VERSION 5.8 ;
BUSBITCHARS "[]" ;
DIVIDERCHAR "/" ;
UNITS
    DATABASE MICRONS 1000 ;
END UNITS

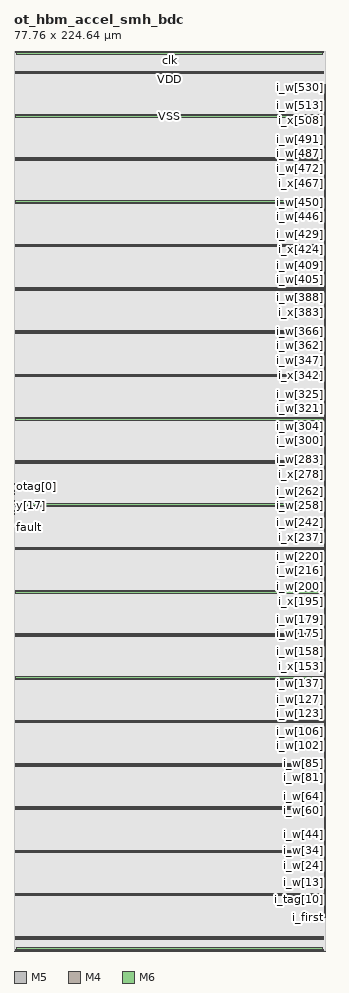
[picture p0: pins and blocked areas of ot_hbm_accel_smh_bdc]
MACRO ot_hbm_accel_smh_bdc
  FOREIGN ot_hbm_accel_smh_bdc 0 0 ;
  CLASS BLOCK ;
  SIZE 77.76 BY 224.64 ;
  PIN clk
    DIRECTION INPUT ;
    USE SIGNAL ;
    PORT
      LAYER M5 ;
        RECT  38.88 224.448 38.904 224.64 ;
    END
  END clk
  PIN fault
    DIRECTION OUTPUT ;
    USE SIGNAL ;
    PORT
      LAYER M4 ;
        RECT  0 107.712 0.192 107.736 ;
    END
  END fault
  PIN i_first
    DIRECTION INPUT ;
    USE SIGNAL ;
    PORT
      LAYER M4 ;
        RECT  77.568 8.448 77.76 8.472 ;
    END
  END i_first
  PIN i_fp4
    DIRECTION INPUT ;
    USE SIGNAL ;
    PORT
      LAYER M4 ;
        RECT  77.568 8.832 77.76 8.856 ;
    END
  END i_fp4
  PIN i_last
    DIRECTION INPUT ;
    USE SIGNAL ;
    PORT
      LAYER M4 ;
        RECT  77.568 8.64 77.76 8.664 ;
    END
  END i_last
  PIN i_tag[0]
    DIRECTION INPUT ;
    USE SIGNAL ;
    PORT
      LAYER M4 ;
        RECT  77.568 9.024 77.76 9.048 ;
    END
  END i_tag[0]
  PIN i_tag[10]
    DIRECTION INPUT ;
    USE SIGNAL ;
    PORT
      LAYER M4 ;
        RECT  77.568 10.944 77.76 10.968 ;
    END
  END i_tag[10]
  PIN i_tag[11]
    DIRECTION INPUT ;
    USE SIGNAL ;
    PORT
      LAYER M4 ;
        RECT  77.568 11.136 77.76 11.16 ;
    END
  END i_tag[11]
  PIN i_tag[12]
    DIRECTION INPUT ;
    USE SIGNAL ;
    PORT
      LAYER M4 ;
        RECT  77.568 11.328 77.76 11.352 ;
    END
  END i_tag[12]
  PIN i_tag[13]
    DIRECTION INPUT ;
    USE SIGNAL ;
    PORT
      LAYER M4 ;
        RECT  77.568 11.52 77.76 11.544 ;
    END
  END i_tag[13]
  PIN i_tag[14]
    DIRECTION INPUT ;
    USE SIGNAL ;
    PORT
      LAYER M4 ;
        RECT  77.568 11.712 77.76 11.736 ;
    END
  END i_tag[14]
  PIN i_tag[15]
    DIRECTION INPUT ;
    USE SIGNAL ;
    PORT
      LAYER M4 ;
        RECT  77.568 11.904 77.76 11.928 ;
    END
  END i_tag[15]
  PIN i_tag[1]
    DIRECTION INPUT ;
    USE SIGNAL ;
    PORT
      LAYER M4 ;
        RECT  77.568 9.216 77.76 9.24 ;
    END
  END i_tag[1]
  PIN i_tag[2]
    DIRECTION INPUT ;
    USE SIGNAL ;
    PORT
      LAYER M4 ;
        RECT  77.568 9.408 77.76 9.432 ;
    END
  END i_tag[2]
  PIN i_tag[3]
    DIRECTION INPUT ;
    USE SIGNAL ;
    PORT
      LAYER M4 ;
        RECT  77.568 9.6 77.76 9.624 ;
    END
  END i_tag[3]
  PIN i_tag[4]
    DIRECTION INPUT ;
    USE SIGNAL ;
    PORT
      LAYER M4 ;
        RECT  77.568 9.792 77.76 9.816 ;
    END
  END i_tag[4]
  PIN i_tag[5]
    DIRECTION INPUT ;
    USE SIGNAL ;
    PORT
      LAYER M4 ;
        RECT  77.568 9.984 77.76 10.008 ;
    END
  END i_tag[5]
  PIN i_tag[6]
    DIRECTION INPUT ;
    USE SIGNAL ;
    PORT
      LAYER M4 ;
        RECT  77.568 10.176 77.76 10.2 ;
    END
  END i_tag[6]
  PIN i_tag[7]
    DIRECTION INPUT ;
    USE SIGNAL ;
    PORT
      LAYER M4 ;
        RECT  77.568 10.368 77.76 10.392 ;
    END
  END i_tag[7]
  PIN i_tag[8]
    DIRECTION INPUT ;
    USE SIGNAL ;
    PORT
      LAYER M4 ;
        RECT  77.568 10.56 77.76 10.584 ;
    END
  END i_tag[8]
  PIN i_tag[9]
    DIRECTION INPUT ;
    USE SIGNAL ;
    PORT
      LAYER M4 ;
        RECT  77.568 10.752 77.76 10.776 ;
    END
  END i_tag[9]
  PIN i_v
    DIRECTION INPUT ;
    USE SIGNAL ;
    PORT
      LAYER M4 ;
        RECT  77.568 8.256 77.76 8.28 ;
    END
  END i_v
  PIN i_w[0]
    DIRECTION INPUT ;
    USE SIGNAL ;
    PORT
      LAYER M4 ;
        RECT  77.568 12.096 77.76 12.12 ;
    END
  END i_w[0]
  PIN i_w[100]
    DIRECTION INPUT ;
    USE SIGNAL ;
    PORT
      LAYER M4 ;
        RECT  77.568 50.496 77.76 50.52 ;
    END
  END i_w[100]
  PIN i_w[101]
    DIRECTION INPUT ;
    USE SIGNAL ;
    PORT
      LAYER M4 ;
        RECT  77.568 50.88 77.76 50.904 ;
    END
  END i_w[101]
  PIN i_w[102]
    DIRECTION INPUT ;
    USE SIGNAL ;
    PORT
      LAYER M4 ;
        RECT  77.568 51.264 77.76 51.288 ;
    END
  END i_w[102]
  PIN i_w[103]
    DIRECTION INPUT ;
    USE SIGNAL ;
    PORT
      LAYER M4 ;
        RECT  77.568 51.648 77.76 51.672 ;
    END
  END i_w[103]
  PIN i_w[104]
    DIRECTION INPUT ;
    USE SIGNAL ;
    PORT
      LAYER M4 ;
        RECT  77.568 52.032 77.76 52.056 ;
    END
  END i_w[104]
  PIN i_w[105]
    DIRECTION INPUT ;
    USE SIGNAL ;
    PORT
      LAYER M4 ;
        RECT  77.568 52.416 77.76 52.44 ;
    END
  END i_w[105]
  PIN i_w[106]
    DIRECTION INPUT ;
    USE SIGNAL ;
    PORT
      LAYER M4 ;
        RECT  77.568 52.8 77.76 52.824 ;
    END
  END i_w[106]
  PIN i_w[107]
    DIRECTION INPUT ;
    USE SIGNAL ;
    PORT
      LAYER M4 ;
        RECT  77.568 53.184 77.76 53.208 ;
    END
  END i_w[107]
  PIN i_w[108]
    DIRECTION INPUT ;
    USE SIGNAL ;
    PORT
      LAYER M4 ;
        RECT  77.568 53.568 77.76 53.592 ;
    END
  END i_w[108]
  PIN i_w[109]
    DIRECTION INPUT ;
    USE SIGNAL ;
    PORT
      LAYER M4 ;
        RECT  77.568 53.952 77.76 53.976 ;
    END
  END i_w[109]
  PIN i_w[10]
    DIRECTION INPUT ;
    USE SIGNAL ;
    PORT
      LAYER M4 ;
        RECT  77.568 15.936 77.76 15.96 ;
    END
  END i_w[10]
  PIN i_w[110]
    DIRECTION INPUT ;
    USE SIGNAL ;
    PORT
      LAYER M4 ;
        RECT  77.568 54.336 77.76 54.36 ;
    END
  END i_w[110]
  PIN i_w[111]
    DIRECTION INPUT ;
    USE SIGNAL ;
    PORT
      LAYER M4 ;
        RECT  77.568 54.72 77.76 54.744 ;
    END
  END i_w[111]
  PIN i_w[112]
    DIRECTION INPUT ;
    USE SIGNAL ;
    PORT
      LAYER M4 ;
        RECT  77.568 55.104 77.76 55.128 ;
    END
  END i_w[112]
  PIN i_w[113]
    DIRECTION INPUT ;
    USE SIGNAL ;
    PORT
      LAYER M4 ;
        RECT  77.568 55.488 77.76 55.512 ;
    END
  END i_w[113]
  PIN i_w[114]
    DIRECTION INPUT ;
    USE SIGNAL ;
    PORT
      LAYER M4 ;
        RECT  77.568 55.872 77.76 55.896 ;
    END
  END i_w[114]
  PIN i_w[115]
    DIRECTION INPUT ;
    USE SIGNAL ;
    PORT
      LAYER M4 ;
        RECT  77.568 56.256 77.76 56.28 ;
    END
  END i_w[115]
  PIN i_w[116]
    DIRECTION INPUT ;
    USE SIGNAL ;
    PORT
      LAYER M4 ;
        RECT  77.568 56.64 77.76 56.664 ;
    END
  END i_w[116]
  PIN i_w[117]
    DIRECTION INPUT ;
    USE SIGNAL ;
    PORT
      LAYER M4 ;
        RECT  77.568 57.024 77.76 57.048 ;
    END
  END i_w[117]
  PIN i_w[118]
    DIRECTION INPUT ;
    USE SIGNAL ;
    PORT
      LAYER M4 ;
        RECT  77.568 57.408 77.76 57.432 ;
    END
  END i_w[118]
  PIN i_w[119]
    DIRECTION INPUT ;
    USE SIGNAL ;
    PORT
      LAYER M4 ;
        RECT  77.568 57.792 77.76 57.816 ;
    END
  END i_w[119]
  PIN i_w[11]
    DIRECTION INPUT ;
    USE SIGNAL ;
    PORT
      LAYER M4 ;
        RECT  77.568 16.32 77.76 16.344 ;
    END
  END i_w[11]
  PIN i_w[120]
    DIRECTION INPUT ;
    USE SIGNAL ;
    PORT
      LAYER M4 ;
        RECT  77.568 58.176 77.76 58.2 ;
    END
  END i_w[120]
  PIN i_w[121]
    DIRECTION INPUT ;
    USE SIGNAL ;
    PORT
      LAYER M4 ;
        RECT  77.568 58.56 77.76 58.584 ;
    END
  END i_w[121]
  PIN i_w[122]
    DIRECTION INPUT ;
    USE SIGNAL ;
    PORT
      LAYER M4 ;
        RECT  77.568 58.944 77.76 58.968 ;
    END
  END i_w[122]
  PIN i_w[123]
    DIRECTION INPUT ;
    USE SIGNAL ;
    PORT
      LAYER M4 ;
        RECT  77.568 59.328 77.76 59.352 ;
    END
  END i_w[123]
  PIN i_w[124]
    DIRECTION INPUT ;
    USE SIGNAL ;
    PORT
      LAYER M4 ;
        RECT  77.568 59.712 77.76 59.736 ;
    END
  END i_w[124]
  PIN i_w[125]
    DIRECTION INPUT ;
    USE SIGNAL ;
    PORT
      LAYER M4 ;
        RECT  77.568 60.096 77.76 60.12 ;
    END
  END i_w[125]
  PIN i_w[126]
    DIRECTION INPUT ;
    USE SIGNAL ;
    PORT
      LAYER M4 ;
        RECT  77.568 60.48 77.76 60.504 ;
    END
  END i_w[126]
  PIN i_w[127]
    DIRECTION INPUT ;
    USE SIGNAL ;
    PORT
      LAYER M4 ;
        RECT  77.568 60.864 77.76 60.888 ;
    END
  END i_w[127]
  PIN i_w[128]
    DIRECTION INPUT ;
    USE SIGNAL ;
    PORT
      LAYER M4 ;
        RECT  77.568 61.248 77.76 61.272 ;
    END
  END i_w[128]
  PIN i_w[129]
    DIRECTION INPUT ;
    USE SIGNAL ;
    PORT
      LAYER M4 ;
        RECT  77.568 61.632 77.76 61.656 ;
    END
  END i_w[129]
  PIN i_w[12]
    DIRECTION INPUT ;
    USE SIGNAL ;
    PORT
      LAYER M4 ;
        RECT  77.568 16.704 77.76 16.728 ;
    END
  END i_w[12]
  PIN i_w[130]
    DIRECTION INPUT ;
    USE SIGNAL ;
    PORT
      LAYER M4 ;
        RECT  77.568 62.016 77.76 62.04 ;
    END
  END i_w[130]
  PIN i_w[131]
    DIRECTION INPUT ;
    USE SIGNAL ;
    PORT
      LAYER M4 ;
        RECT  77.568 62.4 77.76 62.424 ;
    END
  END i_w[131]
  PIN i_w[132]
    DIRECTION INPUT ;
    USE SIGNAL ;
    PORT
      LAYER M4 ;
        RECT  77.568 62.784 77.76 62.808 ;
    END
  END i_w[132]
  PIN i_w[133]
    DIRECTION INPUT ;
    USE SIGNAL ;
    PORT
      LAYER M4 ;
        RECT  77.568 63.168 77.76 63.192 ;
    END
  END i_w[133]
  PIN i_w[134]
    DIRECTION INPUT ;
    USE SIGNAL ;
    PORT
      LAYER M4 ;
        RECT  77.568 63.552 77.76 63.576 ;
    END
  END i_w[134]
  PIN i_w[135]
    DIRECTION INPUT ;
    USE SIGNAL ;
    PORT
      LAYER M4 ;
        RECT  77.568 63.936 77.76 63.96 ;
    END
  END i_w[135]
  PIN i_w[136]
    DIRECTION INPUT ;
    USE SIGNAL ;
    PORT
      LAYER M4 ;
        RECT  77.568 64.32 77.76 64.344 ;
    END
  END i_w[136]
  PIN i_w[137]
    DIRECTION INPUT ;
    USE SIGNAL ;
    PORT
      LAYER M4 ;
        RECT  77.568 64.704 77.76 64.728 ;
    END
  END i_w[137]
  PIN i_w[138]
    DIRECTION INPUT ;
    USE SIGNAL ;
    PORT
      LAYER M4 ;
        RECT  77.568 65.088 77.76 65.112 ;
    END
  END i_w[138]
  PIN i_w[139]
    DIRECTION INPUT ;
    USE SIGNAL ;
    PORT
      LAYER M4 ;
        RECT  77.568 65.472 77.76 65.496 ;
    END
  END i_w[139]
  PIN i_w[13]
    DIRECTION INPUT ;
    USE SIGNAL ;
    PORT
      LAYER M4 ;
        RECT  77.568 17.088 77.76 17.112 ;
    END
  END i_w[13]
  PIN i_w[140]
    DIRECTION INPUT ;
    USE SIGNAL ;
    PORT
      LAYER M4 ;
        RECT  77.568 65.856 77.76 65.88 ;
    END
  END i_w[140]
  PIN i_w[141]
    DIRECTION INPUT ;
    USE SIGNAL ;
    PORT
      LAYER M4 ;
        RECT  77.568 66.24 77.76 66.264 ;
    END
  END i_w[141]
  PIN i_w[142]
    DIRECTION INPUT ;
    USE SIGNAL ;
    PORT
      LAYER M4 ;
        RECT  77.568 66.624 77.76 66.648 ;
    END
  END i_w[142]
  PIN i_w[143]
    DIRECTION INPUT ;
    USE SIGNAL ;
    PORT
      LAYER M4 ;
        RECT  77.568 67.008 77.76 67.032 ;
    END
  END i_w[143]
  PIN i_w[144]
    DIRECTION INPUT ;
    USE SIGNAL ;
    PORT
      LAYER M4 ;
        RECT  77.568 67.392 77.76 67.416 ;
    END
  END i_w[144]
  PIN i_w[145]
    DIRECTION INPUT ;
    USE SIGNAL ;
    PORT
      LAYER M4 ;
        RECT  77.568 67.776 77.76 67.8 ;
    END
  END i_w[145]
  PIN i_w[146]
    DIRECTION INPUT ;
    USE SIGNAL ;
    PORT
      LAYER M4 ;
        RECT  77.568 68.16 77.76 68.184 ;
    END
  END i_w[146]
  PIN i_w[147]
    DIRECTION INPUT ;
    USE SIGNAL ;
    PORT
      LAYER M4 ;
        RECT  77.568 68.544 77.76 68.568 ;
    END
  END i_w[147]
  PIN i_w[148]
    DIRECTION INPUT ;
    USE SIGNAL ;
    PORT
      LAYER M4 ;
        RECT  77.568 68.928 77.76 68.952 ;
    END
  END i_w[148]
  PIN i_w[149]
    DIRECTION INPUT ;
    USE SIGNAL ;
    PORT
      LAYER M4 ;
        RECT  77.568 69.312 77.76 69.336 ;
    END
  END i_w[149]
  PIN i_w[14]
    DIRECTION INPUT ;
    USE SIGNAL ;
    PORT
      LAYER M4 ;
        RECT  77.568 17.472 77.76 17.496 ;
    END
  END i_w[14]
  PIN i_w[150]
    DIRECTION INPUT ;
    USE SIGNAL ;
    PORT
      LAYER M4 ;
        RECT  77.568 69.696 77.76 69.72 ;
    END
  END i_w[150]
  PIN i_w[151]
    DIRECTION INPUT ;
    USE SIGNAL ;
    PORT
      LAYER M4 ;
        RECT  77.568 70.08 77.76 70.104 ;
    END
  END i_w[151]
  PIN i_w[152]
    DIRECTION INPUT ;
    USE SIGNAL ;
    PORT
      LAYER M4 ;
        RECT  77.568 70.464 77.76 70.488 ;
    END
  END i_w[152]
  PIN i_w[153]
    DIRECTION INPUT ;
    USE SIGNAL ;
    PORT
      LAYER M4 ;
        RECT  77.568 70.848 77.76 70.872 ;
    END
  END i_w[153]
  PIN i_w[154]
    DIRECTION INPUT ;
    USE SIGNAL ;
    PORT
      LAYER M4 ;
        RECT  77.568 71.232 77.76 71.256 ;
    END
  END i_w[154]
  PIN i_w[155]
    DIRECTION INPUT ;
    USE SIGNAL ;
    PORT
      LAYER M4 ;
        RECT  77.568 71.616 77.76 71.64 ;
    END
  END i_w[155]
  PIN i_w[156]
    DIRECTION INPUT ;
    USE SIGNAL ;
    PORT
      LAYER M4 ;
        RECT  77.568 72 77.76 72.024 ;
    END
  END i_w[156]
  PIN i_w[157]
    DIRECTION INPUT ;
    USE SIGNAL ;
    PORT
      LAYER M4 ;
        RECT  77.568 72.384 77.76 72.408 ;
    END
  END i_w[157]
  PIN i_w[158]
    DIRECTION INPUT ;
    USE SIGNAL ;
    PORT
      LAYER M4 ;
        RECT  77.568 72.768 77.76 72.792 ;
    END
  END i_w[158]
  PIN i_w[159]
    DIRECTION INPUT ;
    USE SIGNAL ;
    PORT
      LAYER M4 ;
        RECT  77.568 73.152 77.76 73.176 ;
    END
  END i_w[159]
  PIN i_w[15]
    DIRECTION INPUT ;
    USE SIGNAL ;
    PORT
      LAYER M4 ;
        RECT  77.568 17.856 77.76 17.88 ;
    END
  END i_w[15]
  PIN i_w[160]
    DIRECTION INPUT ;
    USE SIGNAL ;
    PORT
      LAYER M4 ;
        RECT  77.568 73.536 77.76 73.56 ;
    END
  END i_w[160]
  PIN i_w[161]
    DIRECTION INPUT ;
    USE SIGNAL ;
    PORT
      LAYER M4 ;
        RECT  77.568 73.92 77.76 73.944 ;
    END
  END i_w[161]
  PIN i_w[162]
    DIRECTION INPUT ;
    USE SIGNAL ;
    PORT
      LAYER M4 ;
        RECT  77.568 74.304 77.76 74.328 ;
    END
  END i_w[162]
  PIN i_w[163]
    DIRECTION INPUT ;
    USE SIGNAL ;
    PORT
      LAYER M4 ;
        RECT  77.568 74.688 77.76 74.712 ;
    END
  END i_w[163]
  PIN i_w[164]
    DIRECTION INPUT ;
    USE SIGNAL ;
    PORT
      LAYER M4 ;
        RECT  77.568 75.072 77.76 75.096 ;
    END
  END i_w[164]
  PIN i_w[165]
    DIRECTION INPUT ;
    USE SIGNAL ;
    PORT
      LAYER M4 ;
        RECT  77.568 75.456 77.76 75.48 ;
    END
  END i_w[165]
  PIN i_w[166]
    DIRECTION INPUT ;
    USE SIGNAL ;
    PORT
      LAYER M4 ;
        RECT  77.568 75.84 77.76 75.864 ;
    END
  END i_w[166]
  PIN i_w[167]
    DIRECTION INPUT ;
    USE SIGNAL ;
    PORT
      LAYER M4 ;
        RECT  77.568 76.224 77.76 76.248 ;
    END
  END i_w[167]
  PIN i_w[168]
    DIRECTION INPUT ;
    USE SIGNAL ;
    PORT
      LAYER M4 ;
        RECT  77.568 76.608 77.76 76.632 ;
    END
  END i_w[168]
  PIN i_w[169]
    DIRECTION INPUT ;
    USE SIGNAL ;
    PORT
      LAYER M4 ;
        RECT  77.568 76.992 77.76 77.016 ;
    END
  END i_w[169]
  PIN i_w[16]
    DIRECTION INPUT ;
    USE SIGNAL ;
    PORT
      LAYER M4 ;
        RECT  77.568 18.24 77.76 18.264 ;
    END
  END i_w[16]
  PIN i_w[170]
    DIRECTION INPUT ;
    USE SIGNAL ;
    PORT
      LAYER M4 ;
        RECT  77.568 77.376 77.76 77.4 ;
    END
  END i_w[170]
  PIN i_w[171]
    DIRECTION INPUT ;
    USE SIGNAL ;
    PORT
      LAYER M4 ;
        RECT  77.568 77.76 77.76 77.784 ;
    END
  END i_w[171]
  PIN i_w[172]
    DIRECTION INPUT ;
    USE SIGNAL ;
    PORT
      LAYER M4 ;
        RECT  77.568 78.144 77.76 78.168 ;
    END
  END i_w[172]
  PIN i_w[173]
    DIRECTION INPUT ;
    USE SIGNAL ;
    PORT
      LAYER M4 ;
        RECT  77.568 78.528 77.76 78.552 ;
    END
  END i_w[173]
  PIN i_w[174]
    DIRECTION INPUT ;
    USE SIGNAL ;
    PORT
      LAYER M4 ;
        RECT  77.568 78.912 77.76 78.936 ;
    END
  END i_w[174]
  PIN i_w[175]
    DIRECTION INPUT ;
    USE SIGNAL ;
    PORT
      LAYER M4 ;
        RECT  77.568 79.296 77.76 79.32 ;
    END
  END i_w[175]
  PIN i_w[176]
    DIRECTION INPUT ;
    USE SIGNAL ;
    PORT
      LAYER M4 ;
        RECT  77.568 79.68 77.76 79.704 ;
    END
  END i_w[176]
  PIN i_w[177]
    DIRECTION INPUT ;
    USE SIGNAL ;
    PORT
      LAYER M4 ;
        RECT  77.568 80.064 77.76 80.088 ;
    END
  END i_w[177]
  PIN i_w[178]
    DIRECTION INPUT ;
    USE SIGNAL ;
    PORT
      LAYER M4 ;
        RECT  77.568 80.448 77.76 80.472 ;
    END
  END i_w[178]
  PIN i_w[179]
    DIRECTION INPUT ;
    USE SIGNAL ;
    PORT
      LAYER M4 ;
        RECT  77.568 80.832 77.76 80.856 ;
    END
  END i_w[179]
  PIN i_w[17]
    DIRECTION INPUT ;
    USE SIGNAL ;
    PORT
      LAYER M4 ;
        RECT  77.568 18.624 77.76 18.648 ;
    END
  END i_w[17]
  PIN i_w[180]
    DIRECTION INPUT ;
    USE SIGNAL ;
    PORT
      LAYER M4 ;
        RECT  77.568 81.216 77.76 81.24 ;
    END
  END i_w[180]
  PIN i_w[181]
    DIRECTION INPUT ;
    USE SIGNAL ;
    PORT
      LAYER M4 ;
        RECT  77.568 81.6 77.76 81.624 ;
    END
  END i_w[181]
  PIN i_w[182]
    DIRECTION INPUT ;
    USE SIGNAL ;
    PORT
      LAYER M4 ;
        RECT  77.568 81.984 77.76 82.008 ;
    END
  END i_w[182]
  PIN i_w[183]
    DIRECTION INPUT ;
    USE SIGNAL ;
    PORT
      LAYER M4 ;
        RECT  77.568 82.368 77.76 82.392 ;
    END
  END i_w[183]
  PIN i_w[184]
    DIRECTION INPUT ;
    USE SIGNAL ;
    PORT
      LAYER M4 ;
        RECT  77.568 82.752 77.76 82.776 ;
    END
  END i_w[184]
  PIN i_w[185]
    DIRECTION INPUT ;
    USE SIGNAL ;
    PORT
      LAYER M4 ;
        RECT  77.568 83.136 77.76 83.16 ;
    END
  END i_w[185]
  PIN i_w[186]
    DIRECTION INPUT ;
    USE SIGNAL ;
    PORT
      LAYER M4 ;
        RECT  77.568 83.52 77.76 83.544 ;
    END
  END i_w[186]
  PIN i_w[187]
    DIRECTION INPUT ;
    USE SIGNAL ;
    PORT
      LAYER M4 ;
        RECT  77.568 83.904 77.76 83.928 ;
    END
  END i_w[187]
  PIN i_w[188]
    DIRECTION INPUT ;
    USE SIGNAL ;
    PORT
      LAYER M4 ;
        RECT  77.568 84.288 77.76 84.312 ;
    END
  END i_w[188]
  PIN i_w[189]
    DIRECTION INPUT ;
    USE SIGNAL ;
    PORT
      LAYER M4 ;
        RECT  77.568 84.672 77.76 84.696 ;
    END
  END i_w[189]
  PIN i_w[18]
    DIRECTION INPUT ;
    USE SIGNAL ;
    PORT
      LAYER M4 ;
        RECT  77.568 19.008 77.76 19.032 ;
    END
  END i_w[18]
  PIN i_w[190]
    DIRECTION INPUT ;
    USE SIGNAL ;
    PORT
      LAYER M4 ;
        RECT  77.568 85.056 77.76 85.08 ;
    END
  END i_w[190]
  PIN i_w[191]
    DIRECTION INPUT ;
    USE SIGNAL ;
    PORT
      LAYER M4 ;
        RECT  77.568 85.44 77.76 85.464 ;
    END
  END i_w[191]
  PIN i_w[192]
    DIRECTION INPUT ;
    USE SIGNAL ;
    PORT
      LAYER M4 ;
        RECT  77.568 85.824 77.76 85.848 ;
    END
  END i_w[192]
  PIN i_w[193]
    DIRECTION INPUT ;
    USE SIGNAL ;
    PORT
      LAYER M4 ;
        RECT  77.568 86.208 77.76 86.232 ;
    END
  END i_w[193]
  PIN i_w[194]
    DIRECTION INPUT ;
    USE SIGNAL ;
    PORT
      LAYER M4 ;
        RECT  77.568 86.592 77.76 86.616 ;
    END
  END i_w[194]
  PIN i_w[195]
    DIRECTION INPUT ;
    USE SIGNAL ;
    PORT
      LAYER M4 ;
        RECT  77.568 86.976 77.76 87 ;
    END
  END i_w[195]
  PIN i_w[196]
    DIRECTION INPUT ;
    USE SIGNAL ;
    PORT
      LAYER M4 ;
        RECT  77.568 87.36 77.76 87.384 ;
    END
  END i_w[196]
  PIN i_w[197]
    DIRECTION INPUT ;
    USE SIGNAL ;
    PORT
      LAYER M4 ;
        RECT  77.568 87.744 77.76 87.768 ;
    END
  END i_w[197]
  PIN i_w[198]
    DIRECTION INPUT ;
    USE SIGNAL ;
    PORT
      LAYER M4 ;
        RECT  77.568 88.128 77.76 88.152 ;
    END
  END i_w[198]
  PIN i_w[199]
    DIRECTION INPUT ;
    USE SIGNAL ;
    PORT
      LAYER M4 ;
        RECT  77.568 88.512 77.76 88.536 ;
    END
  END i_w[199]
  PIN i_w[19]
    DIRECTION INPUT ;
    USE SIGNAL ;
    PORT
      LAYER M4 ;
        RECT  77.568 19.392 77.76 19.416 ;
    END
  END i_w[19]
  PIN i_w[1]
    DIRECTION INPUT ;
    USE SIGNAL ;
    PORT
      LAYER M4 ;
        RECT  77.568 12.48 77.76 12.504 ;
    END
  END i_w[1]
  PIN i_w[200]
    DIRECTION INPUT ;
    USE SIGNAL ;
    PORT
      LAYER M4 ;
        RECT  77.568 88.896 77.76 88.92 ;
    END
  END i_w[200]
  PIN i_w[201]
    DIRECTION INPUT ;
    USE SIGNAL ;
    PORT
      LAYER M4 ;
        RECT  77.568 89.28 77.76 89.304 ;
    END
  END i_w[201]
  PIN i_w[202]
    DIRECTION INPUT ;
    USE SIGNAL ;
    PORT
      LAYER M4 ;
        RECT  77.568 89.664 77.76 89.688 ;
    END
  END i_w[202]
  PIN i_w[203]
    DIRECTION INPUT ;
    USE SIGNAL ;
    PORT
      LAYER M4 ;
        RECT  77.568 90.048 77.76 90.072 ;
    END
  END i_w[203]
  PIN i_w[204]
    DIRECTION INPUT ;
    USE SIGNAL ;
    PORT
      LAYER M4 ;
        RECT  77.568 90.432 77.76 90.456 ;
    END
  END i_w[204]
  PIN i_w[205]
    DIRECTION INPUT ;
    USE SIGNAL ;
    PORT
      LAYER M4 ;
        RECT  77.568 90.816 77.76 90.84 ;
    END
  END i_w[205]
  PIN i_w[206]
    DIRECTION INPUT ;
    USE SIGNAL ;
    PORT
      LAYER M4 ;
        RECT  77.568 91.2 77.76 91.224 ;
    END
  END i_w[206]
  PIN i_w[207]
    DIRECTION INPUT ;
    USE SIGNAL ;
    PORT
      LAYER M4 ;
        RECT  77.568 91.584 77.76 91.608 ;
    END
  END i_w[207]
  PIN i_w[208]
    DIRECTION INPUT ;
    USE SIGNAL ;
    PORT
      LAYER M4 ;
        RECT  77.568 91.968 77.76 91.992 ;
    END
  END i_w[208]
  PIN i_w[209]
    DIRECTION INPUT ;
    USE SIGNAL ;
    PORT
      LAYER M4 ;
        RECT  77.568 92.352 77.76 92.376 ;
    END
  END i_w[209]
  PIN i_w[20]
    DIRECTION INPUT ;
    USE SIGNAL ;
    PORT
      LAYER M4 ;
        RECT  77.568 19.776 77.76 19.8 ;
    END
  END i_w[20]
  PIN i_w[210]
    DIRECTION INPUT ;
    USE SIGNAL ;
    PORT
      LAYER M4 ;
        RECT  77.568 92.736 77.76 92.76 ;
    END
  END i_w[210]
  PIN i_w[211]
    DIRECTION INPUT ;
    USE SIGNAL ;
    PORT
      LAYER M4 ;
        RECT  77.568 93.12 77.76 93.144 ;
    END
  END i_w[211]
  PIN i_w[212]
    DIRECTION INPUT ;
    USE SIGNAL ;
    PORT
      LAYER M4 ;
        RECT  77.568 93.504 77.76 93.528 ;
    END
  END i_w[212]
  PIN i_w[213]
    DIRECTION INPUT ;
    USE SIGNAL ;
    PORT
      LAYER M4 ;
        RECT  77.568 93.888 77.76 93.912 ;
    END
  END i_w[213]
  PIN i_w[214]
    DIRECTION INPUT ;
    USE SIGNAL ;
    PORT
      LAYER M4 ;
        RECT  77.568 94.272 77.76 94.296 ;
    END
  END i_w[214]
  PIN i_w[215]
    DIRECTION INPUT ;
    USE SIGNAL ;
    PORT
      LAYER M4 ;
        RECT  77.568 94.656 77.76 94.68 ;
    END
  END i_w[215]
  PIN i_w[216]
    DIRECTION INPUT ;
    USE SIGNAL ;
    PORT
      LAYER M4 ;
        RECT  77.568 95.04 77.76 95.064 ;
    END
  END i_w[216]
  PIN i_w[217]
    DIRECTION INPUT ;
    USE SIGNAL ;
    PORT
      LAYER M4 ;
        RECT  77.568 95.424 77.76 95.448 ;
    END
  END i_w[217]
  PIN i_w[218]
    DIRECTION INPUT ;
    USE SIGNAL ;
    PORT
      LAYER M4 ;
        RECT  77.568 95.808 77.76 95.832 ;
    END
  END i_w[218]
  PIN i_w[219]
    DIRECTION INPUT ;
    USE SIGNAL ;
    PORT
      LAYER M4 ;
        RECT  77.568 96.192 77.76 96.216 ;
    END
  END i_w[219]
  PIN i_w[21]
    DIRECTION INPUT ;
    USE SIGNAL ;
    PORT
      LAYER M4 ;
        RECT  77.568 20.16 77.76 20.184 ;
    END
  END i_w[21]
  PIN i_w[220]
    DIRECTION INPUT ;
    USE SIGNAL ;
    PORT
      LAYER M4 ;
        RECT  77.568 96.576 77.76 96.6 ;
    END
  END i_w[220]
  PIN i_w[221]
    DIRECTION INPUT ;
    USE SIGNAL ;
    PORT
      LAYER M4 ;
        RECT  77.568 96.96 77.76 96.984 ;
    END
  END i_w[221]
  PIN i_w[222]
    DIRECTION INPUT ;
    USE SIGNAL ;
    PORT
      LAYER M4 ;
        RECT  77.568 97.344 77.76 97.368 ;
    END
  END i_w[222]
  PIN i_w[223]
    DIRECTION INPUT ;
    USE SIGNAL ;
    PORT
      LAYER M4 ;
        RECT  77.568 97.728 77.76 97.752 ;
    END
  END i_w[223]
  PIN i_w[224]
    DIRECTION INPUT ;
    USE SIGNAL ;
    PORT
      LAYER M4 ;
        RECT  77.568 98.112 77.76 98.136 ;
    END
  END i_w[224]
  PIN i_w[225]
    DIRECTION INPUT ;
    USE SIGNAL ;
    PORT
      LAYER M4 ;
        RECT  77.568 98.496 77.76 98.52 ;
    END
  END i_w[225]
  PIN i_w[226]
    DIRECTION INPUT ;
    USE SIGNAL ;
    PORT
      LAYER M4 ;
        RECT  77.568 98.88 77.76 98.904 ;
    END
  END i_w[226]
  PIN i_w[227]
    DIRECTION INPUT ;
    USE SIGNAL ;
    PORT
      LAYER M4 ;
        RECT  77.568 99.264 77.76 99.288 ;
    END
  END i_w[227]
  PIN i_w[228]
    DIRECTION INPUT ;
    USE SIGNAL ;
    PORT
      LAYER M4 ;
        RECT  77.568 99.648 77.76 99.672 ;
    END
  END i_w[228]
  PIN i_w[229]
    DIRECTION INPUT ;
    USE SIGNAL ;
    PORT
      LAYER M4 ;
        RECT  77.568 100.032 77.76 100.056 ;
    END
  END i_w[229]
  PIN i_w[22]
    DIRECTION INPUT ;
    USE SIGNAL ;
    PORT
      LAYER M4 ;
        RECT  77.568 20.544 77.76 20.568 ;
    END
  END i_w[22]
  PIN i_w[230]
    DIRECTION INPUT ;
    USE SIGNAL ;
    PORT
      LAYER M4 ;
        RECT  77.568 100.416 77.76 100.44 ;
    END
  END i_w[230]
  PIN i_w[231]
    DIRECTION INPUT ;
    USE SIGNAL ;
    PORT
      LAYER M4 ;
        RECT  77.568 100.8 77.76 100.824 ;
    END
  END i_w[231]
  PIN i_w[232]
    DIRECTION INPUT ;
    USE SIGNAL ;
    PORT
      LAYER M4 ;
        RECT  77.568 101.184 77.76 101.208 ;
    END
  END i_w[232]
  PIN i_w[233]
    DIRECTION INPUT ;
    USE SIGNAL ;
    PORT
      LAYER M4 ;
        RECT  77.568 101.568 77.76 101.592 ;
    END
  END i_w[233]
  PIN i_w[234]
    DIRECTION INPUT ;
    USE SIGNAL ;
    PORT
      LAYER M4 ;
        RECT  77.568 101.952 77.76 101.976 ;
    END
  END i_w[234]
  PIN i_w[235]
    DIRECTION INPUT ;
    USE SIGNAL ;
    PORT
      LAYER M4 ;
        RECT  77.568 102.336 77.76 102.36 ;
    END
  END i_w[235]
  PIN i_w[236]
    DIRECTION INPUT ;
    USE SIGNAL ;
    PORT
      LAYER M4 ;
        RECT  77.568 102.72 77.76 102.744 ;
    END
  END i_w[236]
  PIN i_w[237]
    DIRECTION INPUT ;
    USE SIGNAL ;
    PORT
      LAYER M4 ;
        RECT  77.568 103.104 77.76 103.128 ;
    END
  END i_w[237]
  PIN i_w[238]
    DIRECTION INPUT ;
    USE SIGNAL ;
    PORT
      LAYER M4 ;
        RECT  77.568 103.488 77.76 103.512 ;
    END
  END i_w[238]
  PIN i_w[239]
    DIRECTION INPUT ;
    USE SIGNAL ;
    PORT
      LAYER M4 ;
        RECT  77.568 103.872 77.76 103.896 ;
    END
  END i_w[239]
  PIN i_w[23]
    DIRECTION INPUT ;
    USE SIGNAL ;
    PORT
      LAYER M4 ;
        RECT  77.568 20.928 77.76 20.952 ;
    END
  END i_w[23]
  PIN i_w[240]
    DIRECTION INPUT ;
    USE SIGNAL ;
    PORT
      LAYER M4 ;
        RECT  77.568 104.256 77.76 104.28 ;
    END
  END i_w[240]
  PIN i_w[241]
    DIRECTION INPUT ;
    USE SIGNAL ;
    PORT
      LAYER M4 ;
        RECT  77.568 104.64 77.76 104.664 ;
    END
  END i_w[241]
  PIN i_w[242]
    DIRECTION INPUT ;
    USE SIGNAL ;
    PORT
      LAYER M4 ;
        RECT  77.568 105.024 77.76 105.048 ;
    END
  END i_w[242]
  PIN i_w[243]
    DIRECTION INPUT ;
    USE SIGNAL ;
    PORT
      LAYER M4 ;
        RECT  77.568 105.408 77.76 105.432 ;
    END
  END i_w[243]
  PIN i_w[244]
    DIRECTION INPUT ;
    USE SIGNAL ;
    PORT
      LAYER M4 ;
        RECT  77.568 105.792 77.76 105.816 ;
    END
  END i_w[244]
  PIN i_w[245]
    DIRECTION INPUT ;
    USE SIGNAL ;
    PORT
      LAYER M4 ;
        RECT  77.568 106.176 77.76 106.2 ;
    END
  END i_w[245]
  PIN i_w[246]
    DIRECTION INPUT ;
    USE SIGNAL ;
    PORT
      LAYER M4 ;
        RECT  77.568 106.56 77.76 106.584 ;
    END
  END i_w[246]
  PIN i_w[247]
    DIRECTION INPUT ;
    USE SIGNAL ;
    PORT
      LAYER M4 ;
        RECT  77.568 106.944 77.76 106.968 ;
    END
  END i_w[247]
  PIN i_w[248]
    DIRECTION INPUT ;
    USE SIGNAL ;
    PORT
      LAYER M4 ;
        RECT  77.568 107.328 77.76 107.352 ;
    END
  END i_w[248]
  PIN i_w[249]
    DIRECTION INPUT ;
    USE SIGNAL ;
    PORT
      LAYER M4 ;
        RECT  77.568 107.712 77.76 107.736 ;
    END
  END i_w[249]
  PIN i_w[24]
    DIRECTION INPUT ;
    USE SIGNAL ;
    PORT
      LAYER M4 ;
        RECT  77.568 21.312 77.76 21.336 ;
    END
  END i_w[24]
  PIN i_w[250]
    DIRECTION INPUT ;
    USE SIGNAL ;
    PORT
      LAYER M4 ;
        RECT  77.568 108.096 77.76 108.12 ;
    END
  END i_w[250]
  PIN i_w[251]
    DIRECTION INPUT ;
    USE SIGNAL ;
    PORT
      LAYER M4 ;
        RECT  77.568 108.48 77.76 108.504 ;
    END
  END i_w[251]
  PIN i_w[252]
    DIRECTION INPUT ;
    USE SIGNAL ;
    PORT
      LAYER M4 ;
        RECT  77.568 108.864 77.76 108.888 ;
    END
  END i_w[252]
  PIN i_w[253]
    DIRECTION INPUT ;
    USE SIGNAL ;
    PORT
      LAYER M4 ;
        RECT  77.568 109.248 77.76 109.272 ;
    END
  END i_w[253]
  PIN i_w[254]
    DIRECTION INPUT ;
    USE SIGNAL ;
    PORT
      LAYER M4 ;
        RECT  77.568 109.632 77.76 109.656 ;
    END
  END i_w[254]
  PIN i_w[255]
    DIRECTION INPUT ;
    USE SIGNAL ;
    PORT
      LAYER M4 ;
        RECT  77.568 110.016 77.76 110.04 ;
    END
  END i_w[255]
  PIN i_w[256]
    DIRECTION INPUT ;
    USE SIGNAL ;
    PORT
      LAYER M4 ;
        RECT  77.568 110.4 77.76 110.424 ;
    END
  END i_w[256]
  PIN i_w[257]
    DIRECTION INPUT ;
    USE SIGNAL ;
    PORT
      LAYER M4 ;
        RECT  77.568 110.784 77.76 110.808 ;
    END
  END i_w[257]
  PIN i_w[258]
    DIRECTION INPUT ;
    USE SIGNAL ;
    PORT
      LAYER M4 ;
        RECT  77.568 111.168 77.76 111.192 ;
    END
  END i_w[258]
  PIN i_w[259]
    DIRECTION INPUT ;
    USE SIGNAL ;
    PORT
      LAYER M4 ;
        RECT  77.568 111.552 77.76 111.576 ;
    END
  END i_w[259]
  PIN i_w[25]
    DIRECTION INPUT ;
    USE SIGNAL ;
    PORT
      LAYER M4 ;
        RECT  77.568 21.696 77.76 21.72 ;
    END
  END i_w[25]
  PIN i_w[260]
    DIRECTION INPUT ;
    USE SIGNAL ;
    PORT
      LAYER M4 ;
        RECT  77.568 111.936 77.76 111.96 ;
    END
  END i_w[260]
  PIN i_w[261]
    DIRECTION INPUT ;
    USE SIGNAL ;
    PORT
      LAYER M4 ;
        RECT  77.568 112.32 77.76 112.344 ;
    END
  END i_w[261]
  PIN i_w[262]
    DIRECTION INPUT ;
    USE SIGNAL ;
    PORT
      LAYER M4 ;
        RECT  77.568 112.704 77.76 112.728 ;
    END
  END i_w[262]
  PIN i_w[263]
    DIRECTION INPUT ;
    USE SIGNAL ;
    PORT
      LAYER M4 ;
        RECT  77.568 113.088 77.76 113.112 ;
    END
  END i_w[263]
  PIN i_w[264]
    DIRECTION INPUT ;
    USE SIGNAL ;
    PORT
      LAYER M4 ;
        RECT  77.568 113.472 77.76 113.496 ;
    END
  END i_w[264]
  PIN i_w[265]
    DIRECTION INPUT ;
    USE SIGNAL ;
    PORT
      LAYER M4 ;
        RECT  77.568 113.856 77.76 113.88 ;
    END
  END i_w[265]
  PIN i_w[266]
    DIRECTION INPUT ;
    USE SIGNAL ;
    PORT
      LAYER M4 ;
        RECT  77.568 114.24 77.76 114.264 ;
    END
  END i_w[266]
  PIN i_w[267]
    DIRECTION INPUT ;
    USE SIGNAL ;
    PORT
      LAYER M4 ;
        RECT  77.568 114.624 77.76 114.648 ;
    END
  END i_w[267]
  PIN i_w[268]
    DIRECTION INPUT ;
    USE SIGNAL ;
    PORT
      LAYER M4 ;
        RECT  77.568 115.008 77.76 115.032 ;
    END
  END i_w[268]
  PIN i_w[269]
    DIRECTION INPUT ;
    USE SIGNAL ;
    PORT
      LAYER M4 ;
        RECT  77.568 115.392 77.76 115.416 ;
    END
  END i_w[269]
  PIN i_w[26]
    DIRECTION INPUT ;
    USE SIGNAL ;
    PORT
      LAYER M4 ;
        RECT  77.568 22.08 77.76 22.104 ;
    END
  END i_w[26]
  PIN i_w[270]
    DIRECTION INPUT ;
    USE SIGNAL ;
    PORT
      LAYER M4 ;
        RECT  77.568 115.776 77.76 115.8 ;
    END
  END i_w[270]
  PIN i_w[271]
    DIRECTION INPUT ;
    USE SIGNAL ;
    PORT
      LAYER M4 ;
        RECT  77.568 116.16 77.76 116.184 ;
    END
  END i_w[271]
  PIN i_w[272]
    DIRECTION INPUT ;
    USE SIGNAL ;
    PORT
      LAYER M4 ;
        RECT  77.568 116.544 77.76 116.568 ;
    END
  END i_w[272]
  PIN i_w[273]
    DIRECTION INPUT ;
    USE SIGNAL ;
    PORT
      LAYER M4 ;
        RECT  77.568 116.928 77.76 116.952 ;
    END
  END i_w[273]
  PIN i_w[274]
    DIRECTION INPUT ;
    USE SIGNAL ;
    PORT
      LAYER M4 ;
        RECT  77.568 117.312 77.76 117.336 ;
    END
  END i_w[274]
  PIN i_w[275]
    DIRECTION INPUT ;
    USE SIGNAL ;
    PORT
      LAYER M4 ;
        RECT  77.568 117.696 77.76 117.72 ;
    END
  END i_w[275]
  PIN i_w[276]
    DIRECTION INPUT ;
    USE SIGNAL ;
    PORT
      LAYER M4 ;
        RECT  77.568 118.08 77.76 118.104 ;
    END
  END i_w[276]
  PIN i_w[277]
    DIRECTION INPUT ;
    USE SIGNAL ;
    PORT
      LAYER M4 ;
        RECT  77.568 118.464 77.76 118.488 ;
    END
  END i_w[277]
  PIN i_w[278]
    DIRECTION INPUT ;
    USE SIGNAL ;
    PORT
      LAYER M4 ;
        RECT  77.568 118.848 77.76 118.872 ;
    END
  END i_w[278]
  PIN i_w[279]
    DIRECTION INPUT ;
    USE SIGNAL ;
    PORT
      LAYER M4 ;
        RECT  77.568 119.232 77.76 119.256 ;
    END
  END i_w[279]
  PIN i_w[27]
    DIRECTION INPUT ;
    USE SIGNAL ;
    PORT
      LAYER M4 ;
        RECT  77.568 22.464 77.76 22.488 ;
    END
  END i_w[27]
  PIN i_w[280]
    DIRECTION INPUT ;
    USE SIGNAL ;
    PORT
      LAYER M4 ;
        RECT  77.568 119.616 77.76 119.64 ;
    END
  END i_w[280]
  PIN i_w[281]
    DIRECTION INPUT ;
    USE SIGNAL ;
    PORT
      LAYER M4 ;
        RECT  77.568 120 77.76 120.024 ;
    END
  END i_w[281]
  PIN i_w[282]
    DIRECTION INPUT ;
    USE SIGNAL ;
    PORT
      LAYER M4 ;
        RECT  77.568 120.384 77.76 120.408 ;
    END
  END i_w[282]
  PIN i_w[283]
    DIRECTION INPUT ;
    USE SIGNAL ;
    PORT
      LAYER M4 ;
        RECT  77.568 120.768 77.76 120.792 ;
    END
  END i_w[283]
  PIN i_w[284]
    DIRECTION INPUT ;
    USE SIGNAL ;
    PORT
      LAYER M4 ;
        RECT  77.568 121.152 77.76 121.176 ;
    END
  END i_w[284]
  PIN i_w[285]
    DIRECTION INPUT ;
    USE SIGNAL ;
    PORT
      LAYER M4 ;
        RECT  77.568 121.536 77.76 121.56 ;
    END
  END i_w[285]
  PIN i_w[286]
    DIRECTION INPUT ;
    USE SIGNAL ;
    PORT
      LAYER M4 ;
        RECT  77.568 121.92 77.76 121.944 ;
    END
  END i_w[286]
  PIN i_w[287]
    DIRECTION INPUT ;
    USE SIGNAL ;
    PORT
      LAYER M4 ;
        RECT  77.568 122.304 77.76 122.328 ;
    END
  END i_w[287]
  PIN i_w[288]
    DIRECTION INPUT ;
    USE SIGNAL ;
    PORT
      LAYER M4 ;
        RECT  77.568 122.688 77.76 122.712 ;
    END
  END i_w[288]
  PIN i_w[289]
    DIRECTION INPUT ;
    USE SIGNAL ;
    PORT
      LAYER M4 ;
        RECT  77.568 123.072 77.76 123.096 ;
    END
  END i_w[289]
  PIN i_w[28]
    DIRECTION INPUT ;
    USE SIGNAL ;
    PORT
      LAYER M4 ;
        RECT  77.568 22.848 77.76 22.872 ;
    END
  END i_w[28]
  PIN i_w[290]
    DIRECTION INPUT ;
    USE SIGNAL ;
    PORT
      LAYER M4 ;
        RECT  77.568 123.456 77.76 123.48 ;
    END
  END i_w[290]
  PIN i_w[291]
    DIRECTION INPUT ;
    USE SIGNAL ;
    PORT
      LAYER M4 ;
        RECT  77.568 123.84 77.76 123.864 ;
    END
  END i_w[291]
  PIN i_w[292]
    DIRECTION INPUT ;
    USE SIGNAL ;
    PORT
      LAYER M4 ;
        RECT  77.568 124.224 77.76 124.248 ;
    END
  END i_w[292]
  PIN i_w[293]
    DIRECTION INPUT ;
    USE SIGNAL ;
    PORT
      LAYER M4 ;
        RECT  77.568 124.608 77.76 124.632 ;
    END
  END i_w[293]
  PIN i_w[294]
    DIRECTION INPUT ;
    USE SIGNAL ;
    PORT
      LAYER M4 ;
        RECT  77.568 124.992 77.76 125.016 ;
    END
  END i_w[294]
  PIN i_w[295]
    DIRECTION INPUT ;
    USE SIGNAL ;
    PORT
      LAYER M4 ;
        RECT  77.568 125.376 77.76 125.4 ;
    END
  END i_w[295]
  PIN i_w[296]
    DIRECTION INPUT ;
    USE SIGNAL ;
    PORT
      LAYER M4 ;
        RECT  77.568 125.76 77.76 125.784 ;
    END
  END i_w[296]
  PIN i_w[297]
    DIRECTION INPUT ;
    USE SIGNAL ;
    PORT
      LAYER M4 ;
        RECT  77.568 126.144 77.76 126.168 ;
    END
  END i_w[297]
  PIN i_w[298]
    DIRECTION INPUT ;
    USE SIGNAL ;
    PORT
      LAYER M4 ;
        RECT  77.568 126.528 77.76 126.552 ;
    END
  END i_w[298]
  PIN i_w[299]
    DIRECTION INPUT ;
    USE SIGNAL ;
    PORT
      LAYER M4 ;
        RECT  77.568 126.912 77.76 126.936 ;
    END
  END i_w[299]
  PIN i_w[29]
    DIRECTION INPUT ;
    USE SIGNAL ;
    PORT
      LAYER M4 ;
        RECT  77.568 23.232 77.76 23.256 ;
    END
  END i_w[29]
  PIN i_w[2]
    DIRECTION INPUT ;
    USE SIGNAL ;
    PORT
      LAYER M4 ;
        RECT  77.568 12.864 77.76 12.888 ;
    END
  END i_w[2]
  PIN i_w[300]
    DIRECTION INPUT ;
    USE SIGNAL ;
    PORT
      LAYER M4 ;
        RECT  77.568 127.296 77.76 127.32 ;
    END
  END i_w[300]
  PIN i_w[301]
    DIRECTION INPUT ;
    USE SIGNAL ;
    PORT
      LAYER M4 ;
        RECT  77.568 127.68 77.76 127.704 ;
    END
  END i_w[301]
  PIN i_w[302]
    DIRECTION INPUT ;
    USE SIGNAL ;
    PORT
      LAYER M4 ;
        RECT  77.568 128.064 77.76 128.088 ;
    END
  END i_w[302]
  PIN i_w[303]
    DIRECTION INPUT ;
    USE SIGNAL ;
    PORT
      LAYER M4 ;
        RECT  77.568 128.448 77.76 128.472 ;
    END
  END i_w[303]
  PIN i_w[304]
    DIRECTION INPUT ;
    USE SIGNAL ;
    PORT
      LAYER M4 ;
        RECT  77.568 128.832 77.76 128.856 ;
    END
  END i_w[304]
  PIN i_w[305]
    DIRECTION INPUT ;
    USE SIGNAL ;
    PORT
      LAYER M4 ;
        RECT  77.568 129.216 77.76 129.24 ;
    END
  END i_w[305]
  PIN i_w[306]
    DIRECTION INPUT ;
    USE SIGNAL ;
    PORT
      LAYER M4 ;
        RECT  77.568 129.6 77.76 129.624 ;
    END
  END i_w[306]
  PIN i_w[307]
    DIRECTION INPUT ;
    USE SIGNAL ;
    PORT
      LAYER M4 ;
        RECT  77.568 129.984 77.76 130.008 ;
    END
  END i_w[307]
  PIN i_w[308]
    DIRECTION INPUT ;
    USE SIGNAL ;
    PORT
      LAYER M4 ;
        RECT  77.568 130.368 77.76 130.392 ;
    END
  END i_w[308]
  PIN i_w[309]
    DIRECTION INPUT ;
    USE SIGNAL ;
    PORT
      LAYER M4 ;
        RECT  77.568 130.752 77.76 130.776 ;
    END
  END i_w[309]
  PIN i_w[30]
    DIRECTION INPUT ;
    USE SIGNAL ;
    PORT
      LAYER M4 ;
        RECT  77.568 23.616 77.76 23.64 ;
    END
  END i_w[30]
  PIN i_w[310]
    DIRECTION INPUT ;
    USE SIGNAL ;
    PORT
      LAYER M4 ;
        RECT  77.568 131.136 77.76 131.16 ;
    END
  END i_w[310]
  PIN i_w[311]
    DIRECTION INPUT ;
    USE SIGNAL ;
    PORT
      LAYER M4 ;
        RECT  77.568 131.52 77.76 131.544 ;
    END
  END i_w[311]
  PIN i_w[312]
    DIRECTION INPUT ;
    USE SIGNAL ;
    PORT
      LAYER M4 ;
        RECT  77.568 131.904 77.76 131.928 ;
    END
  END i_w[312]
  PIN i_w[313]
    DIRECTION INPUT ;
    USE SIGNAL ;
    PORT
      LAYER M4 ;
        RECT  77.568 132.288 77.76 132.312 ;
    END
  END i_w[313]
  PIN i_w[314]
    DIRECTION INPUT ;
    USE SIGNAL ;
    PORT
      LAYER M4 ;
        RECT  77.568 132.672 77.76 132.696 ;
    END
  END i_w[314]
  PIN i_w[315]
    DIRECTION INPUT ;
    USE SIGNAL ;
    PORT
      LAYER M4 ;
        RECT  77.568 133.056 77.76 133.08 ;
    END
  END i_w[315]
  PIN i_w[316]
    DIRECTION INPUT ;
    USE SIGNAL ;
    PORT
      LAYER M4 ;
        RECT  77.568 133.44 77.76 133.464 ;
    END
  END i_w[316]
  PIN i_w[317]
    DIRECTION INPUT ;
    USE SIGNAL ;
    PORT
      LAYER M4 ;
        RECT  77.568 133.824 77.76 133.848 ;
    END
  END i_w[317]
  PIN i_w[318]
    DIRECTION INPUT ;
    USE SIGNAL ;
    PORT
      LAYER M4 ;
        RECT  77.568 134.208 77.76 134.232 ;
    END
  END i_w[318]
  PIN i_w[319]
    DIRECTION INPUT ;
    USE SIGNAL ;
    PORT
      LAYER M4 ;
        RECT  77.568 134.592 77.76 134.616 ;
    END
  END i_w[319]
  PIN i_w[31]
    DIRECTION INPUT ;
    USE SIGNAL ;
    PORT
      LAYER M4 ;
        RECT  77.568 24 77.76 24.024 ;
    END
  END i_w[31]
  PIN i_w[320]
    DIRECTION INPUT ;
    USE SIGNAL ;
    PORT
      LAYER M4 ;
        RECT  77.568 134.976 77.76 135 ;
    END
  END i_w[320]
  PIN i_w[321]
    DIRECTION INPUT ;
    USE SIGNAL ;
    PORT
      LAYER M4 ;
        RECT  77.568 135.36 77.76 135.384 ;
    END
  END i_w[321]
  PIN i_w[322]
    DIRECTION INPUT ;
    USE SIGNAL ;
    PORT
      LAYER M4 ;
        RECT  77.568 135.744 77.76 135.768 ;
    END
  END i_w[322]
  PIN i_w[323]
    DIRECTION INPUT ;
    USE SIGNAL ;
    PORT
      LAYER M4 ;
        RECT  77.568 136.128 77.76 136.152 ;
    END
  END i_w[323]
  PIN i_w[324]
    DIRECTION INPUT ;
    USE SIGNAL ;
    PORT
      LAYER M4 ;
        RECT  77.568 136.512 77.76 136.536 ;
    END
  END i_w[324]
  PIN i_w[325]
    DIRECTION INPUT ;
    USE SIGNAL ;
    PORT
      LAYER M4 ;
        RECT  77.568 136.896 77.76 136.92 ;
    END
  END i_w[325]
  PIN i_w[326]
    DIRECTION INPUT ;
    USE SIGNAL ;
    PORT
      LAYER M4 ;
        RECT  77.568 137.28 77.76 137.304 ;
    END
  END i_w[326]
  PIN i_w[327]
    DIRECTION INPUT ;
    USE SIGNAL ;
    PORT
      LAYER M4 ;
        RECT  77.568 137.664 77.76 137.688 ;
    END
  END i_w[327]
  PIN i_w[328]
    DIRECTION INPUT ;
    USE SIGNAL ;
    PORT
      LAYER M4 ;
        RECT  77.568 138.048 77.76 138.072 ;
    END
  END i_w[328]
  PIN i_w[329]
    DIRECTION INPUT ;
    USE SIGNAL ;
    PORT
      LAYER M4 ;
        RECT  77.568 138.432 77.76 138.456 ;
    END
  END i_w[329]
  PIN i_w[32]
    DIRECTION INPUT ;
    USE SIGNAL ;
    PORT
      LAYER M4 ;
        RECT  77.568 24.384 77.76 24.408 ;
    END
  END i_w[32]
  PIN i_w[330]
    DIRECTION INPUT ;
    USE SIGNAL ;
    PORT
      LAYER M4 ;
        RECT  77.568 138.816 77.76 138.84 ;
    END
  END i_w[330]
  PIN i_w[331]
    DIRECTION INPUT ;
    USE SIGNAL ;
    PORT
      LAYER M4 ;
        RECT  77.568 139.2 77.76 139.224 ;
    END
  END i_w[331]
  PIN i_w[332]
    DIRECTION INPUT ;
    USE SIGNAL ;
    PORT
      LAYER M4 ;
        RECT  77.568 139.584 77.76 139.608 ;
    END
  END i_w[332]
  PIN i_w[333]
    DIRECTION INPUT ;
    USE SIGNAL ;
    PORT
      LAYER M4 ;
        RECT  77.568 139.968 77.76 139.992 ;
    END
  END i_w[333]
  PIN i_w[334]
    DIRECTION INPUT ;
    USE SIGNAL ;
    PORT
      LAYER M4 ;
        RECT  77.568 140.352 77.76 140.376 ;
    END
  END i_w[334]
  PIN i_w[335]
    DIRECTION INPUT ;
    USE SIGNAL ;
    PORT
      LAYER M4 ;
        RECT  77.568 140.736 77.76 140.76 ;
    END
  END i_w[335]
  PIN i_w[336]
    DIRECTION INPUT ;
    USE SIGNAL ;
    PORT
      LAYER M4 ;
        RECT  77.568 141.12 77.76 141.144 ;
    END
  END i_w[336]
  PIN i_w[337]
    DIRECTION INPUT ;
    USE SIGNAL ;
    PORT
      LAYER M4 ;
        RECT  77.568 141.504 77.76 141.528 ;
    END
  END i_w[337]
  PIN i_w[338]
    DIRECTION INPUT ;
    USE SIGNAL ;
    PORT
      LAYER M4 ;
        RECT  77.568 141.888 77.76 141.912 ;
    END
  END i_w[338]
  PIN i_w[339]
    DIRECTION INPUT ;
    USE SIGNAL ;
    PORT
      LAYER M4 ;
        RECT  77.568 142.272 77.76 142.296 ;
    END
  END i_w[339]
  PIN i_w[33]
    DIRECTION INPUT ;
    USE SIGNAL ;
    PORT
      LAYER M4 ;
        RECT  77.568 24.768 77.76 24.792 ;
    END
  END i_w[33]
  PIN i_w[340]
    DIRECTION INPUT ;
    USE SIGNAL ;
    PORT
      LAYER M4 ;
        RECT  77.568 142.656 77.76 142.68 ;
    END
  END i_w[340]
  PIN i_w[341]
    DIRECTION INPUT ;
    USE SIGNAL ;
    PORT
      LAYER M4 ;
        RECT  77.568 143.04 77.76 143.064 ;
    END
  END i_w[341]
  PIN i_w[342]
    DIRECTION INPUT ;
    USE SIGNAL ;
    PORT
      LAYER M4 ;
        RECT  77.568 143.424 77.76 143.448 ;
    END
  END i_w[342]
  PIN i_w[343]
    DIRECTION INPUT ;
    USE SIGNAL ;
    PORT
      LAYER M4 ;
        RECT  77.568 143.808 77.76 143.832 ;
    END
  END i_w[343]
  PIN i_w[344]
    DIRECTION INPUT ;
    USE SIGNAL ;
    PORT
      LAYER M4 ;
        RECT  77.568 144.192 77.76 144.216 ;
    END
  END i_w[344]
  PIN i_w[345]
    DIRECTION INPUT ;
    USE SIGNAL ;
    PORT
      LAYER M4 ;
        RECT  77.568 144.576 77.76 144.6 ;
    END
  END i_w[345]
  PIN i_w[346]
    DIRECTION INPUT ;
    USE SIGNAL ;
    PORT
      LAYER M4 ;
        RECT  77.568 144.96 77.76 144.984 ;
    END
  END i_w[346]
  PIN i_w[347]
    DIRECTION INPUT ;
    USE SIGNAL ;
    PORT
      LAYER M4 ;
        RECT  77.568 145.344 77.76 145.368 ;
    END
  END i_w[347]
  PIN i_w[348]
    DIRECTION INPUT ;
    USE SIGNAL ;
    PORT
      LAYER M4 ;
        RECT  77.568 145.728 77.76 145.752 ;
    END
  END i_w[348]
  PIN i_w[349]
    DIRECTION INPUT ;
    USE SIGNAL ;
    PORT
      LAYER M4 ;
        RECT  77.568 146.112 77.76 146.136 ;
    END
  END i_w[349]
  PIN i_w[34]
    DIRECTION INPUT ;
    USE SIGNAL ;
    PORT
      LAYER M4 ;
        RECT  77.568 25.152 77.76 25.176 ;
    END
  END i_w[34]
  PIN i_w[350]
    DIRECTION INPUT ;
    USE SIGNAL ;
    PORT
      LAYER M4 ;
        RECT  77.568 146.496 77.76 146.52 ;
    END
  END i_w[350]
  PIN i_w[351]
    DIRECTION INPUT ;
    USE SIGNAL ;
    PORT
      LAYER M4 ;
        RECT  77.568 146.88 77.76 146.904 ;
    END
  END i_w[351]
  PIN i_w[352]
    DIRECTION INPUT ;
    USE SIGNAL ;
    PORT
      LAYER M4 ;
        RECT  77.568 147.264 77.76 147.288 ;
    END
  END i_w[352]
  PIN i_w[353]
    DIRECTION INPUT ;
    USE SIGNAL ;
    PORT
      LAYER M4 ;
        RECT  77.568 147.648 77.76 147.672 ;
    END
  END i_w[353]
  PIN i_w[354]
    DIRECTION INPUT ;
    USE SIGNAL ;
    PORT
      LAYER M4 ;
        RECT  77.568 148.032 77.76 148.056 ;
    END
  END i_w[354]
  PIN i_w[355]
    DIRECTION INPUT ;
    USE SIGNAL ;
    PORT
      LAYER M4 ;
        RECT  77.568 148.416 77.76 148.44 ;
    END
  END i_w[355]
  PIN i_w[356]
    DIRECTION INPUT ;
    USE SIGNAL ;
    PORT
      LAYER M4 ;
        RECT  77.568 148.8 77.76 148.824 ;
    END
  END i_w[356]
  PIN i_w[357]
    DIRECTION INPUT ;
    USE SIGNAL ;
    PORT
      LAYER M4 ;
        RECT  77.568 149.184 77.76 149.208 ;
    END
  END i_w[357]
  PIN i_w[358]
    DIRECTION INPUT ;
    USE SIGNAL ;
    PORT
      LAYER M4 ;
        RECT  77.568 149.568 77.76 149.592 ;
    END
  END i_w[358]
  PIN i_w[359]
    DIRECTION INPUT ;
    USE SIGNAL ;
    PORT
      LAYER M4 ;
        RECT  77.568 149.952 77.76 149.976 ;
    END
  END i_w[359]
  PIN i_w[35]
    DIRECTION INPUT ;
    USE SIGNAL ;
    PORT
      LAYER M4 ;
        RECT  77.568 25.536 77.76 25.56 ;
    END
  END i_w[35]
  PIN i_w[360]
    DIRECTION INPUT ;
    USE SIGNAL ;
    PORT
      LAYER M4 ;
        RECT  77.568 150.336 77.76 150.36 ;
    END
  END i_w[360]
  PIN i_w[361]
    DIRECTION INPUT ;
    USE SIGNAL ;
    PORT
      LAYER M4 ;
        RECT  77.568 150.72 77.76 150.744 ;
    END
  END i_w[361]
  PIN i_w[362]
    DIRECTION INPUT ;
    USE SIGNAL ;
    PORT
      LAYER M4 ;
        RECT  77.568 151.104 77.76 151.128 ;
    END
  END i_w[362]
  PIN i_w[363]
    DIRECTION INPUT ;
    USE SIGNAL ;
    PORT
      LAYER M4 ;
        RECT  77.568 151.488 77.76 151.512 ;
    END
  END i_w[363]
  PIN i_w[364]
    DIRECTION INPUT ;
    USE SIGNAL ;
    PORT
      LAYER M4 ;
        RECT  77.568 151.872 77.76 151.896 ;
    END
  END i_w[364]
  PIN i_w[365]
    DIRECTION INPUT ;
    USE SIGNAL ;
    PORT
      LAYER M4 ;
        RECT  77.568 152.256 77.76 152.28 ;
    END
  END i_w[365]
  PIN i_w[366]
    DIRECTION INPUT ;
    USE SIGNAL ;
    PORT
      LAYER M4 ;
        RECT  77.568 152.64 77.76 152.664 ;
    END
  END i_w[366]
  PIN i_w[367]
    DIRECTION INPUT ;
    USE SIGNAL ;
    PORT
      LAYER M4 ;
        RECT  77.568 153.024 77.76 153.048 ;
    END
  END i_w[367]
  PIN i_w[368]
    DIRECTION INPUT ;
    USE SIGNAL ;
    PORT
      LAYER M4 ;
        RECT  77.568 153.408 77.76 153.432 ;
    END
  END i_w[368]
  PIN i_w[369]
    DIRECTION INPUT ;
    USE SIGNAL ;
    PORT
      LAYER M4 ;
        RECT  77.568 153.792 77.76 153.816 ;
    END
  END i_w[369]
  PIN i_w[36]
    DIRECTION INPUT ;
    USE SIGNAL ;
    PORT
      LAYER M4 ;
        RECT  77.568 25.92 77.76 25.944 ;
    END
  END i_w[36]
  PIN i_w[370]
    DIRECTION INPUT ;
    USE SIGNAL ;
    PORT
      LAYER M4 ;
        RECT  77.568 154.176 77.76 154.2 ;
    END
  END i_w[370]
  PIN i_w[371]
    DIRECTION INPUT ;
    USE SIGNAL ;
    PORT
      LAYER M4 ;
        RECT  77.568 154.56 77.76 154.584 ;
    END
  END i_w[371]
  PIN i_w[372]
    DIRECTION INPUT ;
    USE SIGNAL ;
    PORT
      LAYER M4 ;
        RECT  77.568 154.944 77.76 154.968 ;
    END
  END i_w[372]
  PIN i_w[373]
    DIRECTION INPUT ;
    USE SIGNAL ;
    PORT
      LAYER M4 ;
        RECT  77.568 155.328 77.76 155.352 ;
    END
  END i_w[373]
  PIN i_w[374]
    DIRECTION INPUT ;
    USE SIGNAL ;
    PORT
      LAYER M4 ;
        RECT  77.568 155.712 77.76 155.736 ;
    END
  END i_w[374]
  PIN i_w[375]
    DIRECTION INPUT ;
    USE SIGNAL ;
    PORT
      LAYER M4 ;
        RECT  77.568 156.096 77.76 156.12 ;
    END
  END i_w[375]
  PIN i_w[376]
    DIRECTION INPUT ;
    USE SIGNAL ;
    PORT
      LAYER M4 ;
        RECT  77.568 156.48 77.76 156.504 ;
    END
  END i_w[376]
  PIN i_w[377]
    DIRECTION INPUT ;
    USE SIGNAL ;
    PORT
      LAYER M4 ;
        RECT  77.568 156.864 77.76 156.888 ;
    END
  END i_w[377]
  PIN i_w[378]
    DIRECTION INPUT ;
    USE SIGNAL ;
    PORT
      LAYER M4 ;
        RECT  77.568 157.248 77.76 157.272 ;
    END
  END i_w[378]
  PIN i_w[379]
    DIRECTION INPUT ;
    USE SIGNAL ;
    PORT
      LAYER M4 ;
        RECT  77.568 157.632 77.76 157.656 ;
    END
  END i_w[379]
  PIN i_w[37]
    DIRECTION INPUT ;
    USE SIGNAL ;
    PORT
      LAYER M4 ;
        RECT  77.568 26.304 77.76 26.328 ;
    END
  END i_w[37]
  PIN i_w[380]
    DIRECTION INPUT ;
    USE SIGNAL ;
    PORT
      LAYER M4 ;
        RECT  77.568 158.016 77.76 158.04 ;
    END
  END i_w[380]
  PIN i_w[381]
    DIRECTION INPUT ;
    USE SIGNAL ;
    PORT
      LAYER M4 ;
        RECT  77.568 158.4 77.76 158.424 ;
    END
  END i_w[381]
  PIN i_w[382]
    DIRECTION INPUT ;
    USE SIGNAL ;
    PORT
      LAYER M4 ;
        RECT  77.568 158.784 77.76 158.808 ;
    END
  END i_w[382]
  PIN i_w[383]
    DIRECTION INPUT ;
    USE SIGNAL ;
    PORT
      LAYER M4 ;
        RECT  77.568 159.168 77.76 159.192 ;
    END
  END i_w[383]
  PIN i_w[384]
    DIRECTION INPUT ;
    USE SIGNAL ;
    PORT
      LAYER M4 ;
        RECT  77.568 159.552 77.76 159.576 ;
    END
  END i_w[384]
  PIN i_w[385]
    DIRECTION INPUT ;
    USE SIGNAL ;
    PORT
      LAYER M4 ;
        RECT  77.568 159.936 77.76 159.96 ;
    END
  END i_w[385]
  PIN i_w[386]
    DIRECTION INPUT ;
    USE SIGNAL ;
    PORT
      LAYER M4 ;
        RECT  77.568 160.32 77.76 160.344 ;
    END
  END i_w[386]
  PIN i_w[387]
    DIRECTION INPUT ;
    USE SIGNAL ;
    PORT
      LAYER M4 ;
        RECT  77.568 160.704 77.76 160.728 ;
    END
  END i_w[387]
  PIN i_w[388]
    DIRECTION INPUT ;
    USE SIGNAL ;
    PORT
      LAYER M4 ;
        RECT  77.568 161.088 77.76 161.112 ;
    END
  END i_w[388]
  PIN i_w[389]
    DIRECTION INPUT ;
    USE SIGNAL ;
    PORT
      LAYER M4 ;
        RECT  77.568 161.472 77.76 161.496 ;
    END
  END i_w[389]
  PIN i_w[38]
    DIRECTION INPUT ;
    USE SIGNAL ;
    PORT
      LAYER M4 ;
        RECT  77.568 26.688 77.76 26.712 ;
    END
  END i_w[38]
  PIN i_w[390]
    DIRECTION INPUT ;
    USE SIGNAL ;
    PORT
      LAYER M4 ;
        RECT  77.568 161.856 77.76 161.88 ;
    END
  END i_w[390]
  PIN i_w[391]
    DIRECTION INPUT ;
    USE SIGNAL ;
    PORT
      LAYER M4 ;
        RECT  77.568 162.24 77.76 162.264 ;
    END
  END i_w[391]
  PIN i_w[392]
    DIRECTION INPUT ;
    USE SIGNAL ;
    PORT
      LAYER M4 ;
        RECT  77.568 162.624 77.76 162.648 ;
    END
  END i_w[392]
  PIN i_w[393]
    DIRECTION INPUT ;
    USE SIGNAL ;
    PORT
      LAYER M4 ;
        RECT  77.568 163.008 77.76 163.032 ;
    END
  END i_w[393]
  PIN i_w[394]
    DIRECTION INPUT ;
    USE SIGNAL ;
    PORT
      LAYER M4 ;
        RECT  77.568 163.392 77.76 163.416 ;
    END
  END i_w[394]
  PIN i_w[395]
    DIRECTION INPUT ;
    USE SIGNAL ;
    PORT
      LAYER M4 ;
        RECT  77.568 163.776 77.76 163.8 ;
    END
  END i_w[395]
  PIN i_w[396]
    DIRECTION INPUT ;
    USE SIGNAL ;
    PORT
      LAYER M4 ;
        RECT  77.568 164.16 77.76 164.184 ;
    END
  END i_w[396]
  PIN i_w[397]
    DIRECTION INPUT ;
    USE SIGNAL ;
    PORT
      LAYER M4 ;
        RECT  77.568 164.544 77.76 164.568 ;
    END
  END i_w[397]
  PIN i_w[398]
    DIRECTION INPUT ;
    USE SIGNAL ;
    PORT
      LAYER M4 ;
        RECT  77.568 164.928 77.76 164.952 ;
    END
  END i_w[398]
  PIN i_w[399]
    DIRECTION INPUT ;
    USE SIGNAL ;
    PORT
      LAYER M4 ;
        RECT  77.568 165.312 77.76 165.336 ;
    END
  END i_w[399]
  PIN i_w[39]
    DIRECTION INPUT ;
    USE SIGNAL ;
    PORT
      LAYER M4 ;
        RECT  77.568 27.072 77.76 27.096 ;
    END
  END i_w[39]
  PIN i_w[3]
    DIRECTION INPUT ;
    USE SIGNAL ;
    PORT
      LAYER M4 ;
        RECT  77.568 13.248 77.76 13.272 ;
    END
  END i_w[3]
  PIN i_w[400]
    DIRECTION INPUT ;
    USE SIGNAL ;
    PORT
      LAYER M4 ;
        RECT  77.568 165.696 77.76 165.72 ;
    END
  END i_w[400]
  PIN i_w[401]
    DIRECTION INPUT ;
    USE SIGNAL ;
    PORT
      LAYER M4 ;
        RECT  77.568 166.08 77.76 166.104 ;
    END
  END i_w[401]
  PIN i_w[402]
    DIRECTION INPUT ;
    USE SIGNAL ;
    PORT
      LAYER M4 ;
        RECT  77.568 166.464 77.76 166.488 ;
    END
  END i_w[402]
  PIN i_w[403]
    DIRECTION INPUT ;
    USE SIGNAL ;
    PORT
      LAYER M4 ;
        RECT  77.568 166.848 77.76 166.872 ;
    END
  END i_w[403]
  PIN i_w[404]
    DIRECTION INPUT ;
    USE SIGNAL ;
    PORT
      LAYER M4 ;
        RECT  77.568 167.232 77.76 167.256 ;
    END
  END i_w[404]
  PIN i_w[405]
    DIRECTION INPUT ;
    USE SIGNAL ;
    PORT
      LAYER M4 ;
        RECT  77.568 167.616 77.76 167.64 ;
    END
  END i_w[405]
  PIN i_w[406]
    DIRECTION INPUT ;
    USE SIGNAL ;
    PORT
      LAYER M4 ;
        RECT  77.568 168 77.76 168.024 ;
    END
  END i_w[406]
  PIN i_w[407]
    DIRECTION INPUT ;
    USE SIGNAL ;
    PORT
      LAYER M4 ;
        RECT  77.568 168.384 77.76 168.408 ;
    END
  END i_w[407]
  PIN i_w[408]
    DIRECTION INPUT ;
    USE SIGNAL ;
    PORT
      LAYER M4 ;
        RECT  77.568 168.768 77.76 168.792 ;
    END
  END i_w[408]
  PIN i_w[409]
    DIRECTION INPUT ;
    USE SIGNAL ;
    PORT
      LAYER M4 ;
        RECT  77.568 169.152 77.76 169.176 ;
    END
  END i_w[409]
  PIN i_w[40]
    DIRECTION INPUT ;
    USE SIGNAL ;
    PORT
      LAYER M4 ;
        RECT  77.568 27.456 77.76 27.48 ;
    END
  END i_w[40]
  PIN i_w[410]
    DIRECTION INPUT ;
    USE SIGNAL ;
    PORT
      LAYER M4 ;
        RECT  77.568 169.536 77.76 169.56 ;
    END
  END i_w[410]
  PIN i_w[411]
    DIRECTION INPUT ;
    USE SIGNAL ;
    PORT
      LAYER M4 ;
        RECT  77.568 169.92 77.76 169.944 ;
    END
  END i_w[411]
  PIN i_w[412]
    DIRECTION INPUT ;
    USE SIGNAL ;
    PORT
      LAYER M4 ;
        RECT  77.568 170.304 77.76 170.328 ;
    END
  END i_w[412]
  PIN i_w[413]
    DIRECTION INPUT ;
    USE SIGNAL ;
    PORT
      LAYER M4 ;
        RECT  77.568 170.688 77.76 170.712 ;
    END
  END i_w[413]
  PIN i_w[414]
    DIRECTION INPUT ;
    USE SIGNAL ;
    PORT
      LAYER M4 ;
        RECT  77.568 171.072 77.76 171.096 ;
    END
  END i_w[414]
  PIN i_w[415]
    DIRECTION INPUT ;
    USE SIGNAL ;
    PORT
      LAYER M4 ;
        RECT  77.568 171.456 77.76 171.48 ;
    END
  END i_w[415]
  PIN i_w[416]
    DIRECTION INPUT ;
    USE SIGNAL ;
    PORT
      LAYER M4 ;
        RECT  77.568 171.84 77.76 171.864 ;
    END
  END i_w[416]
  PIN i_w[417]
    DIRECTION INPUT ;
    USE SIGNAL ;
    PORT
      LAYER M4 ;
        RECT  77.568 172.224 77.76 172.248 ;
    END
  END i_w[417]
  PIN i_w[418]
    DIRECTION INPUT ;
    USE SIGNAL ;
    PORT
      LAYER M4 ;
        RECT  77.568 172.608 77.76 172.632 ;
    END
  END i_w[418]
  PIN i_w[419]
    DIRECTION INPUT ;
    USE SIGNAL ;
    PORT
      LAYER M4 ;
        RECT  77.568 172.992 77.76 173.016 ;
    END
  END i_w[419]
  PIN i_w[41]
    DIRECTION INPUT ;
    USE SIGNAL ;
    PORT
      LAYER M4 ;
        RECT  77.568 27.84 77.76 27.864 ;
    END
  END i_w[41]
  PIN i_w[420]
    DIRECTION INPUT ;
    USE SIGNAL ;
    PORT
      LAYER M4 ;
        RECT  77.568 173.376 77.76 173.4 ;
    END
  END i_w[420]
  PIN i_w[421]
    DIRECTION INPUT ;
    USE SIGNAL ;
    PORT
      LAYER M4 ;
        RECT  77.568 173.76 77.76 173.784 ;
    END
  END i_w[421]
  PIN i_w[422]
    DIRECTION INPUT ;
    USE SIGNAL ;
    PORT
      LAYER M4 ;
        RECT  77.568 174.144 77.76 174.168 ;
    END
  END i_w[422]
  PIN i_w[423]
    DIRECTION INPUT ;
    USE SIGNAL ;
    PORT
      LAYER M4 ;
        RECT  77.568 174.528 77.76 174.552 ;
    END
  END i_w[423]
  PIN i_w[424]
    DIRECTION INPUT ;
    USE SIGNAL ;
    PORT
      LAYER M4 ;
        RECT  77.568 174.912 77.76 174.936 ;
    END
  END i_w[424]
  PIN i_w[425]
    DIRECTION INPUT ;
    USE SIGNAL ;
    PORT
      LAYER M4 ;
        RECT  77.568 175.296 77.76 175.32 ;
    END
  END i_w[425]
  PIN i_w[426]
    DIRECTION INPUT ;
    USE SIGNAL ;
    PORT
      LAYER M4 ;
        RECT  77.568 175.68 77.76 175.704 ;
    END
  END i_w[426]
  PIN i_w[427]
    DIRECTION INPUT ;
    USE SIGNAL ;
    PORT
      LAYER M4 ;
        RECT  77.568 176.064 77.76 176.088 ;
    END
  END i_w[427]
  PIN i_w[428]
    DIRECTION INPUT ;
    USE SIGNAL ;
    PORT
      LAYER M4 ;
        RECT  77.568 176.448 77.76 176.472 ;
    END
  END i_w[428]
  PIN i_w[429]
    DIRECTION INPUT ;
    USE SIGNAL ;
    PORT
      LAYER M4 ;
        RECT  77.568 176.832 77.76 176.856 ;
    END
  END i_w[429]
  PIN i_w[42]
    DIRECTION INPUT ;
    USE SIGNAL ;
    PORT
      LAYER M4 ;
        RECT  77.568 28.224 77.76 28.248 ;
    END
  END i_w[42]
  PIN i_w[430]
    DIRECTION INPUT ;
    USE SIGNAL ;
    PORT
      LAYER M4 ;
        RECT  77.568 177.216 77.76 177.24 ;
    END
  END i_w[430]
  PIN i_w[431]
    DIRECTION INPUT ;
    USE SIGNAL ;
    PORT
      LAYER M4 ;
        RECT  77.568 177.6 77.76 177.624 ;
    END
  END i_w[431]
  PIN i_w[432]
    DIRECTION INPUT ;
    USE SIGNAL ;
    PORT
      LAYER M4 ;
        RECT  77.568 177.984 77.76 178.008 ;
    END
  END i_w[432]
  PIN i_w[433]
    DIRECTION INPUT ;
    USE SIGNAL ;
    PORT
      LAYER M4 ;
        RECT  77.568 178.368 77.76 178.392 ;
    END
  END i_w[433]
  PIN i_w[434]
    DIRECTION INPUT ;
    USE SIGNAL ;
    PORT
      LAYER M4 ;
        RECT  77.568 178.752 77.76 178.776 ;
    END
  END i_w[434]
  PIN i_w[435]
    DIRECTION INPUT ;
    USE SIGNAL ;
    PORT
      LAYER M4 ;
        RECT  77.568 179.136 77.76 179.16 ;
    END
  END i_w[435]
  PIN i_w[436]
    DIRECTION INPUT ;
    USE SIGNAL ;
    PORT
      LAYER M4 ;
        RECT  77.568 179.52 77.76 179.544 ;
    END
  END i_w[436]
  PIN i_w[437]
    DIRECTION INPUT ;
    USE SIGNAL ;
    PORT
      LAYER M4 ;
        RECT  77.568 179.904 77.76 179.928 ;
    END
  END i_w[437]
  PIN i_w[438]
    DIRECTION INPUT ;
    USE SIGNAL ;
    PORT
      LAYER M4 ;
        RECT  77.568 180.288 77.76 180.312 ;
    END
  END i_w[438]
  PIN i_w[439]
    DIRECTION INPUT ;
    USE SIGNAL ;
    PORT
      LAYER M4 ;
        RECT  77.568 180.672 77.76 180.696 ;
    END
  END i_w[439]
  PIN i_w[43]
    DIRECTION INPUT ;
    USE SIGNAL ;
    PORT
      LAYER M4 ;
        RECT  77.568 28.608 77.76 28.632 ;
    END
  END i_w[43]
  PIN i_w[440]
    DIRECTION INPUT ;
    USE SIGNAL ;
    PORT
      LAYER M4 ;
        RECT  77.568 181.056 77.76 181.08 ;
    END
  END i_w[440]
  PIN i_w[441]
    DIRECTION INPUT ;
    USE SIGNAL ;
    PORT
      LAYER M4 ;
        RECT  77.568 181.44 77.76 181.464 ;
    END
  END i_w[441]
  PIN i_w[442]
    DIRECTION INPUT ;
    USE SIGNAL ;
    PORT
      LAYER M4 ;
        RECT  77.568 181.824 77.76 181.848 ;
    END
  END i_w[442]
  PIN i_w[443]
    DIRECTION INPUT ;
    USE SIGNAL ;
    PORT
      LAYER M4 ;
        RECT  77.568 182.208 77.76 182.232 ;
    END
  END i_w[443]
  PIN i_w[444]
    DIRECTION INPUT ;
    USE SIGNAL ;
    PORT
      LAYER M4 ;
        RECT  77.568 182.592 77.76 182.616 ;
    END
  END i_w[444]
  PIN i_w[445]
    DIRECTION INPUT ;
    USE SIGNAL ;
    PORT
      LAYER M4 ;
        RECT  77.568 182.976 77.76 183 ;
    END
  END i_w[445]
  PIN i_w[446]
    DIRECTION INPUT ;
    USE SIGNAL ;
    PORT
      LAYER M4 ;
        RECT  77.568 183.36 77.76 183.384 ;
    END
  END i_w[446]
  PIN i_w[447]
    DIRECTION INPUT ;
    USE SIGNAL ;
    PORT
      LAYER M4 ;
        RECT  77.568 183.744 77.76 183.768 ;
    END
  END i_w[447]
  PIN i_w[448]
    DIRECTION INPUT ;
    USE SIGNAL ;
    PORT
      LAYER M4 ;
        RECT  77.568 184.128 77.76 184.152 ;
    END
  END i_w[448]
  PIN i_w[449]
    DIRECTION INPUT ;
    USE SIGNAL ;
    PORT
      LAYER M4 ;
        RECT  77.568 184.512 77.76 184.536 ;
    END
  END i_w[449]
  PIN i_w[44]
    DIRECTION INPUT ;
    USE SIGNAL ;
    PORT
      LAYER M4 ;
        RECT  77.568 28.992 77.76 29.016 ;
    END
  END i_w[44]
  PIN i_w[450]
    DIRECTION INPUT ;
    USE SIGNAL ;
    PORT
      LAYER M4 ;
        RECT  77.568 184.896 77.76 184.92 ;
    END
  END i_w[450]
  PIN i_w[451]
    DIRECTION INPUT ;
    USE SIGNAL ;
    PORT
      LAYER M4 ;
        RECT  77.568 185.28 77.76 185.304 ;
    END
  END i_w[451]
  PIN i_w[452]
    DIRECTION INPUT ;
    USE SIGNAL ;
    PORT
      LAYER M4 ;
        RECT  77.568 185.664 77.76 185.688 ;
    END
  END i_w[452]
  PIN i_w[453]
    DIRECTION INPUT ;
    USE SIGNAL ;
    PORT
      LAYER M4 ;
        RECT  77.568 186.048 77.76 186.072 ;
    END
  END i_w[453]
  PIN i_w[454]
    DIRECTION INPUT ;
    USE SIGNAL ;
    PORT
      LAYER M4 ;
        RECT  77.568 186.432 77.76 186.456 ;
    END
  END i_w[454]
  PIN i_w[455]
    DIRECTION INPUT ;
    USE SIGNAL ;
    PORT
      LAYER M4 ;
        RECT  77.568 186.816 77.76 186.84 ;
    END
  END i_w[455]
  PIN i_w[456]
    DIRECTION INPUT ;
    USE SIGNAL ;
    PORT
      LAYER M4 ;
        RECT  77.568 187.2 77.76 187.224 ;
    END
  END i_w[456]
  PIN i_w[457]
    DIRECTION INPUT ;
    USE SIGNAL ;
    PORT
      LAYER M4 ;
        RECT  77.568 187.584 77.76 187.608 ;
    END
  END i_w[457]
  PIN i_w[458]
    DIRECTION INPUT ;
    USE SIGNAL ;
    PORT
      LAYER M4 ;
        RECT  77.568 187.968 77.76 187.992 ;
    END
  END i_w[458]
  PIN i_w[459]
    DIRECTION INPUT ;
    USE SIGNAL ;
    PORT
      LAYER M4 ;
        RECT  77.568 188.352 77.76 188.376 ;
    END
  END i_w[459]
  PIN i_w[45]
    DIRECTION INPUT ;
    USE SIGNAL ;
    PORT
      LAYER M4 ;
        RECT  77.568 29.376 77.76 29.4 ;
    END
  END i_w[45]
  PIN i_w[460]
    DIRECTION INPUT ;
    USE SIGNAL ;
    PORT
      LAYER M4 ;
        RECT  77.568 188.736 77.76 188.76 ;
    END
  END i_w[460]
  PIN i_w[461]
    DIRECTION INPUT ;
    USE SIGNAL ;
    PORT
      LAYER M4 ;
        RECT  77.568 189.12 77.76 189.144 ;
    END
  END i_w[461]
  PIN i_w[462]
    DIRECTION INPUT ;
    USE SIGNAL ;
    PORT
      LAYER M4 ;
        RECT  77.568 189.504 77.76 189.528 ;
    END
  END i_w[462]
  PIN i_w[463]
    DIRECTION INPUT ;
    USE SIGNAL ;
    PORT
      LAYER M4 ;
        RECT  77.568 189.888 77.76 189.912 ;
    END
  END i_w[463]
  PIN i_w[464]
    DIRECTION INPUT ;
    USE SIGNAL ;
    PORT
      LAYER M4 ;
        RECT  77.568 190.272 77.76 190.296 ;
    END
  END i_w[464]
  PIN i_w[465]
    DIRECTION INPUT ;
    USE SIGNAL ;
    PORT
      LAYER M4 ;
        RECT  77.568 190.656 77.76 190.68 ;
    END
  END i_w[465]
  PIN i_w[466]
    DIRECTION INPUT ;
    USE SIGNAL ;
    PORT
      LAYER M4 ;
        RECT  77.568 191.04 77.76 191.064 ;
    END
  END i_w[466]
  PIN i_w[467]
    DIRECTION INPUT ;
    USE SIGNAL ;
    PORT
      LAYER M4 ;
        RECT  77.568 191.424 77.76 191.448 ;
    END
  END i_w[467]
  PIN i_w[468]
    DIRECTION INPUT ;
    USE SIGNAL ;
    PORT
      LAYER M4 ;
        RECT  77.568 191.808 77.76 191.832 ;
    END
  END i_w[468]
  PIN i_w[469]
    DIRECTION INPUT ;
    USE SIGNAL ;
    PORT
      LAYER M4 ;
        RECT  77.568 192.192 77.76 192.216 ;
    END
  END i_w[469]
  PIN i_w[46]
    DIRECTION INPUT ;
    USE SIGNAL ;
    PORT
      LAYER M4 ;
        RECT  77.568 29.76 77.76 29.784 ;
    END
  END i_w[46]
  PIN i_w[470]
    DIRECTION INPUT ;
    USE SIGNAL ;
    PORT
      LAYER M4 ;
        RECT  77.568 192.576 77.76 192.6 ;
    END
  END i_w[470]
  PIN i_w[471]
    DIRECTION INPUT ;
    USE SIGNAL ;
    PORT
      LAYER M4 ;
        RECT  77.568 192.96 77.76 192.984 ;
    END
  END i_w[471]
  PIN i_w[472]
    DIRECTION INPUT ;
    USE SIGNAL ;
    PORT
      LAYER M4 ;
        RECT  77.568 193.344 77.76 193.368 ;
    END
  END i_w[472]
  PIN i_w[473]
    DIRECTION INPUT ;
    USE SIGNAL ;
    PORT
      LAYER M4 ;
        RECT  77.568 193.728 77.76 193.752 ;
    END
  END i_w[473]
  PIN i_w[474]
    DIRECTION INPUT ;
    USE SIGNAL ;
    PORT
      LAYER M4 ;
        RECT  77.568 194.112 77.76 194.136 ;
    END
  END i_w[474]
  PIN i_w[475]
    DIRECTION INPUT ;
    USE SIGNAL ;
    PORT
      LAYER M4 ;
        RECT  77.568 194.496 77.76 194.52 ;
    END
  END i_w[475]
  PIN i_w[476]
    DIRECTION INPUT ;
    USE SIGNAL ;
    PORT
      LAYER M4 ;
        RECT  77.568 194.88 77.76 194.904 ;
    END
  END i_w[476]
  PIN i_w[477]
    DIRECTION INPUT ;
    USE SIGNAL ;
    PORT
      LAYER M4 ;
        RECT  77.568 195.264 77.76 195.288 ;
    END
  END i_w[477]
  PIN i_w[478]
    DIRECTION INPUT ;
    USE SIGNAL ;
    PORT
      LAYER M4 ;
        RECT  77.568 195.648 77.76 195.672 ;
    END
  END i_w[478]
  PIN i_w[479]
    DIRECTION INPUT ;
    USE SIGNAL ;
    PORT
      LAYER M4 ;
        RECT  77.568 196.032 77.76 196.056 ;
    END
  END i_w[479]
  PIN i_w[47]
    DIRECTION INPUT ;
    USE SIGNAL ;
    PORT
      LAYER M4 ;
        RECT  77.568 30.144 77.76 30.168 ;
    END
  END i_w[47]
  PIN i_w[480]
    DIRECTION INPUT ;
    USE SIGNAL ;
    PORT
      LAYER M4 ;
        RECT  77.568 196.416 77.76 196.44 ;
    END
  END i_w[480]
  PIN i_w[481]
    DIRECTION INPUT ;
    USE SIGNAL ;
    PORT
      LAYER M4 ;
        RECT  77.568 196.8 77.76 196.824 ;
    END
  END i_w[481]
  PIN i_w[482]
    DIRECTION INPUT ;
    USE SIGNAL ;
    PORT
      LAYER M4 ;
        RECT  77.568 197.184 77.76 197.208 ;
    END
  END i_w[482]
  PIN i_w[483]
    DIRECTION INPUT ;
    USE SIGNAL ;
    PORT
      LAYER M4 ;
        RECT  77.568 197.568 77.76 197.592 ;
    END
  END i_w[483]
  PIN i_w[484]
    DIRECTION INPUT ;
    USE SIGNAL ;
    PORT
      LAYER M4 ;
        RECT  77.568 197.952 77.76 197.976 ;
    END
  END i_w[484]
  PIN i_w[485]
    DIRECTION INPUT ;
    USE SIGNAL ;
    PORT
      LAYER M4 ;
        RECT  77.568 198.336 77.76 198.36 ;
    END
  END i_w[485]
  PIN i_w[486]
    DIRECTION INPUT ;
    USE SIGNAL ;
    PORT
      LAYER M4 ;
        RECT  77.568 198.72 77.76 198.744 ;
    END
  END i_w[486]
  PIN i_w[487]
    DIRECTION INPUT ;
    USE SIGNAL ;
    PORT
      LAYER M4 ;
        RECT  77.568 199.104 77.76 199.128 ;
    END
  END i_w[487]
  PIN i_w[488]
    DIRECTION INPUT ;
    USE SIGNAL ;
    PORT
      LAYER M4 ;
        RECT  77.568 199.488 77.76 199.512 ;
    END
  END i_w[488]
  PIN i_w[489]
    DIRECTION INPUT ;
    USE SIGNAL ;
    PORT
      LAYER M4 ;
        RECT  77.568 199.872 77.76 199.896 ;
    END
  END i_w[489]
  PIN i_w[48]
    DIRECTION INPUT ;
    USE SIGNAL ;
    PORT
      LAYER M4 ;
        RECT  77.568 30.528 77.76 30.552 ;
    END
  END i_w[48]
  PIN i_w[490]
    DIRECTION INPUT ;
    USE SIGNAL ;
    PORT
      LAYER M4 ;
        RECT  77.568 200.256 77.76 200.28 ;
    END
  END i_w[490]
  PIN i_w[491]
    DIRECTION INPUT ;
    USE SIGNAL ;
    PORT
      LAYER M4 ;
        RECT  77.568 200.64 77.76 200.664 ;
    END
  END i_w[491]
  PIN i_w[492]
    DIRECTION INPUT ;
    USE SIGNAL ;
    PORT
      LAYER M4 ;
        RECT  77.568 201.024 77.76 201.048 ;
    END
  END i_w[492]
  PIN i_w[493]
    DIRECTION INPUT ;
    USE SIGNAL ;
    PORT
      LAYER M4 ;
        RECT  77.568 201.408 77.76 201.432 ;
    END
  END i_w[493]
  PIN i_w[494]
    DIRECTION INPUT ;
    USE SIGNAL ;
    PORT
      LAYER M4 ;
        RECT  77.568 201.792 77.76 201.816 ;
    END
  END i_w[494]
  PIN i_w[495]
    DIRECTION INPUT ;
    USE SIGNAL ;
    PORT
      LAYER M4 ;
        RECT  77.568 202.176 77.76 202.2 ;
    END
  END i_w[495]
  PIN i_w[496]
    DIRECTION INPUT ;
    USE SIGNAL ;
    PORT
      LAYER M4 ;
        RECT  77.568 202.56 77.76 202.584 ;
    END
  END i_w[496]
  PIN i_w[497]
    DIRECTION INPUT ;
    USE SIGNAL ;
    PORT
      LAYER M4 ;
        RECT  77.568 202.944 77.76 202.968 ;
    END
  END i_w[497]
  PIN i_w[498]
    DIRECTION INPUT ;
    USE SIGNAL ;
    PORT
      LAYER M4 ;
        RECT  77.568 203.328 77.76 203.352 ;
    END
  END i_w[498]
  PIN i_w[499]
    DIRECTION INPUT ;
    USE SIGNAL ;
    PORT
      LAYER M4 ;
        RECT  77.568 203.712 77.76 203.736 ;
    END
  END i_w[499]
  PIN i_w[49]
    DIRECTION INPUT ;
    USE SIGNAL ;
    PORT
      LAYER M4 ;
        RECT  77.568 30.912 77.76 30.936 ;
    END
  END i_w[49]
  PIN i_w[4]
    DIRECTION INPUT ;
    USE SIGNAL ;
    PORT
      LAYER M4 ;
        RECT  77.568 13.632 77.76 13.656 ;
    END
  END i_w[4]
  PIN i_w[500]
    DIRECTION INPUT ;
    USE SIGNAL ;
    PORT
      LAYER M4 ;
        RECT  77.568 204.096 77.76 204.12 ;
    END
  END i_w[500]
  PIN i_w[501]
    DIRECTION INPUT ;
    USE SIGNAL ;
    PORT
      LAYER M4 ;
        RECT  77.568 204.48 77.76 204.504 ;
    END
  END i_w[501]
  PIN i_w[502]
    DIRECTION INPUT ;
    USE SIGNAL ;
    PORT
      LAYER M4 ;
        RECT  77.568 204.864 77.76 204.888 ;
    END
  END i_w[502]
  PIN i_w[503]
    DIRECTION INPUT ;
    USE SIGNAL ;
    PORT
      LAYER M4 ;
        RECT  77.568 205.248 77.76 205.272 ;
    END
  END i_w[503]
  PIN i_w[504]
    DIRECTION INPUT ;
    USE SIGNAL ;
    PORT
      LAYER M4 ;
        RECT  77.568 205.632 77.76 205.656 ;
    END
  END i_w[504]
  PIN i_w[505]
    DIRECTION INPUT ;
    USE SIGNAL ;
    PORT
      LAYER M4 ;
        RECT  77.568 206.016 77.76 206.04 ;
    END
  END i_w[505]
  PIN i_w[506]
    DIRECTION INPUT ;
    USE SIGNAL ;
    PORT
      LAYER M4 ;
        RECT  77.568 206.4 77.76 206.424 ;
    END
  END i_w[506]
  PIN i_w[507]
    DIRECTION INPUT ;
    USE SIGNAL ;
    PORT
      LAYER M4 ;
        RECT  77.568 206.784 77.76 206.808 ;
    END
  END i_w[507]
  PIN i_w[508]
    DIRECTION INPUT ;
    USE SIGNAL ;
    PORT
      LAYER M4 ;
        RECT  77.568 207.168 77.76 207.192 ;
    END
  END i_w[508]
  PIN i_w[509]
    DIRECTION INPUT ;
    USE SIGNAL ;
    PORT
      LAYER M4 ;
        RECT  77.568 207.552 77.76 207.576 ;
    END
  END i_w[509]
  PIN i_w[50]
    DIRECTION INPUT ;
    USE SIGNAL ;
    PORT
      LAYER M4 ;
        RECT  77.568 31.296 77.76 31.32 ;
    END
  END i_w[50]
  PIN i_w[510]
    DIRECTION INPUT ;
    USE SIGNAL ;
    PORT
      LAYER M4 ;
        RECT  77.568 207.936 77.76 207.96 ;
    END
  END i_w[510]
  PIN i_w[511]
    DIRECTION INPUT ;
    USE SIGNAL ;
    PORT
      LAYER M4 ;
        RECT  77.568 208.32 77.76 208.344 ;
    END
  END i_w[511]
  PIN i_w[512]
    DIRECTION INPUT ;
    USE SIGNAL ;
    PORT
      LAYER M4 ;
        RECT  77.568 208.704 77.76 208.728 ;
    END
  END i_w[512]
  PIN i_w[513]
    DIRECTION INPUT ;
    USE SIGNAL ;
    PORT
      LAYER M4 ;
        RECT  77.568 209.088 77.76 209.112 ;
    END
  END i_w[513]
  PIN i_w[514]
    DIRECTION INPUT ;
    USE SIGNAL ;
    PORT
      LAYER M4 ;
        RECT  77.568 209.472 77.76 209.496 ;
    END
  END i_w[514]
  PIN i_w[515]
    DIRECTION INPUT ;
    USE SIGNAL ;
    PORT
      LAYER M4 ;
        RECT  77.568 209.856 77.76 209.88 ;
    END
  END i_w[515]
  PIN i_w[516]
    DIRECTION INPUT ;
    USE SIGNAL ;
    PORT
      LAYER M4 ;
        RECT  77.568 210.24 77.76 210.264 ;
    END
  END i_w[516]
  PIN i_w[517]
    DIRECTION INPUT ;
    USE SIGNAL ;
    PORT
      LAYER M4 ;
        RECT  77.568 210.624 77.76 210.648 ;
    END
  END i_w[517]
  PIN i_w[518]
    DIRECTION INPUT ;
    USE SIGNAL ;
    PORT
      LAYER M4 ;
        RECT  77.568 211.008 77.76 211.032 ;
    END
  END i_w[518]
  PIN i_w[519]
    DIRECTION INPUT ;
    USE SIGNAL ;
    PORT
      LAYER M4 ;
        RECT  77.568 211.392 77.76 211.416 ;
    END
  END i_w[519]
  PIN i_w[51]
    DIRECTION INPUT ;
    USE SIGNAL ;
    PORT
      LAYER M4 ;
        RECT  77.568 31.68 77.76 31.704 ;
    END
  END i_w[51]
  PIN i_w[520]
    DIRECTION INPUT ;
    USE SIGNAL ;
    PORT
      LAYER M4 ;
        RECT  77.568 211.776 77.76 211.8 ;
    END
  END i_w[520]
  PIN i_w[521]
    DIRECTION INPUT ;
    USE SIGNAL ;
    PORT
      LAYER M4 ;
        RECT  77.568 212.16 77.76 212.184 ;
    END
  END i_w[521]
  PIN i_w[522]
    DIRECTION INPUT ;
    USE SIGNAL ;
    PORT
      LAYER M4 ;
        RECT  77.568 212.544 77.76 212.568 ;
    END
  END i_w[522]
  PIN i_w[523]
    DIRECTION INPUT ;
    USE SIGNAL ;
    PORT
      LAYER M4 ;
        RECT  77.568 212.928 77.76 212.952 ;
    END
  END i_w[523]
  PIN i_w[524]
    DIRECTION INPUT ;
    USE SIGNAL ;
    PORT
      LAYER M4 ;
        RECT  77.568 213.312 77.76 213.336 ;
    END
  END i_w[524]
  PIN i_w[525]
    DIRECTION INPUT ;
    USE SIGNAL ;
    PORT
      LAYER M4 ;
        RECT  77.568 213.696 77.76 213.72 ;
    END
  END i_w[525]
  PIN i_w[526]
    DIRECTION INPUT ;
    USE SIGNAL ;
    PORT
      LAYER M4 ;
        RECT  77.568 214.08 77.76 214.104 ;
    END
  END i_w[526]
  PIN i_w[527]
    DIRECTION INPUT ;
    USE SIGNAL ;
    PORT
      LAYER M4 ;
        RECT  77.568 214.464 77.76 214.488 ;
    END
  END i_w[527]
  PIN i_w[528]
    DIRECTION INPUT ;
    USE SIGNAL ;
    PORT
      LAYER M4 ;
        RECT  77.568 214.848 77.76 214.872 ;
    END
  END i_w[528]
  PIN i_w[529]
    DIRECTION INPUT ;
    USE SIGNAL ;
    PORT
      LAYER M4 ;
        RECT  77.568 215.232 77.76 215.256 ;
    END
  END i_w[529]
  PIN i_w[52]
    DIRECTION INPUT ;
    USE SIGNAL ;
    PORT
      LAYER M4 ;
        RECT  77.568 32.064 77.76 32.088 ;
    END
  END i_w[52]
  PIN i_w[530]
    DIRECTION INPUT ;
    USE SIGNAL ;
    PORT
      LAYER M4 ;
        RECT  77.568 215.616 77.76 215.64 ;
    END
  END i_w[530]
  PIN i_w[531]
    DIRECTION INPUT ;
    USE SIGNAL ;
    PORT
      LAYER M4 ;
        RECT  77.568 216 77.76 216.024 ;
    END
  END i_w[531]
  PIN i_w[53]
    DIRECTION INPUT ;
    USE SIGNAL ;
    PORT
      LAYER M4 ;
        RECT  77.568 32.448 77.76 32.472 ;
    END
  END i_w[53]
  PIN i_w[54]
    DIRECTION INPUT ;
    USE SIGNAL ;
    PORT
      LAYER M4 ;
        RECT  77.568 32.832 77.76 32.856 ;
    END
  END i_w[54]
  PIN i_w[55]
    DIRECTION INPUT ;
    USE SIGNAL ;
    PORT
      LAYER M4 ;
        RECT  77.568 33.216 77.76 33.24 ;
    END
  END i_w[55]
  PIN i_w[56]
    DIRECTION INPUT ;
    USE SIGNAL ;
    PORT
      LAYER M4 ;
        RECT  77.568 33.6 77.76 33.624 ;
    END
  END i_w[56]
  PIN i_w[57]
    DIRECTION INPUT ;
    USE SIGNAL ;
    PORT
      LAYER M4 ;
        RECT  77.568 33.984 77.76 34.008 ;
    END
  END i_w[57]
  PIN i_w[58]
    DIRECTION INPUT ;
    USE SIGNAL ;
    PORT
      LAYER M4 ;
        RECT  77.568 34.368 77.76 34.392 ;
    END
  END i_w[58]
  PIN i_w[59]
    DIRECTION INPUT ;
    USE SIGNAL ;
    PORT
      LAYER M4 ;
        RECT  77.568 34.752 77.76 34.776 ;
    END
  END i_w[59]
  PIN i_w[5]
    DIRECTION INPUT ;
    USE SIGNAL ;
    PORT
      LAYER M4 ;
        RECT  77.568 14.016 77.76 14.04 ;
    END
  END i_w[5]
  PIN i_w[60]
    DIRECTION INPUT ;
    USE SIGNAL ;
    PORT
      LAYER M4 ;
        RECT  77.568 35.136 77.76 35.16 ;
    END
  END i_w[60]
  PIN i_w[61]
    DIRECTION INPUT ;
    USE SIGNAL ;
    PORT
      LAYER M4 ;
        RECT  77.568 35.52 77.76 35.544 ;
    END
  END i_w[61]
  PIN i_w[62]
    DIRECTION INPUT ;
    USE SIGNAL ;
    PORT
      LAYER M4 ;
        RECT  77.568 35.904 77.76 35.928 ;
    END
  END i_w[62]
  PIN i_w[63]
    DIRECTION INPUT ;
    USE SIGNAL ;
    PORT
      LAYER M4 ;
        RECT  77.568 36.288 77.76 36.312 ;
    END
  END i_w[63]
  PIN i_w[64]
    DIRECTION INPUT ;
    USE SIGNAL ;
    PORT
      LAYER M4 ;
        RECT  77.568 36.672 77.76 36.696 ;
    END
  END i_w[64]
  PIN i_w[65]
    DIRECTION INPUT ;
    USE SIGNAL ;
    PORT
      LAYER M4 ;
        RECT  77.568 37.056 77.76 37.08 ;
    END
  END i_w[65]
  PIN i_w[66]
    DIRECTION INPUT ;
    USE SIGNAL ;
    PORT
      LAYER M4 ;
        RECT  77.568 37.44 77.76 37.464 ;
    END
  END i_w[66]
  PIN i_w[67]
    DIRECTION INPUT ;
    USE SIGNAL ;
    PORT
      LAYER M4 ;
        RECT  77.568 37.824 77.76 37.848 ;
    END
  END i_w[67]
  PIN i_w[68]
    DIRECTION INPUT ;
    USE SIGNAL ;
    PORT
      LAYER M4 ;
        RECT  77.568 38.208 77.76 38.232 ;
    END
  END i_w[68]
  PIN i_w[69]
    DIRECTION INPUT ;
    USE SIGNAL ;
    PORT
      LAYER M4 ;
        RECT  77.568 38.592 77.76 38.616 ;
    END
  END i_w[69]
  PIN i_w[6]
    DIRECTION INPUT ;
    USE SIGNAL ;
    PORT
      LAYER M4 ;
        RECT  77.568 14.4 77.76 14.424 ;
    END
  END i_w[6]
  PIN i_w[70]
    DIRECTION INPUT ;
    USE SIGNAL ;
    PORT
      LAYER M4 ;
        RECT  77.568 38.976 77.76 39 ;
    END
  END i_w[70]
  PIN i_w[71]
    DIRECTION INPUT ;
    USE SIGNAL ;
    PORT
      LAYER M4 ;
        RECT  77.568 39.36 77.76 39.384 ;
    END
  END i_w[71]
  PIN i_w[72]
    DIRECTION INPUT ;
    USE SIGNAL ;
    PORT
      LAYER M4 ;
        RECT  77.568 39.744 77.76 39.768 ;
    END
  END i_w[72]
  PIN i_w[73]
    DIRECTION INPUT ;
    USE SIGNAL ;
    PORT
      LAYER M4 ;
        RECT  77.568 40.128 77.76 40.152 ;
    END
  END i_w[73]
  PIN i_w[74]
    DIRECTION INPUT ;
    USE SIGNAL ;
    PORT
      LAYER M4 ;
        RECT  77.568 40.512 77.76 40.536 ;
    END
  END i_w[74]
  PIN i_w[75]
    DIRECTION INPUT ;
    USE SIGNAL ;
    PORT
      LAYER M4 ;
        RECT  77.568 40.896 77.76 40.92 ;
    END
  END i_w[75]
  PIN i_w[76]
    DIRECTION INPUT ;
    USE SIGNAL ;
    PORT
      LAYER M4 ;
        RECT  77.568 41.28 77.76 41.304 ;
    END
  END i_w[76]
  PIN i_w[77]
    DIRECTION INPUT ;
    USE SIGNAL ;
    PORT
      LAYER M4 ;
        RECT  77.568 41.664 77.76 41.688 ;
    END
  END i_w[77]
  PIN i_w[78]
    DIRECTION INPUT ;
    USE SIGNAL ;
    PORT
      LAYER M4 ;
        RECT  77.568 42.048 77.76 42.072 ;
    END
  END i_w[78]
  PIN i_w[79]
    DIRECTION INPUT ;
    USE SIGNAL ;
    PORT
      LAYER M4 ;
        RECT  77.568 42.432 77.76 42.456 ;
    END
  END i_w[79]
  PIN i_w[7]
    DIRECTION INPUT ;
    USE SIGNAL ;
    PORT
      LAYER M4 ;
        RECT  77.568 14.784 77.76 14.808 ;
    END
  END i_w[7]
  PIN i_w[80]
    DIRECTION INPUT ;
    USE SIGNAL ;
    PORT
      LAYER M4 ;
        RECT  77.568 42.816 77.76 42.84 ;
    END
  END i_w[80]
  PIN i_w[81]
    DIRECTION INPUT ;
    USE SIGNAL ;
    PORT
      LAYER M4 ;
        RECT  77.568 43.2 77.76 43.224 ;
    END
  END i_w[81]
  PIN i_w[82]
    DIRECTION INPUT ;
    USE SIGNAL ;
    PORT
      LAYER M4 ;
        RECT  77.568 43.584 77.76 43.608 ;
    END
  END i_w[82]
  PIN i_w[83]
    DIRECTION INPUT ;
    USE SIGNAL ;
    PORT
      LAYER M4 ;
        RECT  77.568 43.968 77.76 43.992 ;
    END
  END i_w[83]
  PIN i_w[84]
    DIRECTION INPUT ;
    USE SIGNAL ;
    PORT
      LAYER M4 ;
        RECT  77.568 44.352 77.76 44.376 ;
    END
  END i_w[84]
  PIN i_w[85]
    DIRECTION INPUT ;
    USE SIGNAL ;
    PORT
      LAYER M4 ;
        RECT  77.568 44.736 77.76 44.76 ;
    END
  END i_w[85]
  PIN i_w[86]
    DIRECTION INPUT ;
    USE SIGNAL ;
    PORT
      LAYER M4 ;
        RECT  77.568 45.12 77.76 45.144 ;
    END
  END i_w[86]
  PIN i_w[87]
    DIRECTION INPUT ;
    USE SIGNAL ;
    PORT
      LAYER M4 ;
        RECT  77.568 45.504 77.76 45.528 ;
    END
  END i_w[87]
  PIN i_w[88]
    DIRECTION INPUT ;
    USE SIGNAL ;
    PORT
      LAYER M4 ;
        RECT  77.568 45.888 77.76 45.912 ;
    END
  END i_w[88]
  PIN i_w[89]
    DIRECTION INPUT ;
    USE SIGNAL ;
    PORT
      LAYER M4 ;
        RECT  77.568 46.272 77.76 46.296 ;
    END
  END i_w[89]
  PIN i_w[8]
    DIRECTION INPUT ;
    USE SIGNAL ;
    PORT
      LAYER M4 ;
        RECT  77.568 15.168 77.76 15.192 ;
    END
  END i_w[8]
  PIN i_w[90]
    DIRECTION INPUT ;
    USE SIGNAL ;
    PORT
      LAYER M4 ;
        RECT  77.568 46.656 77.76 46.68 ;
    END
  END i_w[90]
  PIN i_w[91]
    DIRECTION INPUT ;
    USE SIGNAL ;
    PORT
      LAYER M4 ;
        RECT  77.568 47.04 77.76 47.064 ;
    END
  END i_w[91]
  PIN i_w[92]
    DIRECTION INPUT ;
    USE SIGNAL ;
    PORT
      LAYER M4 ;
        RECT  77.568 47.424 77.76 47.448 ;
    END
  END i_w[92]
  PIN i_w[93]
    DIRECTION INPUT ;
    USE SIGNAL ;
    PORT
      LAYER M4 ;
        RECT  77.568 47.808 77.76 47.832 ;
    END
  END i_w[93]
  PIN i_w[94]
    DIRECTION INPUT ;
    USE SIGNAL ;
    PORT
      LAYER M4 ;
        RECT  77.568 48.192 77.76 48.216 ;
    END
  END i_w[94]
  PIN i_w[95]
    DIRECTION INPUT ;
    USE SIGNAL ;
    PORT
      LAYER M4 ;
        RECT  77.568 48.576 77.76 48.6 ;
    END
  END i_w[95]
  PIN i_w[96]
    DIRECTION INPUT ;
    USE SIGNAL ;
    PORT
      LAYER M4 ;
        RECT  77.568 48.96 77.76 48.984 ;
    END
  END i_w[96]
  PIN i_w[97]
    DIRECTION INPUT ;
    USE SIGNAL ;
    PORT
      LAYER M4 ;
        RECT  77.568 49.344 77.76 49.368 ;
    END
  END i_w[97]
  PIN i_w[98]
    DIRECTION INPUT ;
    USE SIGNAL ;
    PORT
      LAYER M4 ;
        RECT  77.568 49.728 77.76 49.752 ;
    END
  END i_w[98]
  PIN i_w[99]
    DIRECTION INPUT ;
    USE SIGNAL ;
    PORT
      LAYER M4 ;
        RECT  77.568 50.112 77.76 50.136 ;
    END
  END i_w[99]
  PIN i_w[9]
    DIRECTION INPUT ;
    USE SIGNAL ;
    PORT
      LAYER M4 ;
        RECT  77.568 15.552 77.76 15.576 ;
    END
  END i_w[9]
  PIN i_x[0]
    DIRECTION INPUT ;
    USE SIGNAL ;
    PORT
      LAYER M4 ;
        RECT  77.568 12.288 77.76 12.312 ;
    END
  END i_x[0]
  PIN i_x[100]
    DIRECTION INPUT ;
    USE SIGNAL ;
    PORT
      LAYER M4 ;
        RECT  77.568 50.688 77.76 50.712 ;
    END
  END i_x[100]
  PIN i_x[101]
    DIRECTION INPUT ;
    USE SIGNAL ;
    PORT
      LAYER M4 ;
        RECT  77.568 51.072 77.76 51.096 ;
    END
  END i_x[101]
  PIN i_x[102]
    DIRECTION INPUT ;
    USE SIGNAL ;
    PORT
      LAYER M4 ;
        RECT  77.568 51.456 77.76 51.48 ;
    END
  END i_x[102]
  PIN i_x[103]
    DIRECTION INPUT ;
    USE SIGNAL ;
    PORT
      LAYER M4 ;
        RECT  77.568 51.84 77.76 51.864 ;
    END
  END i_x[103]
  PIN i_x[104]
    DIRECTION INPUT ;
    USE SIGNAL ;
    PORT
      LAYER M4 ;
        RECT  77.568 52.224 77.76 52.248 ;
    END
  END i_x[104]
  PIN i_x[105]
    DIRECTION INPUT ;
    USE SIGNAL ;
    PORT
      LAYER M4 ;
        RECT  77.568 52.608 77.76 52.632 ;
    END
  END i_x[105]
  PIN i_x[106]
    DIRECTION INPUT ;
    USE SIGNAL ;
    PORT
      LAYER M4 ;
        RECT  77.568 52.992 77.76 53.016 ;
    END
  END i_x[106]
  PIN i_x[107]
    DIRECTION INPUT ;
    USE SIGNAL ;
    PORT
      LAYER M4 ;
        RECT  77.568 53.376 77.76 53.4 ;
    END
  END i_x[107]
  PIN i_x[108]
    DIRECTION INPUT ;
    USE SIGNAL ;
    PORT
      LAYER M4 ;
        RECT  77.568 53.76 77.76 53.784 ;
    END
  END i_x[108]
  PIN i_x[109]
    DIRECTION INPUT ;
    USE SIGNAL ;
    PORT
      LAYER M4 ;
        RECT  77.568 54.144 77.76 54.168 ;
    END
  END i_x[109]
  PIN i_x[10]
    DIRECTION INPUT ;
    USE SIGNAL ;
    PORT
      LAYER M4 ;
        RECT  77.568 16.128 77.76 16.152 ;
    END
  END i_x[10]
  PIN i_x[110]
    DIRECTION INPUT ;
    USE SIGNAL ;
    PORT
      LAYER M4 ;
        RECT  77.568 54.528 77.76 54.552 ;
    END
  END i_x[110]
  PIN i_x[111]
    DIRECTION INPUT ;
    USE SIGNAL ;
    PORT
      LAYER M4 ;
        RECT  77.568 54.912 77.76 54.936 ;
    END
  END i_x[111]
  PIN i_x[112]
    DIRECTION INPUT ;
    USE SIGNAL ;
    PORT
      LAYER M4 ;
        RECT  77.568 55.296 77.76 55.32 ;
    END
  END i_x[112]
  PIN i_x[113]
    DIRECTION INPUT ;
    USE SIGNAL ;
    PORT
      LAYER M4 ;
        RECT  77.568 55.68 77.76 55.704 ;
    END
  END i_x[113]
  PIN i_x[114]
    DIRECTION INPUT ;
    USE SIGNAL ;
    PORT
      LAYER M4 ;
        RECT  77.568 56.064 77.76 56.088 ;
    END
  END i_x[114]
  PIN i_x[115]
    DIRECTION INPUT ;
    USE SIGNAL ;
    PORT
      LAYER M4 ;
        RECT  77.568 56.448 77.76 56.472 ;
    END
  END i_x[115]
  PIN i_x[116]
    DIRECTION INPUT ;
    USE SIGNAL ;
    PORT
      LAYER M4 ;
        RECT  77.568 56.832 77.76 56.856 ;
    END
  END i_x[116]
  PIN i_x[117]
    DIRECTION INPUT ;
    USE SIGNAL ;
    PORT
      LAYER M4 ;
        RECT  77.568 57.216 77.76 57.24 ;
    END
  END i_x[117]
  PIN i_x[118]
    DIRECTION INPUT ;
    USE SIGNAL ;
    PORT
      LAYER M4 ;
        RECT  77.568 57.6 77.76 57.624 ;
    END
  END i_x[118]
  PIN i_x[119]
    DIRECTION INPUT ;
    USE SIGNAL ;
    PORT
      LAYER M4 ;
        RECT  77.568 57.984 77.76 58.008 ;
    END
  END i_x[119]
  PIN i_x[11]
    DIRECTION INPUT ;
    USE SIGNAL ;
    PORT
      LAYER M4 ;
        RECT  77.568 16.512 77.76 16.536 ;
    END
  END i_x[11]
  PIN i_x[120]
    DIRECTION INPUT ;
    USE SIGNAL ;
    PORT
      LAYER M4 ;
        RECT  77.568 58.368 77.76 58.392 ;
    END
  END i_x[120]
  PIN i_x[121]
    DIRECTION INPUT ;
    USE SIGNAL ;
    PORT
      LAYER M4 ;
        RECT  77.568 58.752 77.76 58.776 ;
    END
  END i_x[121]
  PIN i_x[122]
    DIRECTION INPUT ;
    USE SIGNAL ;
    PORT
      LAYER M4 ;
        RECT  77.568 59.136 77.76 59.16 ;
    END
  END i_x[122]
  PIN i_x[123]
    DIRECTION INPUT ;
    USE SIGNAL ;
    PORT
      LAYER M4 ;
        RECT  77.568 59.52 77.76 59.544 ;
    END
  END i_x[123]
  PIN i_x[124]
    DIRECTION INPUT ;
    USE SIGNAL ;
    PORT
      LAYER M4 ;
        RECT  77.568 59.904 77.76 59.928 ;
    END
  END i_x[124]
  PIN i_x[125]
    DIRECTION INPUT ;
    USE SIGNAL ;
    PORT
      LAYER M4 ;
        RECT  77.568 60.288 77.76 60.312 ;
    END
  END i_x[125]
  PIN i_x[126]
    DIRECTION INPUT ;
    USE SIGNAL ;
    PORT
      LAYER M4 ;
        RECT  77.568 60.672 77.76 60.696 ;
    END
  END i_x[126]
  PIN i_x[127]
    DIRECTION INPUT ;
    USE SIGNAL ;
    PORT
      LAYER M4 ;
        RECT  77.568 61.056 77.76 61.08 ;
    END
  END i_x[127]
  PIN i_x[128]
    DIRECTION INPUT ;
    USE SIGNAL ;
    PORT
      LAYER M4 ;
        RECT  77.568 61.44 77.76 61.464 ;
    END
  END i_x[128]
  PIN i_x[129]
    DIRECTION INPUT ;
    USE SIGNAL ;
    PORT
      LAYER M4 ;
        RECT  77.568 61.824 77.76 61.848 ;
    END
  END i_x[129]
  PIN i_x[12]
    DIRECTION INPUT ;
    USE SIGNAL ;
    PORT
      LAYER M4 ;
        RECT  77.568 16.896 77.76 16.92 ;
    END
  END i_x[12]
  PIN i_x[130]
    DIRECTION INPUT ;
    USE SIGNAL ;
    PORT
      LAYER M4 ;
        RECT  77.568 62.208 77.76 62.232 ;
    END
  END i_x[130]
  PIN i_x[131]
    DIRECTION INPUT ;
    USE SIGNAL ;
    PORT
      LAYER M4 ;
        RECT  77.568 62.592 77.76 62.616 ;
    END
  END i_x[131]
  PIN i_x[132]
    DIRECTION INPUT ;
    USE SIGNAL ;
    PORT
      LAYER M4 ;
        RECT  77.568 62.976 77.76 63 ;
    END
  END i_x[132]
  PIN i_x[133]
    DIRECTION INPUT ;
    USE SIGNAL ;
    PORT
      LAYER M4 ;
        RECT  77.568 63.36 77.76 63.384 ;
    END
  END i_x[133]
  PIN i_x[134]
    DIRECTION INPUT ;
    USE SIGNAL ;
    PORT
      LAYER M4 ;
        RECT  77.568 63.744 77.76 63.768 ;
    END
  END i_x[134]
  PIN i_x[135]
    DIRECTION INPUT ;
    USE SIGNAL ;
    PORT
      LAYER M4 ;
        RECT  77.568 64.128 77.76 64.152 ;
    END
  END i_x[135]
  PIN i_x[136]
    DIRECTION INPUT ;
    USE SIGNAL ;
    PORT
      LAYER M4 ;
        RECT  77.568 64.512 77.76 64.536 ;
    END
  END i_x[136]
  PIN i_x[137]
    DIRECTION INPUT ;
    USE SIGNAL ;
    PORT
      LAYER M4 ;
        RECT  77.568 64.896 77.76 64.92 ;
    END
  END i_x[137]
  PIN i_x[138]
    DIRECTION INPUT ;
    USE SIGNAL ;
    PORT
      LAYER M4 ;
        RECT  77.568 65.28 77.76 65.304 ;
    END
  END i_x[138]
  PIN i_x[139]
    DIRECTION INPUT ;
    USE SIGNAL ;
    PORT
      LAYER M4 ;
        RECT  77.568 65.664 77.76 65.688 ;
    END
  END i_x[139]
  PIN i_x[13]
    DIRECTION INPUT ;
    USE SIGNAL ;
    PORT
      LAYER M4 ;
        RECT  77.568 17.28 77.76 17.304 ;
    END
  END i_x[13]
  PIN i_x[140]
    DIRECTION INPUT ;
    USE SIGNAL ;
    PORT
      LAYER M4 ;
        RECT  77.568 66.048 77.76 66.072 ;
    END
  END i_x[140]
  PIN i_x[141]
    DIRECTION INPUT ;
    USE SIGNAL ;
    PORT
      LAYER M4 ;
        RECT  77.568 66.432 77.76 66.456 ;
    END
  END i_x[141]
  PIN i_x[142]
    DIRECTION INPUT ;
    USE SIGNAL ;
    PORT
      LAYER M4 ;
        RECT  77.568 66.816 77.76 66.84 ;
    END
  END i_x[142]
  PIN i_x[143]
    DIRECTION INPUT ;
    USE SIGNAL ;
    PORT
      LAYER M4 ;
        RECT  77.568 67.2 77.76 67.224 ;
    END
  END i_x[143]
  PIN i_x[144]
    DIRECTION INPUT ;
    USE SIGNAL ;
    PORT
      LAYER M4 ;
        RECT  77.568 67.584 77.76 67.608 ;
    END
  END i_x[144]
  PIN i_x[145]
    DIRECTION INPUT ;
    USE SIGNAL ;
    PORT
      LAYER M4 ;
        RECT  77.568 67.968 77.76 67.992 ;
    END
  END i_x[145]
  PIN i_x[146]
    DIRECTION INPUT ;
    USE SIGNAL ;
    PORT
      LAYER M4 ;
        RECT  77.568 68.352 77.76 68.376 ;
    END
  END i_x[146]
  PIN i_x[147]
    DIRECTION INPUT ;
    USE SIGNAL ;
    PORT
      LAYER M4 ;
        RECT  77.568 68.736 77.76 68.76 ;
    END
  END i_x[147]
  PIN i_x[148]
    DIRECTION INPUT ;
    USE SIGNAL ;
    PORT
      LAYER M4 ;
        RECT  77.568 69.12 77.76 69.144 ;
    END
  END i_x[148]
  PIN i_x[149]
    DIRECTION INPUT ;
    USE SIGNAL ;
    PORT
      LAYER M4 ;
        RECT  77.568 69.504 77.76 69.528 ;
    END
  END i_x[149]
  PIN i_x[14]
    DIRECTION INPUT ;
    USE SIGNAL ;
    PORT
      LAYER M4 ;
        RECT  77.568 17.664 77.76 17.688 ;
    END
  END i_x[14]
  PIN i_x[150]
    DIRECTION INPUT ;
    USE SIGNAL ;
    PORT
      LAYER M4 ;
        RECT  77.568 69.888 77.76 69.912 ;
    END
  END i_x[150]
  PIN i_x[151]
    DIRECTION INPUT ;
    USE SIGNAL ;
    PORT
      LAYER M4 ;
        RECT  77.568 70.272 77.76 70.296 ;
    END
  END i_x[151]
  PIN i_x[152]
    DIRECTION INPUT ;
    USE SIGNAL ;
    PORT
      LAYER M4 ;
        RECT  77.568 70.656 77.76 70.68 ;
    END
  END i_x[152]
  PIN i_x[153]
    DIRECTION INPUT ;
    USE SIGNAL ;
    PORT
      LAYER M4 ;
        RECT  77.568 71.04 77.76 71.064 ;
    END
  END i_x[153]
  PIN i_x[154]
    DIRECTION INPUT ;
    USE SIGNAL ;
    PORT
      LAYER M4 ;
        RECT  77.568 71.424 77.76 71.448 ;
    END
  END i_x[154]
  PIN i_x[155]
    DIRECTION INPUT ;
    USE SIGNAL ;
    PORT
      LAYER M4 ;
        RECT  77.568 71.808 77.76 71.832 ;
    END
  END i_x[155]
  PIN i_x[156]
    DIRECTION INPUT ;
    USE SIGNAL ;
    PORT
      LAYER M4 ;
        RECT  77.568 72.192 77.76 72.216 ;
    END
  END i_x[156]
  PIN i_x[157]
    DIRECTION INPUT ;
    USE SIGNAL ;
    PORT
      LAYER M4 ;
        RECT  77.568 72.576 77.76 72.6 ;
    END
  END i_x[157]
  PIN i_x[158]
    DIRECTION INPUT ;
    USE SIGNAL ;
    PORT
      LAYER M4 ;
        RECT  77.568 72.96 77.76 72.984 ;
    END
  END i_x[158]
  PIN i_x[159]
    DIRECTION INPUT ;
    USE SIGNAL ;
    PORT
      LAYER M4 ;
        RECT  77.568 73.344 77.76 73.368 ;
    END
  END i_x[159]
  PIN i_x[15]
    DIRECTION INPUT ;
    USE SIGNAL ;
    PORT
      LAYER M4 ;
        RECT  77.568 18.048 77.76 18.072 ;
    END
  END i_x[15]
  PIN i_x[160]
    DIRECTION INPUT ;
    USE SIGNAL ;
    PORT
      LAYER M4 ;
        RECT  77.568 73.728 77.76 73.752 ;
    END
  END i_x[160]
  PIN i_x[161]
    DIRECTION INPUT ;
    USE SIGNAL ;
    PORT
      LAYER M4 ;
        RECT  77.568 74.112 77.76 74.136 ;
    END
  END i_x[161]
  PIN i_x[162]
    DIRECTION INPUT ;
    USE SIGNAL ;
    PORT
      LAYER M4 ;
        RECT  77.568 74.496 77.76 74.52 ;
    END
  END i_x[162]
  PIN i_x[163]
    DIRECTION INPUT ;
    USE SIGNAL ;
    PORT
      LAYER M4 ;
        RECT  77.568 74.88 77.76 74.904 ;
    END
  END i_x[163]
  PIN i_x[164]
    DIRECTION INPUT ;
    USE SIGNAL ;
    PORT
      LAYER M4 ;
        RECT  77.568 75.264 77.76 75.288 ;
    END
  END i_x[164]
  PIN i_x[165]
    DIRECTION INPUT ;
    USE SIGNAL ;
    PORT
      LAYER M4 ;
        RECT  77.568 75.648 77.76 75.672 ;
    END
  END i_x[165]
  PIN i_x[166]
    DIRECTION INPUT ;
    USE SIGNAL ;
    PORT
      LAYER M4 ;
        RECT  77.568 76.032 77.76 76.056 ;
    END
  END i_x[166]
  PIN i_x[167]
    DIRECTION INPUT ;
    USE SIGNAL ;
    PORT
      LAYER M4 ;
        RECT  77.568 76.416 77.76 76.44 ;
    END
  END i_x[167]
  PIN i_x[168]
    DIRECTION INPUT ;
    USE SIGNAL ;
    PORT
      LAYER M4 ;
        RECT  77.568 76.8 77.76 76.824 ;
    END
  END i_x[168]
  PIN i_x[169]
    DIRECTION INPUT ;
    USE SIGNAL ;
    PORT
      LAYER M4 ;
        RECT  77.568 77.184 77.76 77.208 ;
    END
  END i_x[169]
  PIN i_x[16]
    DIRECTION INPUT ;
    USE SIGNAL ;
    PORT
      LAYER M4 ;
        RECT  77.568 18.432 77.76 18.456 ;
    END
  END i_x[16]
  PIN i_x[170]
    DIRECTION INPUT ;
    USE SIGNAL ;
    PORT
      LAYER M4 ;
        RECT  77.568 77.568 77.76 77.592 ;
    END
  END i_x[170]
  PIN i_x[171]
    DIRECTION INPUT ;
    USE SIGNAL ;
    PORT
      LAYER M4 ;
        RECT  77.568 77.952 77.76 77.976 ;
    END
  END i_x[171]
  PIN i_x[172]
    DIRECTION INPUT ;
    USE SIGNAL ;
    PORT
      LAYER M4 ;
        RECT  77.568 78.336 77.76 78.36 ;
    END
  END i_x[172]
  PIN i_x[173]
    DIRECTION INPUT ;
    USE SIGNAL ;
    PORT
      LAYER M4 ;
        RECT  77.568 78.72 77.76 78.744 ;
    END
  END i_x[173]
  PIN i_x[174]
    DIRECTION INPUT ;
    USE SIGNAL ;
    PORT
      LAYER M4 ;
        RECT  77.568 79.104 77.76 79.128 ;
    END
  END i_x[174]
  PIN i_x[175]
    DIRECTION INPUT ;
    USE SIGNAL ;
    PORT
      LAYER M4 ;
        RECT  77.568 79.488 77.76 79.512 ;
    END
  END i_x[175]
  PIN i_x[176]
    DIRECTION INPUT ;
    USE SIGNAL ;
    PORT
      LAYER M4 ;
        RECT  77.568 79.872 77.76 79.896 ;
    END
  END i_x[176]
  PIN i_x[177]
    DIRECTION INPUT ;
    USE SIGNAL ;
    PORT
      LAYER M4 ;
        RECT  77.568 80.256 77.76 80.28 ;
    END
  END i_x[177]
  PIN i_x[178]
    DIRECTION INPUT ;
    USE SIGNAL ;
    PORT
      LAYER M4 ;
        RECT  77.568 80.64 77.76 80.664 ;
    END
  END i_x[178]
  PIN i_x[179]
    DIRECTION INPUT ;
    USE SIGNAL ;
    PORT
      LAYER M4 ;
        RECT  77.568 81.024 77.76 81.048 ;
    END
  END i_x[179]
  PIN i_x[17]
    DIRECTION INPUT ;
    USE SIGNAL ;
    PORT
      LAYER M4 ;
        RECT  77.568 18.816 77.76 18.84 ;
    END
  END i_x[17]
  PIN i_x[180]
    DIRECTION INPUT ;
    USE SIGNAL ;
    PORT
      LAYER M4 ;
        RECT  77.568 81.408 77.76 81.432 ;
    END
  END i_x[180]
  PIN i_x[181]
    DIRECTION INPUT ;
    USE SIGNAL ;
    PORT
      LAYER M4 ;
        RECT  77.568 81.792 77.76 81.816 ;
    END
  END i_x[181]
  PIN i_x[182]
    DIRECTION INPUT ;
    USE SIGNAL ;
    PORT
      LAYER M4 ;
        RECT  77.568 82.176 77.76 82.2 ;
    END
  END i_x[182]
  PIN i_x[183]
    DIRECTION INPUT ;
    USE SIGNAL ;
    PORT
      LAYER M4 ;
        RECT  77.568 82.56 77.76 82.584 ;
    END
  END i_x[183]
  PIN i_x[184]
    DIRECTION INPUT ;
    USE SIGNAL ;
    PORT
      LAYER M4 ;
        RECT  77.568 82.944 77.76 82.968 ;
    END
  END i_x[184]
  PIN i_x[185]
    DIRECTION INPUT ;
    USE SIGNAL ;
    PORT
      LAYER M4 ;
        RECT  77.568 83.328 77.76 83.352 ;
    END
  END i_x[185]
  PIN i_x[186]
    DIRECTION INPUT ;
    USE SIGNAL ;
    PORT
      LAYER M4 ;
        RECT  77.568 83.712 77.76 83.736 ;
    END
  END i_x[186]
  PIN i_x[187]
    DIRECTION INPUT ;
    USE SIGNAL ;
    PORT
      LAYER M4 ;
        RECT  77.568 84.096 77.76 84.12 ;
    END
  END i_x[187]
  PIN i_x[188]
    DIRECTION INPUT ;
    USE SIGNAL ;
    PORT
      LAYER M4 ;
        RECT  77.568 84.48 77.76 84.504 ;
    END
  END i_x[188]
  PIN i_x[189]
    DIRECTION INPUT ;
    USE SIGNAL ;
    PORT
      LAYER M4 ;
        RECT  77.568 84.864 77.76 84.888 ;
    END
  END i_x[189]
  PIN i_x[18]
    DIRECTION INPUT ;
    USE SIGNAL ;
    PORT
      LAYER M4 ;
        RECT  77.568 19.2 77.76 19.224 ;
    END
  END i_x[18]
  PIN i_x[190]
    DIRECTION INPUT ;
    USE SIGNAL ;
    PORT
      LAYER M4 ;
        RECT  77.568 85.248 77.76 85.272 ;
    END
  END i_x[190]
  PIN i_x[191]
    DIRECTION INPUT ;
    USE SIGNAL ;
    PORT
      LAYER M4 ;
        RECT  77.568 85.632 77.76 85.656 ;
    END
  END i_x[191]
  PIN i_x[192]
    DIRECTION INPUT ;
    USE SIGNAL ;
    PORT
      LAYER M4 ;
        RECT  77.568 86.016 77.76 86.04 ;
    END
  END i_x[192]
  PIN i_x[193]
    DIRECTION INPUT ;
    USE SIGNAL ;
    PORT
      LAYER M4 ;
        RECT  77.568 86.4 77.76 86.424 ;
    END
  END i_x[193]
  PIN i_x[194]
    DIRECTION INPUT ;
    USE SIGNAL ;
    PORT
      LAYER M4 ;
        RECT  77.568 86.784 77.76 86.808 ;
    END
  END i_x[194]
  PIN i_x[195]
    DIRECTION INPUT ;
    USE SIGNAL ;
    PORT
      LAYER M4 ;
        RECT  77.568 87.168 77.76 87.192 ;
    END
  END i_x[195]
  PIN i_x[196]
    DIRECTION INPUT ;
    USE SIGNAL ;
    PORT
      LAYER M4 ;
        RECT  77.568 87.552 77.76 87.576 ;
    END
  END i_x[196]
  PIN i_x[197]
    DIRECTION INPUT ;
    USE SIGNAL ;
    PORT
      LAYER M4 ;
        RECT  77.568 87.936 77.76 87.96 ;
    END
  END i_x[197]
  PIN i_x[198]
    DIRECTION INPUT ;
    USE SIGNAL ;
    PORT
      LAYER M4 ;
        RECT  77.568 88.32 77.76 88.344 ;
    END
  END i_x[198]
  PIN i_x[199]
    DIRECTION INPUT ;
    USE SIGNAL ;
    PORT
      LAYER M4 ;
        RECT  77.568 88.704 77.76 88.728 ;
    END
  END i_x[199]
  PIN i_x[19]
    DIRECTION INPUT ;
    USE SIGNAL ;
    PORT
      LAYER M4 ;
        RECT  77.568 19.584 77.76 19.608 ;
    END
  END i_x[19]
  PIN i_x[1]
    DIRECTION INPUT ;
    USE SIGNAL ;
    PORT
      LAYER M4 ;
        RECT  77.568 12.672 77.76 12.696 ;
    END
  END i_x[1]
  PIN i_x[200]
    DIRECTION INPUT ;
    USE SIGNAL ;
    PORT
      LAYER M4 ;
        RECT  77.568 89.088 77.76 89.112 ;
    END
  END i_x[200]
  PIN i_x[201]
    DIRECTION INPUT ;
    USE SIGNAL ;
    PORT
      LAYER M4 ;
        RECT  77.568 89.472 77.76 89.496 ;
    END
  END i_x[201]
  PIN i_x[202]
    DIRECTION INPUT ;
    USE SIGNAL ;
    PORT
      LAYER M4 ;
        RECT  77.568 89.856 77.76 89.88 ;
    END
  END i_x[202]
  PIN i_x[203]
    DIRECTION INPUT ;
    USE SIGNAL ;
    PORT
      LAYER M4 ;
        RECT  77.568 90.24 77.76 90.264 ;
    END
  END i_x[203]
  PIN i_x[204]
    DIRECTION INPUT ;
    USE SIGNAL ;
    PORT
      LAYER M4 ;
        RECT  77.568 90.624 77.76 90.648 ;
    END
  END i_x[204]
  PIN i_x[205]
    DIRECTION INPUT ;
    USE SIGNAL ;
    PORT
      LAYER M4 ;
        RECT  77.568 91.008 77.76 91.032 ;
    END
  END i_x[205]
  PIN i_x[206]
    DIRECTION INPUT ;
    USE SIGNAL ;
    PORT
      LAYER M4 ;
        RECT  77.568 91.392 77.76 91.416 ;
    END
  END i_x[206]
  PIN i_x[207]
    DIRECTION INPUT ;
    USE SIGNAL ;
    PORT
      LAYER M4 ;
        RECT  77.568 91.776 77.76 91.8 ;
    END
  END i_x[207]
  PIN i_x[208]
    DIRECTION INPUT ;
    USE SIGNAL ;
    PORT
      LAYER M4 ;
        RECT  77.568 92.16 77.76 92.184 ;
    END
  END i_x[208]
  PIN i_x[209]
    DIRECTION INPUT ;
    USE SIGNAL ;
    PORT
      LAYER M4 ;
        RECT  77.568 92.544 77.76 92.568 ;
    END
  END i_x[209]
  PIN i_x[20]
    DIRECTION INPUT ;
    USE SIGNAL ;
    PORT
      LAYER M4 ;
        RECT  77.568 19.968 77.76 19.992 ;
    END
  END i_x[20]
  PIN i_x[210]
    DIRECTION INPUT ;
    USE SIGNAL ;
    PORT
      LAYER M4 ;
        RECT  77.568 92.928 77.76 92.952 ;
    END
  END i_x[210]
  PIN i_x[211]
    DIRECTION INPUT ;
    USE SIGNAL ;
    PORT
      LAYER M4 ;
        RECT  77.568 93.312 77.76 93.336 ;
    END
  END i_x[211]
  PIN i_x[212]
    DIRECTION INPUT ;
    USE SIGNAL ;
    PORT
      LAYER M4 ;
        RECT  77.568 93.696 77.76 93.72 ;
    END
  END i_x[212]
  PIN i_x[213]
    DIRECTION INPUT ;
    USE SIGNAL ;
    PORT
      LAYER M4 ;
        RECT  77.568 94.08 77.76 94.104 ;
    END
  END i_x[213]
  PIN i_x[214]
    DIRECTION INPUT ;
    USE SIGNAL ;
    PORT
      LAYER M4 ;
        RECT  77.568 94.464 77.76 94.488 ;
    END
  END i_x[214]
  PIN i_x[215]
    DIRECTION INPUT ;
    USE SIGNAL ;
    PORT
      LAYER M4 ;
        RECT  77.568 94.848 77.76 94.872 ;
    END
  END i_x[215]
  PIN i_x[216]
    DIRECTION INPUT ;
    USE SIGNAL ;
    PORT
      LAYER M4 ;
        RECT  77.568 95.232 77.76 95.256 ;
    END
  END i_x[216]
  PIN i_x[217]
    DIRECTION INPUT ;
    USE SIGNAL ;
    PORT
      LAYER M4 ;
        RECT  77.568 95.616 77.76 95.64 ;
    END
  END i_x[217]
  PIN i_x[218]
    DIRECTION INPUT ;
    USE SIGNAL ;
    PORT
      LAYER M4 ;
        RECT  77.568 96 77.76 96.024 ;
    END
  END i_x[218]
  PIN i_x[219]
    DIRECTION INPUT ;
    USE SIGNAL ;
    PORT
      LAYER M4 ;
        RECT  77.568 96.384 77.76 96.408 ;
    END
  END i_x[219]
  PIN i_x[21]
    DIRECTION INPUT ;
    USE SIGNAL ;
    PORT
      LAYER M4 ;
        RECT  77.568 20.352 77.76 20.376 ;
    END
  END i_x[21]
  PIN i_x[220]
    DIRECTION INPUT ;
    USE SIGNAL ;
    PORT
      LAYER M4 ;
        RECT  77.568 96.768 77.76 96.792 ;
    END
  END i_x[220]
  PIN i_x[221]
    DIRECTION INPUT ;
    USE SIGNAL ;
    PORT
      LAYER M4 ;
        RECT  77.568 97.152 77.76 97.176 ;
    END
  END i_x[221]
  PIN i_x[222]
    DIRECTION INPUT ;
    USE SIGNAL ;
    PORT
      LAYER M4 ;
        RECT  77.568 97.536 77.76 97.56 ;
    END
  END i_x[222]
  PIN i_x[223]
    DIRECTION INPUT ;
    USE SIGNAL ;
    PORT
      LAYER M4 ;
        RECT  77.568 97.92 77.76 97.944 ;
    END
  END i_x[223]
  PIN i_x[224]
    DIRECTION INPUT ;
    USE SIGNAL ;
    PORT
      LAYER M4 ;
        RECT  77.568 98.304 77.76 98.328 ;
    END
  END i_x[224]
  PIN i_x[225]
    DIRECTION INPUT ;
    USE SIGNAL ;
    PORT
      LAYER M4 ;
        RECT  77.568 98.688 77.76 98.712 ;
    END
  END i_x[225]
  PIN i_x[226]
    DIRECTION INPUT ;
    USE SIGNAL ;
    PORT
      LAYER M4 ;
        RECT  77.568 99.072 77.76 99.096 ;
    END
  END i_x[226]
  PIN i_x[227]
    DIRECTION INPUT ;
    USE SIGNAL ;
    PORT
      LAYER M4 ;
        RECT  77.568 99.456 77.76 99.48 ;
    END
  END i_x[227]
  PIN i_x[228]
    DIRECTION INPUT ;
    USE SIGNAL ;
    PORT
      LAYER M4 ;
        RECT  77.568 99.84 77.76 99.864 ;
    END
  END i_x[228]
  PIN i_x[229]
    DIRECTION INPUT ;
    USE SIGNAL ;
    PORT
      LAYER M4 ;
        RECT  77.568 100.224 77.76 100.248 ;
    END
  END i_x[229]
  PIN i_x[22]
    DIRECTION INPUT ;
    USE SIGNAL ;
    PORT
      LAYER M4 ;
        RECT  77.568 20.736 77.76 20.76 ;
    END
  END i_x[22]
  PIN i_x[230]
    DIRECTION INPUT ;
    USE SIGNAL ;
    PORT
      LAYER M4 ;
        RECT  77.568 100.608 77.76 100.632 ;
    END
  END i_x[230]
  PIN i_x[231]
    DIRECTION INPUT ;
    USE SIGNAL ;
    PORT
      LAYER M4 ;
        RECT  77.568 100.992 77.76 101.016 ;
    END
  END i_x[231]
  PIN i_x[232]
    DIRECTION INPUT ;
    USE SIGNAL ;
    PORT
      LAYER M4 ;
        RECT  77.568 101.376 77.76 101.4 ;
    END
  END i_x[232]
  PIN i_x[233]
    DIRECTION INPUT ;
    USE SIGNAL ;
    PORT
      LAYER M4 ;
        RECT  77.568 101.76 77.76 101.784 ;
    END
  END i_x[233]
  PIN i_x[234]
    DIRECTION INPUT ;
    USE SIGNAL ;
    PORT
      LAYER M4 ;
        RECT  77.568 102.144 77.76 102.168 ;
    END
  END i_x[234]
  PIN i_x[235]
    DIRECTION INPUT ;
    USE SIGNAL ;
    PORT
      LAYER M4 ;
        RECT  77.568 102.528 77.76 102.552 ;
    END
  END i_x[235]
  PIN i_x[236]
    DIRECTION INPUT ;
    USE SIGNAL ;
    PORT
      LAYER M4 ;
        RECT  77.568 102.912 77.76 102.936 ;
    END
  END i_x[236]
  PIN i_x[237]
    DIRECTION INPUT ;
    USE SIGNAL ;
    PORT
      LAYER M4 ;
        RECT  77.568 103.296 77.76 103.32 ;
    END
  END i_x[237]
  PIN i_x[238]
    DIRECTION INPUT ;
    USE SIGNAL ;
    PORT
      LAYER M4 ;
        RECT  77.568 103.68 77.76 103.704 ;
    END
  END i_x[238]
  PIN i_x[239]
    DIRECTION INPUT ;
    USE SIGNAL ;
    PORT
      LAYER M4 ;
        RECT  77.568 104.064 77.76 104.088 ;
    END
  END i_x[239]
  PIN i_x[23]
    DIRECTION INPUT ;
    USE SIGNAL ;
    PORT
      LAYER M4 ;
        RECT  77.568 21.12 77.76 21.144 ;
    END
  END i_x[23]
  PIN i_x[240]
    DIRECTION INPUT ;
    USE SIGNAL ;
    PORT
      LAYER M4 ;
        RECT  77.568 104.448 77.76 104.472 ;
    END
  END i_x[240]
  PIN i_x[241]
    DIRECTION INPUT ;
    USE SIGNAL ;
    PORT
      LAYER M4 ;
        RECT  77.568 104.832 77.76 104.856 ;
    END
  END i_x[241]
  PIN i_x[242]
    DIRECTION INPUT ;
    USE SIGNAL ;
    PORT
      LAYER M4 ;
        RECT  77.568 105.216 77.76 105.24 ;
    END
  END i_x[242]
  PIN i_x[243]
    DIRECTION INPUT ;
    USE SIGNAL ;
    PORT
      LAYER M4 ;
        RECT  77.568 105.6 77.76 105.624 ;
    END
  END i_x[243]
  PIN i_x[244]
    DIRECTION INPUT ;
    USE SIGNAL ;
    PORT
      LAYER M4 ;
        RECT  77.568 105.984 77.76 106.008 ;
    END
  END i_x[244]
  PIN i_x[245]
    DIRECTION INPUT ;
    USE SIGNAL ;
    PORT
      LAYER M4 ;
        RECT  77.568 106.368 77.76 106.392 ;
    END
  END i_x[245]
  PIN i_x[246]
    DIRECTION INPUT ;
    USE SIGNAL ;
    PORT
      LAYER M4 ;
        RECT  77.568 106.752 77.76 106.776 ;
    END
  END i_x[246]
  PIN i_x[247]
    DIRECTION INPUT ;
    USE SIGNAL ;
    PORT
      LAYER M4 ;
        RECT  77.568 107.136 77.76 107.16 ;
    END
  END i_x[247]
  PIN i_x[248]
    DIRECTION INPUT ;
    USE SIGNAL ;
    PORT
      LAYER M4 ;
        RECT  77.568 107.52 77.76 107.544 ;
    END
  END i_x[248]
  PIN i_x[249]
    DIRECTION INPUT ;
    USE SIGNAL ;
    PORT
      LAYER M4 ;
        RECT  77.568 107.904 77.76 107.928 ;
    END
  END i_x[249]
  PIN i_x[24]
    DIRECTION INPUT ;
    USE SIGNAL ;
    PORT
      LAYER M4 ;
        RECT  77.568 21.504 77.76 21.528 ;
    END
  END i_x[24]
  PIN i_x[250]
    DIRECTION INPUT ;
    USE SIGNAL ;
    PORT
      LAYER M4 ;
        RECT  77.568 108.288 77.76 108.312 ;
    END
  END i_x[250]
  PIN i_x[251]
    DIRECTION INPUT ;
    USE SIGNAL ;
    PORT
      LAYER M4 ;
        RECT  77.568 108.672 77.76 108.696 ;
    END
  END i_x[251]
  PIN i_x[252]
    DIRECTION INPUT ;
    USE SIGNAL ;
    PORT
      LAYER M4 ;
        RECT  77.568 109.056 77.76 109.08 ;
    END
  END i_x[252]
  PIN i_x[253]
    DIRECTION INPUT ;
    USE SIGNAL ;
    PORT
      LAYER M4 ;
        RECT  77.568 109.44 77.76 109.464 ;
    END
  END i_x[253]
  PIN i_x[254]
    DIRECTION INPUT ;
    USE SIGNAL ;
    PORT
      LAYER M4 ;
        RECT  77.568 109.824 77.76 109.848 ;
    END
  END i_x[254]
  PIN i_x[255]
    DIRECTION INPUT ;
    USE SIGNAL ;
    PORT
      LAYER M4 ;
        RECT  77.568 110.208 77.76 110.232 ;
    END
  END i_x[255]
  PIN i_x[256]
    DIRECTION INPUT ;
    USE SIGNAL ;
    PORT
      LAYER M4 ;
        RECT  77.568 110.592 77.76 110.616 ;
    END
  END i_x[256]
  PIN i_x[257]
    DIRECTION INPUT ;
    USE SIGNAL ;
    PORT
      LAYER M4 ;
        RECT  77.568 110.976 77.76 111 ;
    END
  END i_x[257]
  PIN i_x[258]
    DIRECTION INPUT ;
    USE SIGNAL ;
    PORT
      LAYER M4 ;
        RECT  77.568 111.36 77.76 111.384 ;
    END
  END i_x[258]
  PIN i_x[259]
    DIRECTION INPUT ;
    USE SIGNAL ;
    PORT
      LAYER M4 ;
        RECT  77.568 111.744 77.76 111.768 ;
    END
  END i_x[259]
  PIN i_x[25]
    DIRECTION INPUT ;
    USE SIGNAL ;
    PORT
      LAYER M4 ;
        RECT  77.568 21.888 77.76 21.912 ;
    END
  END i_x[25]
  PIN i_x[260]
    DIRECTION INPUT ;
    USE SIGNAL ;
    PORT
      LAYER M4 ;
        RECT  77.568 112.128 77.76 112.152 ;
    END
  END i_x[260]
  PIN i_x[261]
    DIRECTION INPUT ;
    USE SIGNAL ;
    PORT
      LAYER M4 ;
        RECT  77.568 112.512 77.76 112.536 ;
    END
  END i_x[261]
  PIN i_x[262]
    DIRECTION INPUT ;
    USE SIGNAL ;
    PORT
      LAYER M4 ;
        RECT  77.568 112.896 77.76 112.92 ;
    END
  END i_x[262]
  PIN i_x[263]
    DIRECTION INPUT ;
    USE SIGNAL ;
    PORT
      LAYER M4 ;
        RECT  77.568 113.28 77.76 113.304 ;
    END
  END i_x[263]
  PIN i_x[264]
    DIRECTION INPUT ;
    USE SIGNAL ;
    PORT
      LAYER M4 ;
        RECT  77.568 113.664 77.76 113.688 ;
    END
  END i_x[264]
  PIN i_x[265]
    DIRECTION INPUT ;
    USE SIGNAL ;
    PORT
      LAYER M4 ;
        RECT  77.568 114.048 77.76 114.072 ;
    END
  END i_x[265]
  PIN i_x[266]
    DIRECTION INPUT ;
    USE SIGNAL ;
    PORT
      LAYER M4 ;
        RECT  77.568 114.432 77.76 114.456 ;
    END
  END i_x[266]
  PIN i_x[267]
    DIRECTION INPUT ;
    USE SIGNAL ;
    PORT
      LAYER M4 ;
        RECT  77.568 114.816 77.76 114.84 ;
    END
  END i_x[267]
  PIN i_x[268]
    DIRECTION INPUT ;
    USE SIGNAL ;
    PORT
      LAYER M4 ;
        RECT  77.568 115.2 77.76 115.224 ;
    END
  END i_x[268]
  PIN i_x[269]
    DIRECTION INPUT ;
    USE SIGNAL ;
    PORT
      LAYER M4 ;
        RECT  77.568 115.584 77.76 115.608 ;
    END
  END i_x[269]
  PIN i_x[26]
    DIRECTION INPUT ;
    USE SIGNAL ;
    PORT
      LAYER M4 ;
        RECT  77.568 22.272 77.76 22.296 ;
    END
  END i_x[26]
  PIN i_x[270]
    DIRECTION INPUT ;
    USE SIGNAL ;
    PORT
      LAYER M4 ;
        RECT  77.568 115.968 77.76 115.992 ;
    END
  END i_x[270]
  PIN i_x[271]
    DIRECTION INPUT ;
    USE SIGNAL ;
    PORT
      LAYER M4 ;
        RECT  77.568 116.352 77.76 116.376 ;
    END
  END i_x[271]
  PIN i_x[272]
    DIRECTION INPUT ;
    USE SIGNAL ;
    PORT
      LAYER M4 ;
        RECT  77.568 116.736 77.76 116.76 ;
    END
  END i_x[272]
  PIN i_x[273]
    DIRECTION INPUT ;
    USE SIGNAL ;
    PORT
      LAYER M4 ;
        RECT  77.568 117.12 77.76 117.144 ;
    END
  END i_x[273]
  PIN i_x[274]
    DIRECTION INPUT ;
    USE SIGNAL ;
    PORT
      LAYER M4 ;
        RECT  77.568 117.504 77.76 117.528 ;
    END
  END i_x[274]
  PIN i_x[275]
    DIRECTION INPUT ;
    USE SIGNAL ;
    PORT
      LAYER M4 ;
        RECT  77.568 117.888 77.76 117.912 ;
    END
  END i_x[275]
  PIN i_x[276]
    DIRECTION INPUT ;
    USE SIGNAL ;
    PORT
      LAYER M4 ;
        RECT  77.568 118.272 77.76 118.296 ;
    END
  END i_x[276]
  PIN i_x[277]
    DIRECTION INPUT ;
    USE SIGNAL ;
    PORT
      LAYER M4 ;
        RECT  77.568 118.656 77.76 118.68 ;
    END
  END i_x[277]
  PIN i_x[278]
    DIRECTION INPUT ;
    USE SIGNAL ;
    PORT
      LAYER M4 ;
        RECT  77.568 119.04 77.76 119.064 ;
    END
  END i_x[278]
  PIN i_x[279]
    DIRECTION INPUT ;
    USE SIGNAL ;
    PORT
      LAYER M4 ;
        RECT  77.568 119.424 77.76 119.448 ;
    END
  END i_x[279]
  PIN i_x[27]
    DIRECTION INPUT ;
    USE SIGNAL ;
    PORT
      LAYER M4 ;
        RECT  77.568 22.656 77.76 22.68 ;
    END
  END i_x[27]
  PIN i_x[280]
    DIRECTION INPUT ;
    USE SIGNAL ;
    PORT
      LAYER M4 ;
        RECT  77.568 119.808 77.76 119.832 ;
    END
  END i_x[280]
  PIN i_x[281]
    DIRECTION INPUT ;
    USE SIGNAL ;
    PORT
      LAYER M4 ;
        RECT  77.568 120.192 77.76 120.216 ;
    END
  END i_x[281]
  PIN i_x[282]
    DIRECTION INPUT ;
    USE SIGNAL ;
    PORT
      LAYER M4 ;
        RECT  77.568 120.576 77.76 120.6 ;
    END
  END i_x[282]
  PIN i_x[283]
    DIRECTION INPUT ;
    USE SIGNAL ;
    PORT
      LAYER M4 ;
        RECT  77.568 120.96 77.76 120.984 ;
    END
  END i_x[283]
  PIN i_x[284]
    DIRECTION INPUT ;
    USE SIGNAL ;
    PORT
      LAYER M4 ;
        RECT  77.568 121.344 77.76 121.368 ;
    END
  END i_x[284]
  PIN i_x[285]
    DIRECTION INPUT ;
    USE SIGNAL ;
    PORT
      LAYER M4 ;
        RECT  77.568 121.728 77.76 121.752 ;
    END
  END i_x[285]
  PIN i_x[286]
    DIRECTION INPUT ;
    USE SIGNAL ;
    PORT
      LAYER M4 ;
        RECT  77.568 122.112 77.76 122.136 ;
    END
  END i_x[286]
  PIN i_x[287]
    DIRECTION INPUT ;
    USE SIGNAL ;
    PORT
      LAYER M4 ;
        RECT  77.568 122.496 77.76 122.52 ;
    END
  END i_x[287]
  PIN i_x[288]
    DIRECTION INPUT ;
    USE SIGNAL ;
    PORT
      LAYER M4 ;
        RECT  77.568 122.88 77.76 122.904 ;
    END
  END i_x[288]
  PIN i_x[289]
    DIRECTION INPUT ;
    USE SIGNAL ;
    PORT
      LAYER M4 ;
        RECT  77.568 123.264 77.76 123.288 ;
    END
  END i_x[289]
  PIN i_x[28]
    DIRECTION INPUT ;
    USE SIGNAL ;
    PORT
      LAYER M4 ;
        RECT  77.568 23.04 77.76 23.064 ;
    END
  END i_x[28]
  PIN i_x[290]
    DIRECTION INPUT ;
    USE SIGNAL ;
    PORT
      LAYER M4 ;
        RECT  77.568 123.648 77.76 123.672 ;
    END
  END i_x[290]
  PIN i_x[291]
    DIRECTION INPUT ;
    USE SIGNAL ;
    PORT
      LAYER M4 ;
        RECT  77.568 124.032 77.76 124.056 ;
    END
  END i_x[291]
  PIN i_x[292]
    DIRECTION INPUT ;
    USE SIGNAL ;
    PORT
      LAYER M4 ;
        RECT  77.568 124.416 77.76 124.44 ;
    END
  END i_x[292]
  PIN i_x[293]
    DIRECTION INPUT ;
    USE SIGNAL ;
    PORT
      LAYER M4 ;
        RECT  77.568 124.8 77.76 124.824 ;
    END
  END i_x[293]
  PIN i_x[294]
    DIRECTION INPUT ;
    USE SIGNAL ;
    PORT
      LAYER M4 ;
        RECT  77.568 125.184 77.76 125.208 ;
    END
  END i_x[294]
  PIN i_x[295]
    DIRECTION INPUT ;
    USE SIGNAL ;
    PORT
      LAYER M4 ;
        RECT  77.568 125.568 77.76 125.592 ;
    END
  END i_x[295]
  PIN i_x[296]
    DIRECTION INPUT ;
    USE SIGNAL ;
    PORT
      LAYER M4 ;
        RECT  77.568 125.952 77.76 125.976 ;
    END
  END i_x[296]
  PIN i_x[297]
    DIRECTION INPUT ;
    USE SIGNAL ;
    PORT
      LAYER M4 ;
        RECT  77.568 126.336 77.76 126.36 ;
    END
  END i_x[297]
  PIN i_x[298]
    DIRECTION INPUT ;
    USE SIGNAL ;
    PORT
      LAYER M4 ;
        RECT  77.568 126.72 77.76 126.744 ;
    END
  END i_x[298]
  PIN i_x[299]
    DIRECTION INPUT ;
    USE SIGNAL ;
    PORT
      LAYER M4 ;
        RECT  77.568 127.104 77.76 127.128 ;
    END
  END i_x[299]
  PIN i_x[29]
    DIRECTION INPUT ;
    USE SIGNAL ;
    PORT
      LAYER M4 ;
        RECT  77.568 23.424 77.76 23.448 ;
    END
  END i_x[29]
  PIN i_x[2]
    DIRECTION INPUT ;
    USE SIGNAL ;
    PORT
      LAYER M4 ;
        RECT  77.568 13.056 77.76 13.08 ;
    END
  END i_x[2]
  PIN i_x[300]
    DIRECTION INPUT ;
    USE SIGNAL ;
    PORT
      LAYER M4 ;
        RECT  77.568 127.488 77.76 127.512 ;
    END
  END i_x[300]
  PIN i_x[301]
    DIRECTION INPUT ;
    USE SIGNAL ;
    PORT
      LAYER M4 ;
        RECT  77.568 127.872 77.76 127.896 ;
    END
  END i_x[301]
  PIN i_x[302]
    DIRECTION INPUT ;
    USE SIGNAL ;
    PORT
      LAYER M4 ;
        RECT  77.568 128.256 77.76 128.28 ;
    END
  END i_x[302]
  PIN i_x[303]
    DIRECTION INPUT ;
    USE SIGNAL ;
    PORT
      LAYER M4 ;
        RECT  77.568 128.64 77.76 128.664 ;
    END
  END i_x[303]
  PIN i_x[304]
    DIRECTION INPUT ;
    USE SIGNAL ;
    PORT
      LAYER M4 ;
        RECT  77.568 129.024 77.76 129.048 ;
    END
  END i_x[304]
  PIN i_x[305]
    DIRECTION INPUT ;
    USE SIGNAL ;
    PORT
      LAYER M4 ;
        RECT  77.568 129.408 77.76 129.432 ;
    END
  END i_x[305]
  PIN i_x[306]
    DIRECTION INPUT ;
    USE SIGNAL ;
    PORT
      LAYER M4 ;
        RECT  77.568 129.792 77.76 129.816 ;
    END
  END i_x[306]
  PIN i_x[307]
    DIRECTION INPUT ;
    USE SIGNAL ;
    PORT
      LAYER M4 ;
        RECT  77.568 130.176 77.76 130.2 ;
    END
  END i_x[307]
  PIN i_x[308]
    DIRECTION INPUT ;
    USE SIGNAL ;
    PORT
      LAYER M4 ;
        RECT  77.568 130.56 77.76 130.584 ;
    END
  END i_x[308]
  PIN i_x[309]
    DIRECTION INPUT ;
    USE SIGNAL ;
    PORT
      LAYER M4 ;
        RECT  77.568 130.944 77.76 130.968 ;
    END
  END i_x[309]
  PIN i_x[30]
    DIRECTION INPUT ;
    USE SIGNAL ;
    PORT
      LAYER M4 ;
        RECT  77.568 23.808 77.76 23.832 ;
    END
  END i_x[30]
  PIN i_x[310]
    DIRECTION INPUT ;
    USE SIGNAL ;
    PORT
      LAYER M4 ;
        RECT  77.568 131.328 77.76 131.352 ;
    END
  END i_x[310]
  PIN i_x[311]
    DIRECTION INPUT ;
    USE SIGNAL ;
    PORT
      LAYER M4 ;
        RECT  77.568 131.712 77.76 131.736 ;
    END
  END i_x[311]
  PIN i_x[312]
    DIRECTION INPUT ;
    USE SIGNAL ;
    PORT
      LAYER M4 ;
        RECT  77.568 132.096 77.76 132.12 ;
    END
  END i_x[312]
  PIN i_x[313]
    DIRECTION INPUT ;
    USE SIGNAL ;
    PORT
      LAYER M4 ;
        RECT  77.568 132.48 77.76 132.504 ;
    END
  END i_x[313]
  PIN i_x[314]
    DIRECTION INPUT ;
    USE SIGNAL ;
    PORT
      LAYER M4 ;
        RECT  77.568 132.864 77.76 132.888 ;
    END
  END i_x[314]
  PIN i_x[315]
    DIRECTION INPUT ;
    USE SIGNAL ;
    PORT
      LAYER M4 ;
        RECT  77.568 133.248 77.76 133.272 ;
    END
  END i_x[315]
  PIN i_x[316]
    DIRECTION INPUT ;
    USE SIGNAL ;
    PORT
      LAYER M4 ;
        RECT  77.568 133.632 77.76 133.656 ;
    END
  END i_x[316]
  PIN i_x[317]
    DIRECTION INPUT ;
    USE SIGNAL ;
    PORT
      LAYER M4 ;
        RECT  77.568 134.016 77.76 134.04 ;
    END
  END i_x[317]
  PIN i_x[318]
    DIRECTION INPUT ;
    USE SIGNAL ;
    PORT
      LAYER M4 ;
        RECT  77.568 134.4 77.76 134.424 ;
    END
  END i_x[318]
  PIN i_x[319]
    DIRECTION INPUT ;
    USE SIGNAL ;
    PORT
      LAYER M4 ;
        RECT  77.568 134.784 77.76 134.808 ;
    END
  END i_x[319]
  PIN i_x[31]
    DIRECTION INPUT ;
    USE SIGNAL ;
    PORT
      LAYER M4 ;
        RECT  77.568 24.192 77.76 24.216 ;
    END
  END i_x[31]
  PIN i_x[320]
    DIRECTION INPUT ;
    USE SIGNAL ;
    PORT
      LAYER M4 ;
        RECT  77.568 135.168 77.76 135.192 ;
    END
  END i_x[320]
  PIN i_x[321]
    DIRECTION INPUT ;
    USE SIGNAL ;
    PORT
      LAYER M4 ;
        RECT  77.568 135.552 77.76 135.576 ;
    END
  END i_x[321]
  PIN i_x[322]
    DIRECTION INPUT ;
    USE SIGNAL ;
    PORT
      LAYER M4 ;
        RECT  77.568 135.936 77.76 135.96 ;
    END
  END i_x[322]
  PIN i_x[323]
    DIRECTION INPUT ;
    USE SIGNAL ;
    PORT
      LAYER M4 ;
        RECT  77.568 136.32 77.76 136.344 ;
    END
  END i_x[323]
  PIN i_x[324]
    DIRECTION INPUT ;
    USE SIGNAL ;
    PORT
      LAYER M4 ;
        RECT  77.568 136.704 77.76 136.728 ;
    END
  END i_x[324]
  PIN i_x[325]
    DIRECTION INPUT ;
    USE SIGNAL ;
    PORT
      LAYER M4 ;
        RECT  77.568 137.088 77.76 137.112 ;
    END
  END i_x[325]
  PIN i_x[326]
    DIRECTION INPUT ;
    USE SIGNAL ;
    PORT
      LAYER M4 ;
        RECT  77.568 137.472 77.76 137.496 ;
    END
  END i_x[326]
  PIN i_x[327]
    DIRECTION INPUT ;
    USE SIGNAL ;
    PORT
      LAYER M4 ;
        RECT  77.568 137.856 77.76 137.88 ;
    END
  END i_x[327]
  PIN i_x[328]
    DIRECTION INPUT ;
    USE SIGNAL ;
    PORT
      LAYER M4 ;
        RECT  77.568 138.24 77.76 138.264 ;
    END
  END i_x[328]
  PIN i_x[329]
    DIRECTION INPUT ;
    USE SIGNAL ;
    PORT
      LAYER M4 ;
        RECT  77.568 138.624 77.76 138.648 ;
    END
  END i_x[329]
  PIN i_x[32]
    DIRECTION INPUT ;
    USE SIGNAL ;
    PORT
      LAYER M4 ;
        RECT  77.568 24.576 77.76 24.6 ;
    END
  END i_x[32]
  PIN i_x[330]
    DIRECTION INPUT ;
    USE SIGNAL ;
    PORT
      LAYER M4 ;
        RECT  77.568 139.008 77.76 139.032 ;
    END
  END i_x[330]
  PIN i_x[331]
    DIRECTION INPUT ;
    USE SIGNAL ;
    PORT
      LAYER M4 ;
        RECT  77.568 139.392 77.76 139.416 ;
    END
  END i_x[331]
  PIN i_x[332]
    DIRECTION INPUT ;
    USE SIGNAL ;
    PORT
      LAYER M4 ;
        RECT  77.568 139.776 77.76 139.8 ;
    END
  END i_x[332]
  PIN i_x[333]
    DIRECTION INPUT ;
    USE SIGNAL ;
    PORT
      LAYER M4 ;
        RECT  77.568 140.16 77.76 140.184 ;
    END
  END i_x[333]
  PIN i_x[334]
    DIRECTION INPUT ;
    USE SIGNAL ;
    PORT
      LAYER M4 ;
        RECT  77.568 140.544 77.76 140.568 ;
    END
  END i_x[334]
  PIN i_x[335]
    DIRECTION INPUT ;
    USE SIGNAL ;
    PORT
      LAYER M4 ;
        RECT  77.568 140.928 77.76 140.952 ;
    END
  END i_x[335]
  PIN i_x[336]
    DIRECTION INPUT ;
    USE SIGNAL ;
    PORT
      LAYER M4 ;
        RECT  77.568 141.312 77.76 141.336 ;
    END
  END i_x[336]
  PIN i_x[337]
    DIRECTION INPUT ;
    USE SIGNAL ;
    PORT
      LAYER M4 ;
        RECT  77.568 141.696 77.76 141.72 ;
    END
  END i_x[337]
  PIN i_x[338]
    DIRECTION INPUT ;
    USE SIGNAL ;
    PORT
      LAYER M4 ;
        RECT  77.568 142.08 77.76 142.104 ;
    END
  END i_x[338]
  PIN i_x[339]
    DIRECTION INPUT ;
    USE SIGNAL ;
    PORT
      LAYER M4 ;
        RECT  77.568 142.464 77.76 142.488 ;
    END
  END i_x[339]
  PIN i_x[33]
    DIRECTION INPUT ;
    USE SIGNAL ;
    PORT
      LAYER M4 ;
        RECT  77.568 24.96 77.76 24.984 ;
    END
  END i_x[33]
  PIN i_x[340]
    DIRECTION INPUT ;
    USE SIGNAL ;
    PORT
      LAYER M4 ;
        RECT  77.568 142.848 77.76 142.872 ;
    END
  END i_x[340]
  PIN i_x[341]
    DIRECTION INPUT ;
    USE SIGNAL ;
    PORT
      LAYER M4 ;
        RECT  77.568 143.232 77.76 143.256 ;
    END
  END i_x[341]
  PIN i_x[342]
    DIRECTION INPUT ;
    USE SIGNAL ;
    PORT
      LAYER M4 ;
        RECT  77.568 143.616 77.76 143.64 ;
    END
  END i_x[342]
  PIN i_x[343]
    DIRECTION INPUT ;
    USE SIGNAL ;
    PORT
      LAYER M4 ;
        RECT  77.568 144 77.76 144.024 ;
    END
  END i_x[343]
  PIN i_x[344]
    DIRECTION INPUT ;
    USE SIGNAL ;
    PORT
      LAYER M4 ;
        RECT  77.568 144.384 77.76 144.408 ;
    END
  END i_x[344]
  PIN i_x[345]
    DIRECTION INPUT ;
    USE SIGNAL ;
    PORT
      LAYER M4 ;
        RECT  77.568 144.768 77.76 144.792 ;
    END
  END i_x[345]
  PIN i_x[346]
    DIRECTION INPUT ;
    USE SIGNAL ;
    PORT
      LAYER M4 ;
        RECT  77.568 145.152 77.76 145.176 ;
    END
  END i_x[346]
  PIN i_x[347]
    DIRECTION INPUT ;
    USE SIGNAL ;
    PORT
      LAYER M4 ;
        RECT  77.568 145.536 77.76 145.56 ;
    END
  END i_x[347]
  PIN i_x[348]
    DIRECTION INPUT ;
    USE SIGNAL ;
    PORT
      LAYER M4 ;
        RECT  77.568 145.92 77.76 145.944 ;
    END
  END i_x[348]
  PIN i_x[349]
    DIRECTION INPUT ;
    USE SIGNAL ;
    PORT
      LAYER M4 ;
        RECT  77.568 146.304 77.76 146.328 ;
    END
  END i_x[349]
  PIN i_x[34]
    DIRECTION INPUT ;
    USE SIGNAL ;
    PORT
      LAYER M4 ;
        RECT  77.568 25.344 77.76 25.368 ;
    END
  END i_x[34]
  PIN i_x[350]
    DIRECTION INPUT ;
    USE SIGNAL ;
    PORT
      LAYER M4 ;
        RECT  77.568 146.688 77.76 146.712 ;
    END
  END i_x[350]
  PIN i_x[351]
    DIRECTION INPUT ;
    USE SIGNAL ;
    PORT
      LAYER M4 ;
        RECT  77.568 147.072 77.76 147.096 ;
    END
  END i_x[351]
  PIN i_x[352]
    DIRECTION INPUT ;
    USE SIGNAL ;
    PORT
      LAYER M4 ;
        RECT  77.568 147.456 77.76 147.48 ;
    END
  END i_x[352]
  PIN i_x[353]
    DIRECTION INPUT ;
    USE SIGNAL ;
    PORT
      LAYER M4 ;
        RECT  77.568 147.84 77.76 147.864 ;
    END
  END i_x[353]
  PIN i_x[354]
    DIRECTION INPUT ;
    USE SIGNAL ;
    PORT
      LAYER M4 ;
        RECT  77.568 148.224 77.76 148.248 ;
    END
  END i_x[354]
  PIN i_x[355]
    DIRECTION INPUT ;
    USE SIGNAL ;
    PORT
      LAYER M4 ;
        RECT  77.568 148.608 77.76 148.632 ;
    END
  END i_x[355]
  PIN i_x[356]
    DIRECTION INPUT ;
    USE SIGNAL ;
    PORT
      LAYER M4 ;
        RECT  77.568 148.992 77.76 149.016 ;
    END
  END i_x[356]
  PIN i_x[357]
    DIRECTION INPUT ;
    USE SIGNAL ;
    PORT
      LAYER M4 ;
        RECT  77.568 149.376 77.76 149.4 ;
    END
  END i_x[357]
  PIN i_x[358]
    DIRECTION INPUT ;
    USE SIGNAL ;
    PORT
      LAYER M4 ;
        RECT  77.568 149.76 77.76 149.784 ;
    END
  END i_x[358]
  PIN i_x[359]
    DIRECTION INPUT ;
    USE SIGNAL ;
    PORT
      LAYER M4 ;
        RECT  77.568 150.144 77.76 150.168 ;
    END
  END i_x[359]
  PIN i_x[35]
    DIRECTION INPUT ;
    USE SIGNAL ;
    PORT
      LAYER M4 ;
        RECT  77.568 25.728 77.76 25.752 ;
    END
  END i_x[35]
  PIN i_x[360]
    DIRECTION INPUT ;
    USE SIGNAL ;
    PORT
      LAYER M4 ;
        RECT  77.568 150.528 77.76 150.552 ;
    END
  END i_x[360]
  PIN i_x[361]
    DIRECTION INPUT ;
    USE SIGNAL ;
    PORT
      LAYER M4 ;
        RECT  77.568 150.912 77.76 150.936 ;
    END
  END i_x[361]
  PIN i_x[362]
    DIRECTION INPUT ;
    USE SIGNAL ;
    PORT
      LAYER M4 ;
        RECT  77.568 151.296 77.76 151.32 ;
    END
  END i_x[362]
  PIN i_x[363]
    DIRECTION INPUT ;
    USE SIGNAL ;
    PORT
      LAYER M4 ;
        RECT  77.568 151.68 77.76 151.704 ;
    END
  END i_x[363]
  PIN i_x[364]
    DIRECTION INPUT ;
    USE SIGNAL ;
    PORT
      LAYER M4 ;
        RECT  77.568 152.064 77.76 152.088 ;
    END
  END i_x[364]
  PIN i_x[365]
    DIRECTION INPUT ;
    USE SIGNAL ;
    PORT
      LAYER M4 ;
        RECT  77.568 152.448 77.76 152.472 ;
    END
  END i_x[365]
  PIN i_x[366]
    DIRECTION INPUT ;
    USE SIGNAL ;
    PORT
      LAYER M4 ;
        RECT  77.568 152.832 77.76 152.856 ;
    END
  END i_x[366]
  PIN i_x[367]
    DIRECTION INPUT ;
    USE SIGNAL ;
    PORT
      LAYER M4 ;
        RECT  77.568 153.216 77.76 153.24 ;
    END
  END i_x[367]
  PIN i_x[368]
    DIRECTION INPUT ;
    USE SIGNAL ;
    PORT
      LAYER M4 ;
        RECT  77.568 153.6 77.76 153.624 ;
    END
  END i_x[368]
  PIN i_x[369]
    DIRECTION INPUT ;
    USE SIGNAL ;
    PORT
      LAYER M4 ;
        RECT  77.568 153.984 77.76 154.008 ;
    END
  END i_x[369]
  PIN i_x[36]
    DIRECTION INPUT ;
    USE SIGNAL ;
    PORT
      LAYER M4 ;
        RECT  77.568 26.112 77.76 26.136 ;
    END
  END i_x[36]
  PIN i_x[370]
    DIRECTION INPUT ;
    USE SIGNAL ;
    PORT
      LAYER M4 ;
        RECT  77.568 154.368 77.76 154.392 ;
    END
  END i_x[370]
  PIN i_x[371]
    DIRECTION INPUT ;
    USE SIGNAL ;
    PORT
      LAYER M4 ;
        RECT  77.568 154.752 77.76 154.776 ;
    END
  END i_x[371]
  PIN i_x[372]
    DIRECTION INPUT ;
    USE SIGNAL ;
    PORT
      LAYER M4 ;
        RECT  77.568 155.136 77.76 155.16 ;
    END
  END i_x[372]
  PIN i_x[373]
    DIRECTION INPUT ;
    USE SIGNAL ;
    PORT
      LAYER M4 ;
        RECT  77.568 155.52 77.76 155.544 ;
    END
  END i_x[373]
  PIN i_x[374]
    DIRECTION INPUT ;
    USE SIGNAL ;
    PORT
      LAYER M4 ;
        RECT  77.568 155.904 77.76 155.928 ;
    END
  END i_x[374]
  PIN i_x[375]
    DIRECTION INPUT ;
    USE SIGNAL ;
    PORT
      LAYER M4 ;
        RECT  77.568 156.288 77.76 156.312 ;
    END
  END i_x[375]
  PIN i_x[376]
    DIRECTION INPUT ;
    USE SIGNAL ;
    PORT
      LAYER M4 ;
        RECT  77.568 156.672 77.76 156.696 ;
    END
  END i_x[376]
  PIN i_x[377]
    DIRECTION INPUT ;
    USE SIGNAL ;
    PORT
      LAYER M4 ;
        RECT  77.568 157.056 77.76 157.08 ;
    END
  END i_x[377]
  PIN i_x[378]
    DIRECTION INPUT ;
    USE SIGNAL ;
    PORT
      LAYER M4 ;
        RECT  77.568 157.44 77.76 157.464 ;
    END
  END i_x[378]
  PIN i_x[379]
    DIRECTION INPUT ;
    USE SIGNAL ;
    PORT
      LAYER M4 ;
        RECT  77.568 157.824 77.76 157.848 ;
    END
  END i_x[379]
  PIN i_x[37]
    DIRECTION INPUT ;
    USE SIGNAL ;
    PORT
      LAYER M4 ;
        RECT  77.568 26.496 77.76 26.52 ;
    END
  END i_x[37]
  PIN i_x[380]
    DIRECTION INPUT ;
    USE SIGNAL ;
    PORT
      LAYER M4 ;
        RECT  77.568 158.208 77.76 158.232 ;
    END
  END i_x[380]
  PIN i_x[381]
    DIRECTION INPUT ;
    USE SIGNAL ;
    PORT
      LAYER M4 ;
        RECT  77.568 158.592 77.76 158.616 ;
    END
  END i_x[381]
  PIN i_x[382]
    DIRECTION INPUT ;
    USE SIGNAL ;
    PORT
      LAYER M4 ;
        RECT  77.568 158.976 77.76 159 ;
    END
  END i_x[382]
  PIN i_x[383]
    DIRECTION INPUT ;
    USE SIGNAL ;
    PORT
      LAYER M4 ;
        RECT  77.568 159.36 77.76 159.384 ;
    END
  END i_x[383]
  PIN i_x[384]
    DIRECTION INPUT ;
    USE SIGNAL ;
    PORT
      LAYER M4 ;
        RECT  77.568 159.744 77.76 159.768 ;
    END
  END i_x[384]
  PIN i_x[385]
    DIRECTION INPUT ;
    USE SIGNAL ;
    PORT
      LAYER M4 ;
        RECT  77.568 160.128 77.76 160.152 ;
    END
  END i_x[385]
  PIN i_x[386]
    DIRECTION INPUT ;
    USE SIGNAL ;
    PORT
      LAYER M4 ;
        RECT  77.568 160.512 77.76 160.536 ;
    END
  END i_x[386]
  PIN i_x[387]
    DIRECTION INPUT ;
    USE SIGNAL ;
    PORT
      LAYER M4 ;
        RECT  77.568 160.896 77.76 160.92 ;
    END
  END i_x[387]
  PIN i_x[388]
    DIRECTION INPUT ;
    USE SIGNAL ;
    PORT
      LAYER M4 ;
        RECT  77.568 161.28 77.76 161.304 ;
    END
  END i_x[388]
  PIN i_x[389]
    DIRECTION INPUT ;
    USE SIGNAL ;
    PORT
      LAYER M4 ;
        RECT  77.568 161.664 77.76 161.688 ;
    END
  END i_x[389]
  PIN i_x[38]
    DIRECTION INPUT ;
    USE SIGNAL ;
    PORT
      LAYER M4 ;
        RECT  77.568 26.88 77.76 26.904 ;
    END
  END i_x[38]
  PIN i_x[390]
    DIRECTION INPUT ;
    USE SIGNAL ;
    PORT
      LAYER M4 ;
        RECT  77.568 162.048 77.76 162.072 ;
    END
  END i_x[390]
  PIN i_x[391]
    DIRECTION INPUT ;
    USE SIGNAL ;
    PORT
      LAYER M4 ;
        RECT  77.568 162.432 77.76 162.456 ;
    END
  END i_x[391]
  PIN i_x[392]
    DIRECTION INPUT ;
    USE SIGNAL ;
    PORT
      LAYER M4 ;
        RECT  77.568 162.816 77.76 162.84 ;
    END
  END i_x[392]
  PIN i_x[393]
    DIRECTION INPUT ;
    USE SIGNAL ;
    PORT
      LAYER M4 ;
        RECT  77.568 163.2 77.76 163.224 ;
    END
  END i_x[393]
  PIN i_x[394]
    DIRECTION INPUT ;
    USE SIGNAL ;
    PORT
      LAYER M4 ;
        RECT  77.568 163.584 77.76 163.608 ;
    END
  END i_x[394]
  PIN i_x[395]
    DIRECTION INPUT ;
    USE SIGNAL ;
    PORT
      LAYER M4 ;
        RECT  77.568 163.968 77.76 163.992 ;
    END
  END i_x[395]
  PIN i_x[396]
    DIRECTION INPUT ;
    USE SIGNAL ;
    PORT
      LAYER M4 ;
        RECT  77.568 164.352 77.76 164.376 ;
    END
  END i_x[396]
  PIN i_x[397]
    DIRECTION INPUT ;
    USE SIGNAL ;
    PORT
      LAYER M4 ;
        RECT  77.568 164.736 77.76 164.76 ;
    END
  END i_x[397]
  PIN i_x[398]
    DIRECTION INPUT ;
    USE SIGNAL ;
    PORT
      LAYER M4 ;
        RECT  77.568 165.12 77.76 165.144 ;
    END
  END i_x[398]
  PIN i_x[399]
    DIRECTION INPUT ;
    USE SIGNAL ;
    PORT
      LAYER M4 ;
        RECT  77.568 165.504 77.76 165.528 ;
    END
  END i_x[399]
  PIN i_x[39]
    DIRECTION INPUT ;
    USE SIGNAL ;
    PORT
      LAYER M4 ;
        RECT  77.568 27.264 77.76 27.288 ;
    END
  END i_x[39]
  PIN i_x[3]
    DIRECTION INPUT ;
    USE SIGNAL ;
    PORT
      LAYER M4 ;
        RECT  77.568 13.44 77.76 13.464 ;
    END
  END i_x[3]
  PIN i_x[400]
    DIRECTION INPUT ;
    USE SIGNAL ;
    PORT
      LAYER M4 ;
        RECT  77.568 165.888 77.76 165.912 ;
    END
  END i_x[400]
  PIN i_x[401]
    DIRECTION INPUT ;
    USE SIGNAL ;
    PORT
      LAYER M4 ;
        RECT  77.568 166.272 77.76 166.296 ;
    END
  END i_x[401]
  PIN i_x[402]
    DIRECTION INPUT ;
    USE SIGNAL ;
    PORT
      LAYER M4 ;
        RECT  77.568 166.656 77.76 166.68 ;
    END
  END i_x[402]
  PIN i_x[403]
    DIRECTION INPUT ;
    USE SIGNAL ;
    PORT
      LAYER M4 ;
        RECT  77.568 167.04 77.76 167.064 ;
    END
  END i_x[403]
  PIN i_x[404]
    DIRECTION INPUT ;
    USE SIGNAL ;
    PORT
      LAYER M4 ;
        RECT  77.568 167.424 77.76 167.448 ;
    END
  END i_x[404]
  PIN i_x[405]
    DIRECTION INPUT ;
    USE SIGNAL ;
    PORT
      LAYER M4 ;
        RECT  77.568 167.808 77.76 167.832 ;
    END
  END i_x[405]
  PIN i_x[406]
    DIRECTION INPUT ;
    USE SIGNAL ;
    PORT
      LAYER M4 ;
        RECT  77.568 168.192 77.76 168.216 ;
    END
  END i_x[406]
  PIN i_x[407]
    DIRECTION INPUT ;
    USE SIGNAL ;
    PORT
      LAYER M4 ;
        RECT  77.568 168.576 77.76 168.6 ;
    END
  END i_x[407]
  PIN i_x[408]
    DIRECTION INPUT ;
    USE SIGNAL ;
    PORT
      LAYER M4 ;
        RECT  77.568 168.96 77.76 168.984 ;
    END
  END i_x[408]
  PIN i_x[409]
    DIRECTION INPUT ;
    USE SIGNAL ;
    PORT
      LAYER M4 ;
        RECT  77.568 169.344 77.76 169.368 ;
    END
  END i_x[409]
  PIN i_x[40]
    DIRECTION INPUT ;
    USE SIGNAL ;
    PORT
      LAYER M4 ;
        RECT  77.568 27.648 77.76 27.672 ;
    END
  END i_x[40]
  PIN i_x[410]
    DIRECTION INPUT ;
    USE SIGNAL ;
    PORT
      LAYER M4 ;
        RECT  77.568 169.728 77.76 169.752 ;
    END
  END i_x[410]
  PIN i_x[411]
    DIRECTION INPUT ;
    USE SIGNAL ;
    PORT
      LAYER M4 ;
        RECT  77.568 170.112 77.76 170.136 ;
    END
  END i_x[411]
  PIN i_x[412]
    DIRECTION INPUT ;
    USE SIGNAL ;
    PORT
      LAYER M4 ;
        RECT  77.568 170.496 77.76 170.52 ;
    END
  END i_x[412]
  PIN i_x[413]
    DIRECTION INPUT ;
    USE SIGNAL ;
    PORT
      LAYER M4 ;
        RECT  77.568 170.88 77.76 170.904 ;
    END
  END i_x[413]
  PIN i_x[414]
    DIRECTION INPUT ;
    USE SIGNAL ;
    PORT
      LAYER M4 ;
        RECT  77.568 171.264 77.76 171.288 ;
    END
  END i_x[414]
  PIN i_x[415]
    DIRECTION INPUT ;
    USE SIGNAL ;
    PORT
      LAYER M4 ;
        RECT  77.568 171.648 77.76 171.672 ;
    END
  END i_x[415]
  PIN i_x[416]
    DIRECTION INPUT ;
    USE SIGNAL ;
    PORT
      LAYER M4 ;
        RECT  77.568 172.032 77.76 172.056 ;
    END
  END i_x[416]
  PIN i_x[417]
    DIRECTION INPUT ;
    USE SIGNAL ;
    PORT
      LAYER M4 ;
        RECT  77.568 172.416 77.76 172.44 ;
    END
  END i_x[417]
  PIN i_x[418]
    DIRECTION INPUT ;
    USE SIGNAL ;
    PORT
      LAYER M4 ;
        RECT  77.568 172.8 77.76 172.824 ;
    END
  END i_x[418]
  PIN i_x[419]
    DIRECTION INPUT ;
    USE SIGNAL ;
    PORT
      LAYER M4 ;
        RECT  77.568 173.184 77.76 173.208 ;
    END
  END i_x[419]
  PIN i_x[41]
    DIRECTION INPUT ;
    USE SIGNAL ;
    PORT
      LAYER M4 ;
        RECT  77.568 28.032 77.76 28.056 ;
    END
  END i_x[41]
  PIN i_x[420]
    DIRECTION INPUT ;
    USE SIGNAL ;
    PORT
      LAYER M4 ;
        RECT  77.568 173.568 77.76 173.592 ;
    END
  END i_x[420]
  PIN i_x[421]
    DIRECTION INPUT ;
    USE SIGNAL ;
    PORT
      LAYER M4 ;
        RECT  77.568 173.952 77.76 173.976 ;
    END
  END i_x[421]
  PIN i_x[422]
    DIRECTION INPUT ;
    USE SIGNAL ;
    PORT
      LAYER M4 ;
        RECT  77.568 174.336 77.76 174.36 ;
    END
  END i_x[422]
  PIN i_x[423]
    DIRECTION INPUT ;
    USE SIGNAL ;
    PORT
      LAYER M4 ;
        RECT  77.568 174.72 77.76 174.744 ;
    END
  END i_x[423]
  PIN i_x[424]
    DIRECTION INPUT ;
    USE SIGNAL ;
    PORT
      LAYER M4 ;
        RECT  77.568 175.104 77.76 175.128 ;
    END
  END i_x[424]
  PIN i_x[425]
    DIRECTION INPUT ;
    USE SIGNAL ;
    PORT
      LAYER M4 ;
        RECT  77.568 175.488 77.76 175.512 ;
    END
  END i_x[425]
  PIN i_x[426]
    DIRECTION INPUT ;
    USE SIGNAL ;
    PORT
      LAYER M4 ;
        RECT  77.568 175.872 77.76 175.896 ;
    END
  END i_x[426]
  PIN i_x[427]
    DIRECTION INPUT ;
    USE SIGNAL ;
    PORT
      LAYER M4 ;
        RECT  77.568 176.256 77.76 176.28 ;
    END
  END i_x[427]
  PIN i_x[428]
    DIRECTION INPUT ;
    USE SIGNAL ;
    PORT
      LAYER M4 ;
        RECT  77.568 176.64 77.76 176.664 ;
    END
  END i_x[428]
  PIN i_x[429]
    DIRECTION INPUT ;
    USE SIGNAL ;
    PORT
      LAYER M4 ;
        RECT  77.568 177.024 77.76 177.048 ;
    END
  END i_x[429]
  PIN i_x[42]
    DIRECTION INPUT ;
    USE SIGNAL ;
    PORT
      LAYER M4 ;
        RECT  77.568 28.416 77.76 28.44 ;
    END
  END i_x[42]
  PIN i_x[430]
    DIRECTION INPUT ;
    USE SIGNAL ;
    PORT
      LAYER M4 ;
        RECT  77.568 177.408 77.76 177.432 ;
    END
  END i_x[430]
  PIN i_x[431]
    DIRECTION INPUT ;
    USE SIGNAL ;
    PORT
      LAYER M4 ;
        RECT  77.568 177.792 77.76 177.816 ;
    END
  END i_x[431]
  PIN i_x[432]
    DIRECTION INPUT ;
    USE SIGNAL ;
    PORT
      LAYER M4 ;
        RECT  77.568 178.176 77.76 178.2 ;
    END
  END i_x[432]
  PIN i_x[433]
    DIRECTION INPUT ;
    USE SIGNAL ;
    PORT
      LAYER M4 ;
        RECT  77.568 178.56 77.76 178.584 ;
    END
  END i_x[433]
  PIN i_x[434]
    DIRECTION INPUT ;
    USE SIGNAL ;
    PORT
      LAYER M4 ;
        RECT  77.568 178.944 77.76 178.968 ;
    END
  END i_x[434]
  PIN i_x[435]
    DIRECTION INPUT ;
    USE SIGNAL ;
    PORT
      LAYER M4 ;
        RECT  77.568 179.328 77.76 179.352 ;
    END
  END i_x[435]
  PIN i_x[436]
    DIRECTION INPUT ;
    USE SIGNAL ;
    PORT
      LAYER M4 ;
        RECT  77.568 179.712 77.76 179.736 ;
    END
  END i_x[436]
  PIN i_x[437]
    DIRECTION INPUT ;
    USE SIGNAL ;
    PORT
      LAYER M4 ;
        RECT  77.568 180.096 77.76 180.12 ;
    END
  END i_x[437]
  PIN i_x[438]
    DIRECTION INPUT ;
    USE SIGNAL ;
    PORT
      LAYER M4 ;
        RECT  77.568 180.48 77.76 180.504 ;
    END
  END i_x[438]
  PIN i_x[439]
    DIRECTION INPUT ;
    USE SIGNAL ;
    PORT
      LAYER M4 ;
        RECT  77.568 180.864 77.76 180.888 ;
    END
  END i_x[439]
  PIN i_x[43]
    DIRECTION INPUT ;
    USE SIGNAL ;
    PORT
      LAYER M4 ;
        RECT  77.568 28.8 77.76 28.824 ;
    END
  END i_x[43]
  PIN i_x[440]
    DIRECTION INPUT ;
    USE SIGNAL ;
    PORT
      LAYER M4 ;
        RECT  77.568 181.248 77.76 181.272 ;
    END
  END i_x[440]
  PIN i_x[441]
    DIRECTION INPUT ;
    USE SIGNAL ;
    PORT
      LAYER M4 ;
        RECT  77.568 181.632 77.76 181.656 ;
    END
  END i_x[441]
  PIN i_x[442]
    DIRECTION INPUT ;
    USE SIGNAL ;
    PORT
      LAYER M4 ;
        RECT  77.568 182.016 77.76 182.04 ;
    END
  END i_x[442]
  PIN i_x[443]
    DIRECTION INPUT ;
    USE SIGNAL ;
    PORT
      LAYER M4 ;
        RECT  77.568 182.4 77.76 182.424 ;
    END
  END i_x[443]
  PIN i_x[444]
    DIRECTION INPUT ;
    USE SIGNAL ;
    PORT
      LAYER M4 ;
        RECT  77.568 182.784 77.76 182.808 ;
    END
  END i_x[444]
  PIN i_x[445]
    DIRECTION INPUT ;
    USE SIGNAL ;
    PORT
      LAYER M4 ;
        RECT  77.568 183.168 77.76 183.192 ;
    END
  END i_x[445]
  PIN i_x[446]
    DIRECTION INPUT ;
    USE SIGNAL ;
    PORT
      LAYER M4 ;
        RECT  77.568 183.552 77.76 183.576 ;
    END
  END i_x[446]
  PIN i_x[447]
    DIRECTION INPUT ;
    USE SIGNAL ;
    PORT
      LAYER M4 ;
        RECT  77.568 183.936 77.76 183.96 ;
    END
  END i_x[447]
  PIN i_x[448]
    DIRECTION INPUT ;
    USE SIGNAL ;
    PORT
      LAYER M4 ;
        RECT  77.568 184.32 77.76 184.344 ;
    END
  END i_x[448]
  PIN i_x[449]
    DIRECTION INPUT ;
    USE SIGNAL ;
    PORT
      LAYER M4 ;
        RECT  77.568 184.704 77.76 184.728 ;
    END
  END i_x[449]
  PIN i_x[44]
    DIRECTION INPUT ;
    USE SIGNAL ;
    PORT
      LAYER M4 ;
        RECT  77.568 29.184 77.76 29.208 ;
    END
  END i_x[44]
  PIN i_x[450]
    DIRECTION INPUT ;
    USE SIGNAL ;
    PORT
      LAYER M4 ;
        RECT  77.568 185.088 77.76 185.112 ;
    END
  END i_x[450]
  PIN i_x[451]
    DIRECTION INPUT ;
    USE SIGNAL ;
    PORT
      LAYER M4 ;
        RECT  77.568 185.472 77.76 185.496 ;
    END
  END i_x[451]
  PIN i_x[452]
    DIRECTION INPUT ;
    USE SIGNAL ;
    PORT
      LAYER M4 ;
        RECT  77.568 185.856 77.76 185.88 ;
    END
  END i_x[452]
  PIN i_x[453]
    DIRECTION INPUT ;
    USE SIGNAL ;
    PORT
      LAYER M4 ;
        RECT  77.568 186.24 77.76 186.264 ;
    END
  END i_x[453]
  PIN i_x[454]
    DIRECTION INPUT ;
    USE SIGNAL ;
    PORT
      LAYER M4 ;
        RECT  77.568 186.624 77.76 186.648 ;
    END
  END i_x[454]
  PIN i_x[455]
    DIRECTION INPUT ;
    USE SIGNAL ;
    PORT
      LAYER M4 ;
        RECT  77.568 187.008 77.76 187.032 ;
    END
  END i_x[455]
  PIN i_x[456]
    DIRECTION INPUT ;
    USE SIGNAL ;
    PORT
      LAYER M4 ;
        RECT  77.568 187.392 77.76 187.416 ;
    END
  END i_x[456]
  PIN i_x[457]
    DIRECTION INPUT ;
    USE SIGNAL ;
    PORT
      LAYER M4 ;
        RECT  77.568 187.776 77.76 187.8 ;
    END
  END i_x[457]
  PIN i_x[458]
    DIRECTION INPUT ;
    USE SIGNAL ;
    PORT
      LAYER M4 ;
        RECT  77.568 188.16 77.76 188.184 ;
    END
  END i_x[458]
  PIN i_x[459]
    DIRECTION INPUT ;
    USE SIGNAL ;
    PORT
      LAYER M4 ;
        RECT  77.568 188.544 77.76 188.568 ;
    END
  END i_x[459]
  PIN i_x[45]
    DIRECTION INPUT ;
    USE SIGNAL ;
    PORT
      LAYER M4 ;
        RECT  77.568 29.568 77.76 29.592 ;
    END
  END i_x[45]
  PIN i_x[460]
    DIRECTION INPUT ;
    USE SIGNAL ;
    PORT
      LAYER M4 ;
        RECT  77.568 188.928 77.76 188.952 ;
    END
  END i_x[460]
  PIN i_x[461]
    DIRECTION INPUT ;
    USE SIGNAL ;
    PORT
      LAYER M4 ;
        RECT  77.568 189.312 77.76 189.336 ;
    END
  END i_x[461]
  PIN i_x[462]
    DIRECTION INPUT ;
    USE SIGNAL ;
    PORT
      LAYER M4 ;
        RECT  77.568 189.696 77.76 189.72 ;
    END
  END i_x[462]
  PIN i_x[463]
    DIRECTION INPUT ;
    USE SIGNAL ;
    PORT
      LAYER M4 ;
        RECT  77.568 190.08 77.76 190.104 ;
    END
  END i_x[463]
  PIN i_x[464]
    DIRECTION INPUT ;
    USE SIGNAL ;
    PORT
      LAYER M4 ;
        RECT  77.568 190.464 77.76 190.488 ;
    END
  END i_x[464]
  PIN i_x[465]
    DIRECTION INPUT ;
    USE SIGNAL ;
    PORT
      LAYER M4 ;
        RECT  77.568 190.848 77.76 190.872 ;
    END
  END i_x[465]
  PIN i_x[466]
    DIRECTION INPUT ;
    USE SIGNAL ;
    PORT
      LAYER M4 ;
        RECT  77.568 191.232 77.76 191.256 ;
    END
  END i_x[466]
  PIN i_x[467]
    DIRECTION INPUT ;
    USE SIGNAL ;
    PORT
      LAYER M4 ;
        RECT  77.568 191.616 77.76 191.64 ;
    END
  END i_x[467]
  PIN i_x[468]
    DIRECTION INPUT ;
    USE SIGNAL ;
    PORT
      LAYER M4 ;
        RECT  77.568 192 77.76 192.024 ;
    END
  END i_x[468]
  PIN i_x[469]
    DIRECTION INPUT ;
    USE SIGNAL ;
    PORT
      LAYER M4 ;
        RECT  77.568 192.384 77.76 192.408 ;
    END
  END i_x[469]
  PIN i_x[46]
    DIRECTION INPUT ;
    USE SIGNAL ;
    PORT
      LAYER M4 ;
        RECT  77.568 29.952 77.76 29.976 ;
    END
  END i_x[46]
  PIN i_x[470]
    DIRECTION INPUT ;
    USE SIGNAL ;
    PORT
      LAYER M4 ;
        RECT  77.568 192.768 77.76 192.792 ;
    END
  END i_x[470]
  PIN i_x[471]
    DIRECTION INPUT ;
    USE SIGNAL ;
    PORT
      LAYER M4 ;
        RECT  77.568 193.152 77.76 193.176 ;
    END
  END i_x[471]
  PIN i_x[472]
    DIRECTION INPUT ;
    USE SIGNAL ;
    PORT
      LAYER M4 ;
        RECT  77.568 193.536 77.76 193.56 ;
    END
  END i_x[472]
  PIN i_x[473]
    DIRECTION INPUT ;
    USE SIGNAL ;
    PORT
      LAYER M4 ;
        RECT  77.568 193.92 77.76 193.944 ;
    END
  END i_x[473]
  PIN i_x[474]
    DIRECTION INPUT ;
    USE SIGNAL ;
    PORT
      LAYER M4 ;
        RECT  77.568 194.304 77.76 194.328 ;
    END
  END i_x[474]
  PIN i_x[475]
    DIRECTION INPUT ;
    USE SIGNAL ;
    PORT
      LAYER M4 ;
        RECT  77.568 194.688 77.76 194.712 ;
    END
  END i_x[475]
  PIN i_x[476]
    DIRECTION INPUT ;
    USE SIGNAL ;
    PORT
      LAYER M4 ;
        RECT  77.568 195.072 77.76 195.096 ;
    END
  END i_x[476]
  PIN i_x[477]
    DIRECTION INPUT ;
    USE SIGNAL ;
    PORT
      LAYER M4 ;
        RECT  77.568 195.456 77.76 195.48 ;
    END
  END i_x[477]
  PIN i_x[478]
    DIRECTION INPUT ;
    USE SIGNAL ;
    PORT
      LAYER M4 ;
        RECT  77.568 195.84 77.76 195.864 ;
    END
  END i_x[478]
  PIN i_x[479]
    DIRECTION INPUT ;
    USE SIGNAL ;
    PORT
      LAYER M4 ;
        RECT  77.568 196.224 77.76 196.248 ;
    END
  END i_x[479]
  PIN i_x[47]
    DIRECTION INPUT ;
    USE SIGNAL ;
    PORT
      LAYER M4 ;
        RECT  77.568 30.336 77.76 30.36 ;
    END
  END i_x[47]
  PIN i_x[480]
    DIRECTION INPUT ;
    USE SIGNAL ;
    PORT
      LAYER M4 ;
        RECT  77.568 196.608 77.76 196.632 ;
    END
  END i_x[480]
  PIN i_x[481]
    DIRECTION INPUT ;
    USE SIGNAL ;
    PORT
      LAYER M4 ;
        RECT  77.568 196.992 77.76 197.016 ;
    END
  END i_x[481]
  PIN i_x[482]
    DIRECTION INPUT ;
    USE SIGNAL ;
    PORT
      LAYER M4 ;
        RECT  77.568 197.376 77.76 197.4 ;
    END
  END i_x[482]
  PIN i_x[483]
    DIRECTION INPUT ;
    USE SIGNAL ;
    PORT
      LAYER M4 ;
        RECT  77.568 197.76 77.76 197.784 ;
    END
  END i_x[483]
  PIN i_x[484]
    DIRECTION INPUT ;
    USE SIGNAL ;
    PORT
      LAYER M4 ;
        RECT  77.568 198.144 77.76 198.168 ;
    END
  END i_x[484]
  PIN i_x[485]
    DIRECTION INPUT ;
    USE SIGNAL ;
    PORT
      LAYER M4 ;
        RECT  77.568 198.528 77.76 198.552 ;
    END
  END i_x[485]
  PIN i_x[486]
    DIRECTION INPUT ;
    USE SIGNAL ;
    PORT
      LAYER M4 ;
        RECT  77.568 198.912 77.76 198.936 ;
    END
  END i_x[486]
  PIN i_x[487]
    DIRECTION INPUT ;
    USE SIGNAL ;
    PORT
      LAYER M4 ;
        RECT  77.568 199.296 77.76 199.32 ;
    END
  END i_x[487]
  PIN i_x[488]
    DIRECTION INPUT ;
    USE SIGNAL ;
    PORT
      LAYER M4 ;
        RECT  77.568 199.68 77.76 199.704 ;
    END
  END i_x[488]
  PIN i_x[489]
    DIRECTION INPUT ;
    USE SIGNAL ;
    PORT
      LAYER M4 ;
        RECT  77.568 200.064 77.76 200.088 ;
    END
  END i_x[489]
  PIN i_x[48]
    DIRECTION INPUT ;
    USE SIGNAL ;
    PORT
      LAYER M4 ;
        RECT  77.568 30.72 77.76 30.744 ;
    END
  END i_x[48]
  PIN i_x[490]
    DIRECTION INPUT ;
    USE SIGNAL ;
    PORT
      LAYER M4 ;
        RECT  77.568 200.448 77.76 200.472 ;
    END
  END i_x[490]
  PIN i_x[491]
    DIRECTION INPUT ;
    USE SIGNAL ;
    PORT
      LAYER M4 ;
        RECT  77.568 200.832 77.76 200.856 ;
    END
  END i_x[491]
  PIN i_x[492]
    DIRECTION INPUT ;
    USE SIGNAL ;
    PORT
      LAYER M4 ;
        RECT  77.568 201.216 77.76 201.24 ;
    END
  END i_x[492]
  PIN i_x[493]
    DIRECTION INPUT ;
    USE SIGNAL ;
    PORT
      LAYER M4 ;
        RECT  77.568 201.6 77.76 201.624 ;
    END
  END i_x[493]
  PIN i_x[494]
    DIRECTION INPUT ;
    USE SIGNAL ;
    PORT
      LAYER M4 ;
        RECT  77.568 201.984 77.76 202.008 ;
    END
  END i_x[494]
  PIN i_x[495]
    DIRECTION INPUT ;
    USE SIGNAL ;
    PORT
      LAYER M4 ;
        RECT  77.568 202.368 77.76 202.392 ;
    END
  END i_x[495]
  PIN i_x[496]
    DIRECTION INPUT ;
    USE SIGNAL ;
    PORT
      LAYER M4 ;
        RECT  77.568 202.752 77.76 202.776 ;
    END
  END i_x[496]
  PIN i_x[497]
    DIRECTION INPUT ;
    USE SIGNAL ;
    PORT
      LAYER M4 ;
        RECT  77.568 203.136 77.76 203.16 ;
    END
  END i_x[497]
  PIN i_x[498]
    DIRECTION INPUT ;
    USE SIGNAL ;
    PORT
      LAYER M4 ;
        RECT  77.568 203.52 77.76 203.544 ;
    END
  END i_x[498]
  PIN i_x[499]
    DIRECTION INPUT ;
    USE SIGNAL ;
    PORT
      LAYER M4 ;
        RECT  77.568 203.904 77.76 203.928 ;
    END
  END i_x[499]
  PIN i_x[49]
    DIRECTION INPUT ;
    USE SIGNAL ;
    PORT
      LAYER M4 ;
        RECT  77.568 31.104 77.76 31.128 ;
    END
  END i_x[49]
  PIN i_x[4]
    DIRECTION INPUT ;
    USE SIGNAL ;
    PORT
      LAYER M4 ;
        RECT  77.568 13.824 77.76 13.848 ;
    END
  END i_x[4]
  PIN i_x[500]
    DIRECTION INPUT ;
    USE SIGNAL ;
    PORT
      LAYER M4 ;
        RECT  77.568 204.288 77.76 204.312 ;
    END
  END i_x[500]
  PIN i_x[501]
    DIRECTION INPUT ;
    USE SIGNAL ;
    PORT
      LAYER M4 ;
        RECT  77.568 204.672 77.76 204.696 ;
    END
  END i_x[501]
  PIN i_x[502]
    DIRECTION INPUT ;
    USE SIGNAL ;
    PORT
      LAYER M4 ;
        RECT  77.568 205.056 77.76 205.08 ;
    END
  END i_x[502]
  PIN i_x[503]
    DIRECTION INPUT ;
    USE SIGNAL ;
    PORT
      LAYER M4 ;
        RECT  77.568 205.44 77.76 205.464 ;
    END
  END i_x[503]
  PIN i_x[504]
    DIRECTION INPUT ;
    USE SIGNAL ;
    PORT
      LAYER M4 ;
        RECT  77.568 205.824 77.76 205.848 ;
    END
  END i_x[504]
  PIN i_x[505]
    DIRECTION INPUT ;
    USE SIGNAL ;
    PORT
      LAYER M4 ;
        RECT  77.568 206.208 77.76 206.232 ;
    END
  END i_x[505]
  PIN i_x[506]
    DIRECTION INPUT ;
    USE SIGNAL ;
    PORT
      LAYER M4 ;
        RECT  77.568 206.592 77.76 206.616 ;
    END
  END i_x[506]
  PIN i_x[507]
    DIRECTION INPUT ;
    USE SIGNAL ;
    PORT
      LAYER M4 ;
        RECT  77.568 206.976 77.76 207 ;
    END
  END i_x[507]
  PIN i_x[508]
    DIRECTION INPUT ;
    USE SIGNAL ;
    PORT
      LAYER M4 ;
        RECT  77.568 207.36 77.76 207.384 ;
    END
  END i_x[508]
  PIN i_x[509]
    DIRECTION INPUT ;
    USE SIGNAL ;
    PORT
      LAYER M4 ;
        RECT  77.568 207.744 77.76 207.768 ;
    END
  END i_x[509]
  PIN i_x[50]
    DIRECTION INPUT ;
    USE SIGNAL ;
    PORT
      LAYER M4 ;
        RECT  77.568 31.488 77.76 31.512 ;
    END
  END i_x[50]
  PIN i_x[510]
    DIRECTION INPUT ;
    USE SIGNAL ;
    PORT
      LAYER M4 ;
        RECT  77.568 208.128 77.76 208.152 ;
    END
  END i_x[510]
  PIN i_x[511]
    DIRECTION INPUT ;
    USE SIGNAL ;
    PORT
      LAYER M4 ;
        RECT  77.568 208.512 77.76 208.536 ;
    END
  END i_x[511]
  PIN i_x[512]
    DIRECTION INPUT ;
    USE SIGNAL ;
    PORT
      LAYER M4 ;
        RECT  77.568 208.896 77.76 208.92 ;
    END
  END i_x[512]
  PIN i_x[513]
    DIRECTION INPUT ;
    USE SIGNAL ;
    PORT
      LAYER M4 ;
        RECT  77.568 209.28 77.76 209.304 ;
    END
  END i_x[513]
  PIN i_x[514]
    DIRECTION INPUT ;
    USE SIGNAL ;
    PORT
      LAYER M4 ;
        RECT  77.568 209.664 77.76 209.688 ;
    END
  END i_x[514]
  PIN i_x[515]
    DIRECTION INPUT ;
    USE SIGNAL ;
    PORT
      LAYER M4 ;
        RECT  77.568 210.048 77.76 210.072 ;
    END
  END i_x[515]
  PIN i_x[516]
    DIRECTION INPUT ;
    USE SIGNAL ;
    PORT
      LAYER M4 ;
        RECT  77.568 210.432 77.76 210.456 ;
    END
  END i_x[516]
  PIN i_x[517]
    DIRECTION INPUT ;
    USE SIGNAL ;
    PORT
      LAYER M4 ;
        RECT  77.568 210.816 77.76 210.84 ;
    END
  END i_x[517]
  PIN i_x[518]
    DIRECTION INPUT ;
    USE SIGNAL ;
    PORT
      LAYER M4 ;
        RECT  77.568 211.2 77.76 211.224 ;
    END
  END i_x[518]
  PIN i_x[519]
    DIRECTION INPUT ;
    USE SIGNAL ;
    PORT
      LAYER M4 ;
        RECT  77.568 211.584 77.76 211.608 ;
    END
  END i_x[519]
  PIN i_x[51]
    DIRECTION INPUT ;
    USE SIGNAL ;
    PORT
      LAYER M4 ;
        RECT  77.568 31.872 77.76 31.896 ;
    END
  END i_x[51]
  PIN i_x[520]
    DIRECTION INPUT ;
    USE SIGNAL ;
    PORT
      LAYER M4 ;
        RECT  77.568 211.968 77.76 211.992 ;
    END
  END i_x[520]
  PIN i_x[521]
    DIRECTION INPUT ;
    USE SIGNAL ;
    PORT
      LAYER M4 ;
        RECT  77.568 212.352 77.76 212.376 ;
    END
  END i_x[521]
  PIN i_x[522]
    DIRECTION INPUT ;
    USE SIGNAL ;
    PORT
      LAYER M4 ;
        RECT  77.568 212.736 77.76 212.76 ;
    END
  END i_x[522]
  PIN i_x[523]
    DIRECTION INPUT ;
    USE SIGNAL ;
    PORT
      LAYER M4 ;
        RECT  77.568 213.12 77.76 213.144 ;
    END
  END i_x[523]
  PIN i_x[524]
    DIRECTION INPUT ;
    USE SIGNAL ;
    PORT
      LAYER M4 ;
        RECT  77.568 213.504 77.76 213.528 ;
    END
  END i_x[524]
  PIN i_x[525]
    DIRECTION INPUT ;
    USE SIGNAL ;
    PORT
      LAYER M4 ;
        RECT  77.568 213.888 77.76 213.912 ;
    END
  END i_x[525]
  PIN i_x[526]
    DIRECTION INPUT ;
    USE SIGNAL ;
    PORT
      LAYER M4 ;
        RECT  77.568 214.272 77.76 214.296 ;
    END
  END i_x[526]
  PIN i_x[527]
    DIRECTION INPUT ;
    USE SIGNAL ;
    PORT
      LAYER M4 ;
        RECT  77.568 214.656 77.76 214.68 ;
    END
  END i_x[527]
  PIN i_x[528]
    DIRECTION INPUT ;
    USE SIGNAL ;
    PORT
      LAYER M4 ;
        RECT  77.568 215.04 77.76 215.064 ;
    END
  END i_x[528]
  PIN i_x[529]
    DIRECTION INPUT ;
    USE SIGNAL ;
    PORT
      LAYER M4 ;
        RECT  77.568 215.424 77.76 215.448 ;
    END
  END i_x[529]
  PIN i_x[52]
    DIRECTION INPUT ;
    USE SIGNAL ;
    PORT
      LAYER M4 ;
        RECT  77.568 32.256 77.76 32.28 ;
    END
  END i_x[52]
  PIN i_x[530]
    DIRECTION INPUT ;
    USE SIGNAL ;
    PORT
      LAYER M4 ;
        RECT  77.568 215.808 77.76 215.832 ;
    END
  END i_x[530]
  PIN i_x[531]
    DIRECTION INPUT ;
    USE SIGNAL ;
    PORT
      LAYER M4 ;
        RECT  77.568 216.192 77.76 216.216 ;
    END
  END i_x[531]
  PIN i_x[53]
    DIRECTION INPUT ;
    USE SIGNAL ;
    PORT
      LAYER M4 ;
        RECT  77.568 32.64 77.76 32.664 ;
    END
  END i_x[53]
  PIN i_x[54]
    DIRECTION INPUT ;
    USE SIGNAL ;
    PORT
      LAYER M4 ;
        RECT  77.568 33.024 77.76 33.048 ;
    END
  END i_x[54]
  PIN i_x[55]
    DIRECTION INPUT ;
    USE SIGNAL ;
    PORT
      LAYER M4 ;
        RECT  77.568 33.408 77.76 33.432 ;
    END
  END i_x[55]
  PIN i_x[56]
    DIRECTION INPUT ;
    USE SIGNAL ;
    PORT
      LAYER M4 ;
        RECT  77.568 33.792 77.76 33.816 ;
    END
  END i_x[56]
  PIN i_x[57]
    DIRECTION INPUT ;
    USE SIGNAL ;
    PORT
      LAYER M4 ;
        RECT  77.568 34.176 77.76 34.2 ;
    END
  END i_x[57]
  PIN i_x[58]
    DIRECTION INPUT ;
    USE SIGNAL ;
    PORT
      LAYER M4 ;
        RECT  77.568 34.56 77.76 34.584 ;
    END
  END i_x[58]
  PIN i_x[59]
    DIRECTION INPUT ;
    USE SIGNAL ;
    PORT
      LAYER M4 ;
        RECT  77.568 34.944 77.76 34.968 ;
    END
  END i_x[59]
  PIN i_x[5]
    DIRECTION INPUT ;
    USE SIGNAL ;
    PORT
      LAYER M4 ;
        RECT  77.568 14.208 77.76 14.232 ;
    END
  END i_x[5]
  PIN i_x[60]
    DIRECTION INPUT ;
    USE SIGNAL ;
    PORT
      LAYER M4 ;
        RECT  77.568 35.328 77.76 35.352 ;
    END
  END i_x[60]
  PIN i_x[61]
    DIRECTION INPUT ;
    USE SIGNAL ;
    PORT
      LAYER M4 ;
        RECT  77.568 35.712 77.76 35.736 ;
    END
  END i_x[61]
  PIN i_x[62]
    DIRECTION INPUT ;
    USE SIGNAL ;
    PORT
      LAYER M4 ;
        RECT  77.568 36.096 77.76 36.12 ;
    END
  END i_x[62]
  PIN i_x[63]
    DIRECTION INPUT ;
    USE SIGNAL ;
    PORT
      LAYER M4 ;
        RECT  77.568 36.48 77.76 36.504 ;
    END
  END i_x[63]
  PIN i_x[64]
    DIRECTION INPUT ;
    USE SIGNAL ;
    PORT
      LAYER M4 ;
        RECT  77.568 36.864 77.76 36.888 ;
    END
  END i_x[64]
  PIN i_x[65]
    DIRECTION INPUT ;
    USE SIGNAL ;
    PORT
      LAYER M4 ;
        RECT  77.568 37.248 77.76 37.272 ;
    END
  END i_x[65]
  PIN i_x[66]
    DIRECTION INPUT ;
    USE SIGNAL ;
    PORT
      LAYER M4 ;
        RECT  77.568 37.632 77.76 37.656 ;
    END
  END i_x[66]
  PIN i_x[67]
    DIRECTION INPUT ;
    USE SIGNAL ;
    PORT
      LAYER M4 ;
        RECT  77.568 38.016 77.76 38.04 ;
    END
  END i_x[67]
  PIN i_x[68]
    DIRECTION INPUT ;
    USE SIGNAL ;
    PORT
      LAYER M4 ;
        RECT  77.568 38.4 77.76 38.424 ;
    END
  END i_x[68]
  PIN i_x[69]
    DIRECTION INPUT ;
    USE SIGNAL ;
    PORT
      LAYER M4 ;
        RECT  77.568 38.784 77.76 38.808 ;
    END
  END i_x[69]
  PIN i_x[6]
    DIRECTION INPUT ;
    USE SIGNAL ;
    PORT
      LAYER M4 ;
        RECT  77.568 14.592 77.76 14.616 ;
    END
  END i_x[6]
  PIN i_x[70]
    DIRECTION INPUT ;
    USE SIGNAL ;
    PORT
      LAYER M4 ;
        RECT  77.568 39.168 77.76 39.192 ;
    END
  END i_x[70]
  PIN i_x[71]
    DIRECTION INPUT ;
    USE SIGNAL ;
    PORT
      LAYER M4 ;
        RECT  77.568 39.552 77.76 39.576 ;
    END
  END i_x[71]
  PIN i_x[72]
    DIRECTION INPUT ;
    USE SIGNAL ;
    PORT
      LAYER M4 ;
        RECT  77.568 39.936 77.76 39.96 ;
    END
  END i_x[72]
  PIN i_x[73]
    DIRECTION INPUT ;
    USE SIGNAL ;
    PORT
      LAYER M4 ;
        RECT  77.568 40.32 77.76 40.344 ;
    END
  END i_x[73]
  PIN i_x[74]
    DIRECTION INPUT ;
    USE SIGNAL ;
    PORT
      LAYER M4 ;
        RECT  77.568 40.704 77.76 40.728 ;
    END
  END i_x[74]
  PIN i_x[75]
    DIRECTION INPUT ;
    USE SIGNAL ;
    PORT
      LAYER M4 ;
        RECT  77.568 41.088 77.76 41.112 ;
    END
  END i_x[75]
  PIN i_x[76]
    DIRECTION INPUT ;
    USE SIGNAL ;
    PORT
      LAYER M4 ;
        RECT  77.568 41.472 77.76 41.496 ;
    END
  END i_x[76]
  PIN i_x[77]
    DIRECTION INPUT ;
    USE SIGNAL ;
    PORT
      LAYER M4 ;
        RECT  77.568 41.856 77.76 41.88 ;
    END
  END i_x[77]
  PIN i_x[78]
    DIRECTION INPUT ;
    USE SIGNAL ;
    PORT
      LAYER M4 ;
        RECT  77.568 42.24 77.76 42.264 ;
    END
  END i_x[78]
  PIN i_x[79]
    DIRECTION INPUT ;
    USE SIGNAL ;
    PORT
      LAYER M4 ;
        RECT  77.568 42.624 77.76 42.648 ;
    END
  END i_x[79]
  PIN i_x[7]
    DIRECTION INPUT ;
    USE SIGNAL ;
    PORT
      LAYER M4 ;
        RECT  77.568 14.976 77.76 15 ;
    END
  END i_x[7]
  PIN i_x[80]
    DIRECTION INPUT ;
    USE SIGNAL ;
    PORT
      LAYER M4 ;
        RECT  77.568 43.008 77.76 43.032 ;
    END
  END i_x[80]
  PIN i_x[81]
    DIRECTION INPUT ;
    USE SIGNAL ;
    PORT
      LAYER M4 ;
        RECT  77.568 43.392 77.76 43.416 ;
    END
  END i_x[81]
  PIN i_x[82]
    DIRECTION INPUT ;
    USE SIGNAL ;
    PORT
      LAYER M4 ;
        RECT  77.568 43.776 77.76 43.8 ;
    END
  END i_x[82]
  PIN i_x[83]
    DIRECTION INPUT ;
    USE SIGNAL ;
    PORT
      LAYER M4 ;
        RECT  77.568 44.16 77.76 44.184 ;
    END
  END i_x[83]
  PIN i_x[84]
    DIRECTION INPUT ;
    USE SIGNAL ;
    PORT
      LAYER M4 ;
        RECT  77.568 44.544 77.76 44.568 ;
    END
  END i_x[84]
  PIN i_x[85]
    DIRECTION INPUT ;
    USE SIGNAL ;
    PORT
      LAYER M4 ;
        RECT  77.568 44.928 77.76 44.952 ;
    END
  END i_x[85]
  PIN i_x[86]
    DIRECTION INPUT ;
    USE SIGNAL ;
    PORT
      LAYER M4 ;
        RECT  77.568 45.312 77.76 45.336 ;
    END
  END i_x[86]
  PIN i_x[87]
    DIRECTION INPUT ;
    USE SIGNAL ;
    PORT
      LAYER M4 ;
        RECT  77.568 45.696 77.76 45.72 ;
    END
  END i_x[87]
  PIN i_x[88]
    DIRECTION INPUT ;
    USE SIGNAL ;
    PORT
      LAYER M4 ;
        RECT  77.568 46.08 77.76 46.104 ;
    END
  END i_x[88]
  PIN i_x[89]
    DIRECTION INPUT ;
    USE SIGNAL ;
    PORT
      LAYER M4 ;
        RECT  77.568 46.464 77.76 46.488 ;
    END
  END i_x[89]
  PIN i_x[8]
    DIRECTION INPUT ;
    USE SIGNAL ;
    PORT
      LAYER M4 ;
        RECT  77.568 15.36 77.76 15.384 ;
    END
  END i_x[8]
  PIN i_x[90]
    DIRECTION INPUT ;
    USE SIGNAL ;
    PORT
      LAYER M4 ;
        RECT  77.568 46.848 77.76 46.872 ;
    END
  END i_x[90]
  PIN i_x[91]
    DIRECTION INPUT ;
    USE SIGNAL ;
    PORT
      LAYER M4 ;
        RECT  77.568 47.232 77.76 47.256 ;
    END
  END i_x[91]
  PIN i_x[92]
    DIRECTION INPUT ;
    USE SIGNAL ;
    PORT
      LAYER M4 ;
        RECT  77.568 47.616 77.76 47.64 ;
    END
  END i_x[92]
  PIN i_x[93]
    DIRECTION INPUT ;
    USE SIGNAL ;
    PORT
      LAYER M4 ;
        RECT  77.568 48 77.76 48.024 ;
    END
  END i_x[93]
  PIN i_x[94]
    DIRECTION INPUT ;
    USE SIGNAL ;
    PORT
      LAYER M4 ;
        RECT  77.568 48.384 77.76 48.408 ;
    END
  END i_x[94]
  PIN i_x[95]
    DIRECTION INPUT ;
    USE SIGNAL ;
    PORT
      LAYER M4 ;
        RECT  77.568 48.768 77.76 48.792 ;
    END
  END i_x[95]
  PIN i_x[96]
    DIRECTION INPUT ;
    USE SIGNAL ;
    PORT
      LAYER M4 ;
        RECT  77.568 49.152 77.76 49.176 ;
    END
  END i_x[96]
  PIN i_x[97]
    DIRECTION INPUT ;
    USE SIGNAL ;
    PORT
      LAYER M4 ;
        RECT  77.568 49.536 77.76 49.56 ;
    END
  END i_x[97]
  PIN i_x[98]
    DIRECTION INPUT ;
    USE SIGNAL ;
    PORT
      LAYER M4 ;
        RECT  77.568 49.92 77.76 49.944 ;
    END
  END i_x[98]
  PIN i_x[99]
    DIRECTION INPUT ;
    USE SIGNAL ;
    PORT
      LAYER M4 ;
        RECT  77.568 50.304 77.76 50.328 ;
    END
  END i_x[99]
  PIN i_x[9]
    DIRECTION INPUT ;
    USE SIGNAL ;
    PORT
      LAYER M4 ;
        RECT  77.568 15.744 77.76 15.768 ;
    END
  END i_x[9]
  PIN otag[0]
    DIRECTION OUTPUT ;
    USE SIGNAL ;
    PORT
      LAYER M4 ;
        RECT  0 114.048 0.192 114.072 ;
    END
  END otag[0]
  PIN otag[10]
    DIRECTION OUTPUT ;
    USE SIGNAL ;
    PORT
      LAYER M4 ;
        RECT  0 115.968 0.192 115.992 ;
    END
  END otag[10]
  PIN otag[11]
    DIRECTION OUTPUT ;
    USE SIGNAL ;
    PORT
      LAYER M4 ;
        RECT  0 116.16 0.192 116.184 ;
    END
  END otag[11]
  PIN otag[12]
    DIRECTION OUTPUT ;
    USE SIGNAL ;
    PORT
      LAYER M4 ;
        RECT  0 116.352 0.192 116.376 ;
    END
  END otag[12]
  PIN otag[13]
    DIRECTION OUTPUT ;
    USE SIGNAL ;
    PORT
      LAYER M4 ;
        RECT  0 116.544 0.192 116.568 ;
    END
  END otag[13]
  PIN otag[14]
    DIRECTION OUTPUT ;
    USE SIGNAL ;
    PORT
      LAYER M4 ;
        RECT  0 116.736 0.192 116.76 ;
    END
  END otag[14]
  PIN otag[15]
    DIRECTION OUTPUT ;
    USE SIGNAL ;
    PORT
      LAYER M4 ;
        RECT  0 116.928 0.192 116.952 ;
    END
  END otag[15]
  PIN otag[1]
    DIRECTION OUTPUT ;
    USE SIGNAL ;
    PORT
      LAYER M4 ;
        RECT  0 114.24 0.192 114.264 ;
    END
  END otag[1]
  PIN otag[2]
    DIRECTION OUTPUT ;
    USE SIGNAL ;
    PORT
      LAYER M4 ;
        RECT  0 114.432 0.192 114.456 ;
    END
  END otag[2]
  PIN otag[3]
    DIRECTION OUTPUT ;
    USE SIGNAL ;
    PORT
      LAYER M4 ;
        RECT  0 114.624 0.192 114.648 ;
    END
  END otag[3]
  PIN otag[4]
    DIRECTION OUTPUT ;
    USE SIGNAL ;
    PORT
      LAYER M4 ;
        RECT  0 114.816 0.192 114.84 ;
    END
  END otag[4]
  PIN otag[5]
    DIRECTION OUTPUT ;
    USE SIGNAL ;
    PORT
      LAYER M4 ;
        RECT  0 115.008 0.192 115.032 ;
    END
  END otag[5]
  PIN otag[6]
    DIRECTION OUTPUT ;
    USE SIGNAL ;
    PORT
      LAYER M4 ;
        RECT  0 115.2 0.192 115.224 ;
    END
  END otag[6]
  PIN otag[7]
    DIRECTION OUTPUT ;
    USE SIGNAL ;
    PORT
      LAYER M4 ;
        RECT  0 115.392 0.192 115.416 ;
    END
  END otag[7]
  PIN otag[8]
    DIRECTION OUTPUT ;
    USE SIGNAL ;
    PORT
      LAYER M4 ;
        RECT  0 115.584 0.192 115.608 ;
    END
  END otag[8]
  PIN otag[9]
    DIRECTION OUTPUT ;
    USE SIGNAL ;
    PORT
      LAYER M4 ;
        RECT  0 115.776 0.192 115.8 ;
    END
  END otag[9]
  PIN ov
    DIRECTION OUTPUT ;
    USE SIGNAL ;
    PORT
      LAYER M4 ;
        RECT  0 107.52 0.192 107.544 ;
    END
  END ov
  PIN rst_a
    DIRECTION INPUT ;
    USE SIGNAL ;
    PORT
      LAYER M5 ;
        RECT  39.36 224.448 39.384 224.64 ;
    END
  END rst_a
  PIN y[0]
    DIRECTION OUTPUT ;
    USE SIGNAL ;
    PORT
      LAYER M4 ;
        RECT  0 107.904 0.192 107.928 ;
    END
  END y[0]
  PIN y[10]
    DIRECTION OUTPUT ;
    USE SIGNAL ;
    PORT
      LAYER M4 ;
        RECT  0 109.824 0.192 109.848 ;
    END
  END y[10]
  PIN y[11]
    DIRECTION OUTPUT ;
    USE SIGNAL ;
    PORT
      LAYER M4 ;
        RECT  0 110.016 0.192 110.04 ;
    END
  END y[11]
  PIN y[12]
    DIRECTION OUTPUT ;
    USE SIGNAL ;
    PORT
      LAYER M4 ;
        RECT  0 110.208 0.192 110.232 ;
    END
  END y[12]
  PIN y[13]
    DIRECTION OUTPUT ;
    USE SIGNAL ;
    PORT
      LAYER M4 ;
        RECT  0 110.4 0.192 110.424 ;
    END
  END y[13]
  PIN y[14]
    DIRECTION OUTPUT ;
    USE SIGNAL ;
    PORT
      LAYER M4 ;
        RECT  0 110.592 0.192 110.616 ;
    END
  END y[14]
  PIN y[15]
    DIRECTION OUTPUT ;
    USE SIGNAL ;
    PORT
      LAYER M4 ;
        RECT  0 110.784 0.192 110.808 ;
    END
  END y[15]
  PIN y[16]
    DIRECTION OUTPUT ;
    USE SIGNAL ;
    PORT
      LAYER M4 ;
        RECT  0 110.976 0.192 111 ;
    END
  END y[16]
  PIN y[17]
    DIRECTION OUTPUT ;
    USE SIGNAL ;
    PORT
      LAYER M4 ;
        RECT  0 111.168 0.192 111.192 ;
    END
  END y[17]
  PIN y[18]
    DIRECTION OUTPUT ;
    USE SIGNAL ;
    PORT
      LAYER M4 ;
        RECT  0 111.36 0.192 111.384 ;
    END
  END y[18]
  PIN y[19]
    DIRECTION OUTPUT ;
    USE SIGNAL ;
    PORT
      LAYER M4 ;
        RECT  0 111.552 0.192 111.576 ;
    END
  END y[19]
  PIN y[1]
    DIRECTION OUTPUT ;
    USE SIGNAL ;
    PORT
      LAYER M4 ;
        RECT  0 108.096 0.192 108.12 ;
    END
  END y[1]
  PIN y[20]
    DIRECTION OUTPUT ;
    USE SIGNAL ;
    PORT
      LAYER M4 ;
        RECT  0 111.744 0.192 111.768 ;
    END
  END y[20]
  PIN y[21]
    DIRECTION OUTPUT ;
    USE SIGNAL ;
    PORT
      LAYER M4 ;
        RECT  0 111.936 0.192 111.96 ;
    END
  END y[21]
  PIN y[22]
    DIRECTION OUTPUT ;
    USE SIGNAL ;
    PORT
      LAYER M4 ;
        RECT  0 112.128 0.192 112.152 ;
    END
  END y[22]
  PIN y[23]
    DIRECTION OUTPUT ;
    USE SIGNAL ;
    PORT
      LAYER M4 ;
        RECT  0 112.32 0.192 112.344 ;
    END
  END y[23]
  PIN y[24]
    DIRECTION OUTPUT ;
    USE SIGNAL ;
    PORT
      LAYER M4 ;
        RECT  0 112.512 0.192 112.536 ;
    END
  END y[24]
  PIN y[25]
    DIRECTION OUTPUT ;
    USE SIGNAL ;
    PORT
      LAYER M4 ;
        RECT  0 112.704 0.192 112.728 ;
    END
  END y[25]
  PIN y[26]
    DIRECTION OUTPUT ;
    USE SIGNAL ;
    PORT
      LAYER M4 ;
        RECT  0 112.896 0.192 112.92 ;
    END
  END y[26]
  PIN y[27]
    DIRECTION OUTPUT ;
    USE SIGNAL ;
    PORT
      LAYER M4 ;
        RECT  0 113.088 0.192 113.112 ;
    END
  END y[27]
  PIN y[28]
    DIRECTION OUTPUT ;
    USE SIGNAL ;
    PORT
      LAYER M4 ;
        RECT  0 113.28 0.192 113.304 ;
    END
  END y[28]
  PIN y[29]
    DIRECTION OUTPUT ;
    USE SIGNAL ;
    PORT
      LAYER M4 ;
        RECT  0 113.472 0.192 113.496 ;
    END
  END y[29]
  PIN y[2]
    DIRECTION OUTPUT ;
    USE SIGNAL ;
    PORT
      LAYER M4 ;
        RECT  0 108.288 0.192 108.312 ;
    END
  END y[2]
  PIN y[30]
    DIRECTION OUTPUT ;
    USE SIGNAL ;
    PORT
      LAYER M4 ;
        RECT  0 113.664 0.192 113.688 ;
    END
  END y[30]
  PIN y[31]
    DIRECTION OUTPUT ;
    USE SIGNAL ;
    PORT
      LAYER M4 ;
        RECT  0 113.856 0.192 113.88 ;
    END
  END y[31]
  PIN y[3]
    DIRECTION OUTPUT ;
    USE SIGNAL ;
    PORT
      LAYER M4 ;
        RECT  0 108.48 0.192 108.504 ;
    END
  END y[3]
  PIN y[4]
    DIRECTION OUTPUT ;
    USE SIGNAL ;
    PORT
      LAYER M4 ;
        RECT  0 108.672 0.192 108.696 ;
    END
  END y[4]
  PIN y[5]
    DIRECTION OUTPUT ;
    USE SIGNAL ;
    PORT
      LAYER M4 ;
        RECT  0 108.864 0.192 108.888 ;
    END
  END y[5]
  PIN y[6]
    DIRECTION OUTPUT ;
    USE SIGNAL ;
    PORT
      LAYER M4 ;
        RECT  0 109.056 0.192 109.08 ;
    END
  END y[6]
  PIN y[7]
    DIRECTION OUTPUT ;
    USE SIGNAL ;
    PORT
      LAYER M4 ;
        RECT  0 109.248 0.192 109.272 ;
    END
  END y[7]
  PIN y[8]
    DIRECTION OUTPUT ;
    USE SIGNAL ;
    PORT
      LAYER M4 ;
        RECT  0 109.44 0.192 109.464 ;
    END
  END y[8]
  PIN y[9]
    DIRECTION OUTPUT ;
    USE SIGNAL ;
    PORT
      LAYER M4 ;
        RECT  0 109.632 0.192 109.656 ;
    END
  END y[9]
  PIN VDD
    DIRECTION INOUT ;
    USE POWER ;
    PORT
      LAYER M6 ;
        RECT  0.468 219.32 77.292 219.608 ;
        RECT  0.468 208.52 77.292 208.808 ;
        RECT  0.468 197.72 77.292 198.008 ;
        RECT  0.468 186.92 77.292 187.208 ;
        RECT  0.468 176.12 77.292 176.408 ;
        RECT  0.468 165.32 77.292 165.608 ;
        RECT  0.468 154.52 77.292 154.808 ;
        RECT  0.468 143.72 77.292 144.008 ;
        RECT  0.468 132.92 77.292 133.208 ;
        RECT  0.468 122.12 77.292 122.408 ;
        RECT  0.468 111.32 77.292 111.608 ;
        RECT  0.468 100.52 77.292 100.808 ;
        RECT  0.468 89.72 77.292 90.008 ;
        RECT  0.468 78.92 77.292 79.208 ;
        RECT  0.468 68.12 77.292 68.408 ;
        RECT  0.468 57.32 77.292 57.608 ;
        RECT  0.468 46.52 77.292 46.808 ;
        RECT  0.468 35.72 77.292 36.008 ;
        RECT  0.468 24.92 77.292 25.208 ;
        RECT  0.468 14.12 77.292 14.408 ;
        RECT  0.468 3.32 77.292 3.608 ;
        RECT  0.468 224.244 77.292 224.532 ;
        RECT  0.468 0.108 77.292 0.396 ;
    END
  END VDD
  PIN VSS
    DIRECTION INOUT ;
    USE GROUND ;
    PORT
      LAYER M6 ;
        RECT  0.468 218.936 77.292 219.224 ;
        RECT  0.468 208.136 77.292 208.424 ;
        RECT  0.468 197.336 77.292 197.624 ;
        RECT  0.468 186.536 77.292 186.824 ;
        RECT  0.468 175.736 77.292 176.024 ;
        RECT  0.468 164.936 77.292 165.224 ;
        RECT  0.468 154.136 77.292 154.424 ;
        RECT  0.468 143.336 77.292 143.624 ;
        RECT  0.468 132.536 77.292 132.824 ;
        RECT  0.468 121.736 77.292 122.024 ;
        RECT  0.468 110.936 77.292 111.224 ;
        RECT  0.468 100.136 77.292 100.424 ;
        RECT  0.468 89.336 77.292 89.624 ;
        RECT  0.468 78.536 77.292 78.824 ;
        RECT  0.468 67.736 77.292 68.024 ;
        RECT  0.468 56.936 77.292 57.224 ;
        RECT  0.468 46.136 77.292 46.424 ;
        RECT  0.468 35.336 77.292 35.624 ;
        RECT  0.468 24.536 77.292 24.824 ;
        RECT  0.468 13.736 77.292 14.024 ;
        RECT  0.468 2.936 77.292 3.224 ;
        RECT  0.66 223.86 77.1 224.148 ;
        RECT  0.66 0.492 77.1 0.78 ;
    END
  END VSS
  OBS
    LAYER RVTN ;
     RECT  0 0.108 77.76 224.64 ;
    LAYER RVTP ;
     RECT  0 0.108 77.76 224.64 ;
    LAYER M1 ;
     RECT  0 0.108 77.76 224.64 ;
    LAYER M2 ;
     RECT  0 0.108 77.76 224.64 ;
    LAYER M3 ;
     RECT  0 0.108 77.76 224.64 ;
    LAYER M4 ;
     RECT  0 0.108 77.76 224.64 ;
    LAYER M5 ;
     RECT  0 0.108 77.76 224.64 ;
    LAYER M6 ;
     RECT  0 0.108 77.76 224.64 ;
    LAYER M7 ;
     RECT  0 0.108 77.76 224.64 ;
  END
END ot_hbm_accel_smh_bdc
END LIBRARY
